VERSION 5.7 ;
BUSBITCHARS "[]" ;
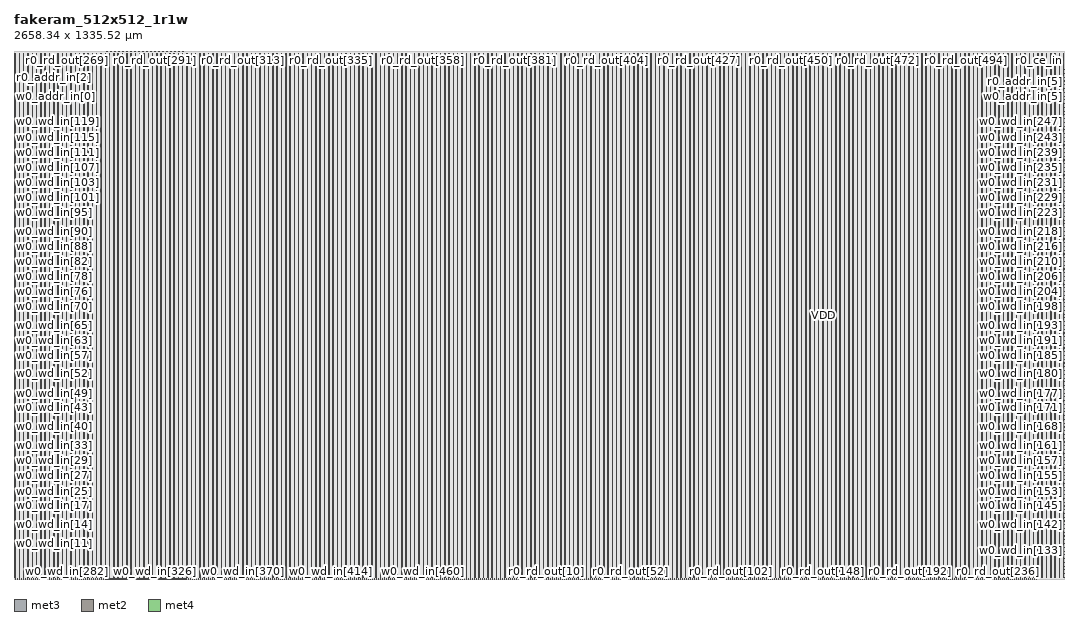
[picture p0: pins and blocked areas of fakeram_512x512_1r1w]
MACRO fakeram_512x512_1r1w
  FOREIGN fakeram_512x512_1r1w 0 0 ;
  SYMMETRY X Y R90 ;
  SIZE 2658.340 BY 1335.520 ;
  CLASS BLOCK ;
  PIN w0_wd_in[0]
    DIRECTION INPUT ;
    USE SIGNAL ;
    SHAPE ABUTMENT ;
    PORT
      LAYER met3 ;
      RECT 0.000 3.930 0.900 4.230 ;
    END
  END w0_wd_in[0]
  PIN w0_wd_in[1]
    DIRECTION INPUT ;
    USE SIGNAL ;
    SHAPE ABUTMENT ;
    PORT
      LAYER met3 ;
      RECT 0.000 13.450 0.900 13.750 ;
    END
  END w0_wd_in[1]
  PIN w0_wd_in[2]
    DIRECTION INPUT ;
    USE SIGNAL ;
    SHAPE ABUTMENT ;
    PORT
      LAYER met3 ;
      RECT 0.000 22.970 0.900 23.270 ;
    END
  END w0_wd_in[2]
  PIN w0_wd_in[3]
    DIRECTION INPUT ;
    USE SIGNAL ;
    SHAPE ABUTMENT ;
    PORT
      LAYER met3 ;
      RECT 0.000 32.490 0.900 32.790 ;
    END
  END w0_wd_in[3]
  PIN w0_wd_in[4]
    DIRECTION INPUT ;
    USE SIGNAL ;
    SHAPE ABUTMENT ;
    PORT
      LAYER met3 ;
      RECT 0.000 42.010 0.900 42.310 ;
    END
  END w0_wd_in[4]
  PIN w0_wd_in[5]
    DIRECTION INPUT ;
    USE SIGNAL ;
    SHAPE ABUTMENT ;
    PORT
      LAYER met3 ;
      RECT 0.000 51.530 0.900 51.830 ;
    END
  END w0_wd_in[5]
  PIN w0_wd_in[6]
    DIRECTION INPUT ;
    USE SIGNAL ;
    SHAPE ABUTMENT ;
    PORT
      LAYER met3 ;
      RECT 0.000 61.050 0.900 61.350 ;
    END
  END w0_wd_in[6]
  PIN w0_wd_in[7]
    DIRECTION INPUT ;
    USE SIGNAL ;
    SHAPE ABUTMENT ;
    PORT
      LAYER met3 ;
      RECT 0.000 70.570 0.900 70.870 ;
    END
  END w0_wd_in[7]
  PIN w0_wd_in[8]
    DIRECTION INPUT ;
    USE SIGNAL ;
    SHAPE ABUTMENT ;
    PORT
      LAYER met3 ;
      RECT 0.000 80.090 0.900 80.390 ;
    END
  END w0_wd_in[8]
  PIN w0_wd_in[9]
    DIRECTION INPUT ;
    USE SIGNAL ;
    SHAPE ABUTMENT ;
    PORT
      LAYER met3 ;
      RECT 0.000 89.610 0.900 89.910 ;
    END
  END w0_wd_in[9]
  PIN w0_wd_in[10]
    DIRECTION INPUT ;
    USE SIGNAL ;
    SHAPE ABUTMENT ;
    PORT
      LAYER met3 ;
      RECT 0.000 99.130 0.900 99.430 ;
    END
  END w0_wd_in[10]
  PIN w0_wd_in[11]
    DIRECTION INPUT ;
    USE SIGNAL ;
    SHAPE ABUTMENT ;
    PORT
      LAYER met3 ;
      RECT 0.000 108.650 0.900 108.950 ;
    END
  END w0_wd_in[11]
  PIN w0_wd_in[12]
    DIRECTION INPUT ;
    USE SIGNAL ;
    SHAPE ABUTMENT ;
    PORT
      LAYER met3 ;
      RECT 0.000 118.170 0.900 118.470 ;
    END
  END w0_wd_in[12]
  PIN w0_wd_in[13]
    DIRECTION INPUT ;
    USE SIGNAL ;
    SHAPE ABUTMENT ;
    PORT
      LAYER met3 ;
      RECT 0.000 127.690 0.900 127.990 ;
    END
  END w0_wd_in[13]
  PIN w0_wd_in[14]
    DIRECTION INPUT ;
    USE SIGNAL ;
    SHAPE ABUTMENT ;
    PORT
      LAYER met3 ;
      RECT 0.000 137.210 0.900 137.510 ;
    END
  END w0_wd_in[14]
  PIN w0_wd_in[15]
    DIRECTION INPUT ;
    USE SIGNAL ;
    SHAPE ABUTMENT ;
    PORT
      LAYER met3 ;
      RECT 0.000 146.730 0.900 147.030 ;
    END
  END w0_wd_in[15]
  PIN w0_wd_in[16]
    DIRECTION INPUT ;
    USE SIGNAL ;
    SHAPE ABUTMENT ;
    PORT
      LAYER met3 ;
      RECT 0.000 156.250 0.900 156.550 ;
    END
  END w0_wd_in[16]
  PIN w0_wd_in[17]
    DIRECTION INPUT ;
    USE SIGNAL ;
    SHAPE ABUTMENT ;
    PORT
      LAYER met3 ;
      RECT 0.000 165.770 0.900 166.070 ;
    END
  END w0_wd_in[17]
  PIN w0_wd_in[18]
    DIRECTION INPUT ;
    USE SIGNAL ;
    SHAPE ABUTMENT ;
    PORT
      LAYER met3 ;
      RECT 0.000 175.290 0.900 175.590 ;
    END
  END w0_wd_in[18]
  PIN w0_wd_in[19]
    DIRECTION INPUT ;
    USE SIGNAL ;
    SHAPE ABUTMENT ;
    PORT
      LAYER met3 ;
      RECT 0.000 184.810 0.900 185.110 ;
    END
  END w0_wd_in[19]
  PIN w0_wd_in[20]
    DIRECTION INPUT ;
    USE SIGNAL ;
    SHAPE ABUTMENT ;
    PORT
      LAYER met3 ;
      RECT 0.000 194.330 0.900 194.630 ;
    END
  END w0_wd_in[20]
  PIN w0_wd_in[21]
    DIRECTION INPUT ;
    USE SIGNAL ;
    SHAPE ABUTMENT ;
    PORT
      LAYER met3 ;
      RECT 0.000 203.850 0.900 204.150 ;
    END
  END w0_wd_in[21]
  PIN w0_wd_in[22]
    DIRECTION INPUT ;
    USE SIGNAL ;
    SHAPE ABUTMENT ;
    PORT
      LAYER met3 ;
      RECT 0.000 213.370 0.900 213.670 ;
    END
  END w0_wd_in[22]
  PIN w0_wd_in[23]
    DIRECTION INPUT ;
    USE SIGNAL ;
    SHAPE ABUTMENT ;
    PORT
      LAYER met3 ;
      RECT 0.000 222.890 0.900 223.190 ;
    END
  END w0_wd_in[23]
  PIN w0_wd_in[24]
    DIRECTION INPUT ;
    USE SIGNAL ;
    SHAPE ABUTMENT ;
    PORT
      LAYER met3 ;
      RECT 0.000 232.410 0.900 232.710 ;
    END
  END w0_wd_in[24]
  PIN w0_wd_in[25]
    DIRECTION INPUT ;
    USE SIGNAL ;
    SHAPE ABUTMENT ;
    PORT
      LAYER met3 ;
      RECT 0.000 241.930 0.900 242.230 ;
    END
  END w0_wd_in[25]
  PIN w0_wd_in[26]
    DIRECTION INPUT ;
    USE SIGNAL ;
    SHAPE ABUTMENT ;
    PORT
      LAYER met3 ;
      RECT 0.000 251.450 0.900 251.750 ;
    END
  END w0_wd_in[26]
  PIN w0_wd_in[27]
    DIRECTION INPUT ;
    USE SIGNAL ;
    SHAPE ABUTMENT ;
    PORT
      LAYER met3 ;
      RECT 0.000 260.970 0.900 261.270 ;
    END
  END w0_wd_in[27]
  PIN w0_wd_in[28]
    DIRECTION INPUT ;
    USE SIGNAL ;
    SHAPE ABUTMENT ;
    PORT
      LAYER met3 ;
      RECT 0.000 270.490 0.900 270.790 ;
    END
  END w0_wd_in[28]
  PIN w0_wd_in[29]
    DIRECTION INPUT ;
    USE SIGNAL ;
    SHAPE ABUTMENT ;
    PORT
      LAYER met3 ;
      RECT 0.000 280.010 0.900 280.310 ;
    END
  END w0_wd_in[29]
  PIN w0_wd_in[30]
    DIRECTION INPUT ;
    USE SIGNAL ;
    SHAPE ABUTMENT ;
    PORT
      LAYER met3 ;
      RECT 0.000 289.530 0.900 289.830 ;
    END
  END w0_wd_in[30]
  PIN w0_wd_in[31]
    DIRECTION INPUT ;
    USE SIGNAL ;
    SHAPE ABUTMENT ;
    PORT
      LAYER met3 ;
      RECT 0.000 299.050 0.900 299.350 ;
    END
  END w0_wd_in[31]
  PIN w0_wd_in[32]
    DIRECTION INPUT ;
    USE SIGNAL ;
    SHAPE ABUTMENT ;
    PORT
      LAYER met3 ;
      RECT 0.000 308.570 0.900 308.870 ;
    END
  END w0_wd_in[32]
  PIN w0_wd_in[33]
    DIRECTION INPUT ;
    USE SIGNAL ;
    SHAPE ABUTMENT ;
    PORT
      LAYER met3 ;
      RECT 0.000 318.090 0.900 318.390 ;
    END
  END w0_wd_in[33]
  PIN w0_wd_in[34]
    DIRECTION INPUT ;
    USE SIGNAL ;
    SHAPE ABUTMENT ;
    PORT
      LAYER met3 ;
      RECT 0.000 327.610 0.900 327.910 ;
    END
  END w0_wd_in[34]
  PIN w0_wd_in[35]
    DIRECTION INPUT ;
    USE SIGNAL ;
    SHAPE ABUTMENT ;
    PORT
      LAYER met3 ;
      RECT 0.000 337.130 0.900 337.430 ;
    END
  END w0_wd_in[35]
  PIN w0_wd_in[36]
    DIRECTION INPUT ;
    USE SIGNAL ;
    SHAPE ABUTMENT ;
    PORT
      LAYER met3 ;
      RECT 0.000 346.650 0.900 346.950 ;
    END
  END w0_wd_in[36]
  PIN w0_wd_in[37]
    DIRECTION INPUT ;
    USE SIGNAL ;
    SHAPE ABUTMENT ;
    PORT
      LAYER met3 ;
      RECT 0.000 356.170 0.900 356.470 ;
    END
  END w0_wd_in[37]
  PIN w0_wd_in[38]
    DIRECTION INPUT ;
    USE SIGNAL ;
    SHAPE ABUTMENT ;
    PORT
      LAYER met3 ;
      RECT 0.000 365.690 0.900 365.990 ;
    END
  END w0_wd_in[38]
  PIN w0_wd_in[39]
    DIRECTION INPUT ;
    USE SIGNAL ;
    SHAPE ABUTMENT ;
    PORT
      LAYER met3 ;
      RECT 0.000 375.210 0.900 375.510 ;
    END
  END w0_wd_in[39]
  PIN w0_wd_in[40]
    DIRECTION INPUT ;
    USE SIGNAL ;
    SHAPE ABUTMENT ;
    PORT
      LAYER met3 ;
      RECT 0.000 384.730 0.900 385.030 ;
    END
  END w0_wd_in[40]
  PIN w0_wd_in[41]
    DIRECTION INPUT ;
    USE SIGNAL ;
    SHAPE ABUTMENT ;
    PORT
      LAYER met3 ;
      RECT 0.000 394.250 0.900 394.550 ;
    END
  END w0_wd_in[41]
  PIN w0_wd_in[42]
    DIRECTION INPUT ;
    USE SIGNAL ;
    SHAPE ABUTMENT ;
    PORT
      LAYER met3 ;
      RECT 0.000 403.770 0.900 404.070 ;
    END
  END w0_wd_in[42]
  PIN w0_wd_in[43]
    DIRECTION INPUT ;
    USE SIGNAL ;
    SHAPE ABUTMENT ;
    PORT
      LAYER met3 ;
      RECT 0.000 413.290 0.900 413.590 ;
    END
  END w0_wd_in[43]
  PIN w0_wd_in[44]
    DIRECTION INPUT ;
    USE SIGNAL ;
    SHAPE ABUTMENT ;
    PORT
      LAYER met3 ;
      RECT 0.000 422.810 0.900 423.110 ;
    END
  END w0_wd_in[44]
  PIN w0_wd_in[45]
    DIRECTION INPUT ;
    USE SIGNAL ;
    SHAPE ABUTMENT ;
    PORT
      LAYER met3 ;
      RECT 0.000 432.330 0.900 432.630 ;
    END
  END w0_wd_in[45]
  PIN w0_wd_in[46]
    DIRECTION INPUT ;
    USE SIGNAL ;
    SHAPE ABUTMENT ;
    PORT
      LAYER met3 ;
      RECT 0.000 441.850 0.900 442.150 ;
    END
  END w0_wd_in[46]
  PIN w0_wd_in[47]
    DIRECTION INPUT ;
    USE SIGNAL ;
    SHAPE ABUTMENT ;
    PORT
      LAYER met3 ;
      RECT 0.000 451.370 0.900 451.670 ;
    END
  END w0_wd_in[47]
  PIN w0_wd_in[48]
    DIRECTION INPUT ;
    USE SIGNAL ;
    SHAPE ABUTMENT ;
    PORT
      LAYER met3 ;
      RECT 0.000 460.890 0.900 461.190 ;
    END
  END w0_wd_in[48]
  PIN w0_wd_in[49]
    DIRECTION INPUT ;
    USE SIGNAL ;
    SHAPE ABUTMENT ;
    PORT
      LAYER met3 ;
      RECT 0.000 470.410 0.900 470.710 ;
    END
  END w0_wd_in[49]
  PIN w0_wd_in[50]
    DIRECTION INPUT ;
    USE SIGNAL ;
    SHAPE ABUTMENT ;
    PORT
      LAYER met3 ;
      RECT 0.000 479.930 0.900 480.230 ;
    END
  END w0_wd_in[50]
  PIN w0_wd_in[51]
    DIRECTION INPUT ;
    USE SIGNAL ;
    SHAPE ABUTMENT ;
    PORT
      LAYER met3 ;
      RECT 0.000 489.450 0.900 489.750 ;
    END
  END w0_wd_in[51]
  PIN w0_wd_in[52]
    DIRECTION INPUT ;
    USE SIGNAL ;
    SHAPE ABUTMENT ;
    PORT
      LAYER met3 ;
      RECT 0.000 498.970 0.900 499.270 ;
    END
  END w0_wd_in[52]
  PIN w0_wd_in[53]
    DIRECTION INPUT ;
    USE SIGNAL ;
    SHAPE ABUTMENT ;
    PORT
      LAYER met3 ;
      RECT 0.000 508.490 0.900 508.790 ;
    END
  END w0_wd_in[53]
  PIN w0_wd_in[54]
    DIRECTION INPUT ;
    USE SIGNAL ;
    SHAPE ABUTMENT ;
    PORT
      LAYER met3 ;
      RECT 0.000 518.010 0.900 518.310 ;
    END
  END w0_wd_in[54]
  PIN w0_wd_in[55]
    DIRECTION INPUT ;
    USE SIGNAL ;
    SHAPE ABUTMENT ;
    PORT
      LAYER met3 ;
      RECT 0.000 527.530 0.900 527.830 ;
    END
  END w0_wd_in[55]
  PIN w0_wd_in[56]
    DIRECTION INPUT ;
    USE SIGNAL ;
    SHAPE ABUTMENT ;
    PORT
      LAYER met3 ;
      RECT 0.000 537.050 0.900 537.350 ;
    END
  END w0_wd_in[56]
  PIN w0_wd_in[57]
    DIRECTION INPUT ;
    USE SIGNAL ;
    SHAPE ABUTMENT ;
    PORT
      LAYER met3 ;
      RECT 0.000 546.570 0.900 546.870 ;
    END
  END w0_wd_in[57]
  PIN w0_wd_in[58]
    DIRECTION INPUT ;
    USE SIGNAL ;
    SHAPE ABUTMENT ;
    PORT
      LAYER met3 ;
      RECT 0.000 556.090 0.900 556.390 ;
    END
  END w0_wd_in[58]
  PIN w0_wd_in[59]
    DIRECTION INPUT ;
    USE SIGNAL ;
    SHAPE ABUTMENT ;
    PORT
      LAYER met3 ;
      RECT 0.000 565.610 0.900 565.910 ;
    END
  END w0_wd_in[59]
  PIN w0_wd_in[60]
    DIRECTION INPUT ;
    USE SIGNAL ;
    SHAPE ABUTMENT ;
    PORT
      LAYER met3 ;
      RECT 0.000 575.130 0.900 575.430 ;
    END
  END w0_wd_in[60]
  PIN w0_wd_in[61]
    DIRECTION INPUT ;
    USE SIGNAL ;
    SHAPE ABUTMENT ;
    PORT
      LAYER met3 ;
      RECT 0.000 584.650 0.900 584.950 ;
    END
  END w0_wd_in[61]
  PIN w0_wd_in[62]
    DIRECTION INPUT ;
    USE SIGNAL ;
    SHAPE ABUTMENT ;
    PORT
      LAYER met3 ;
      RECT 0.000 594.170 0.900 594.470 ;
    END
  END w0_wd_in[62]
  PIN w0_wd_in[63]
    DIRECTION INPUT ;
    USE SIGNAL ;
    SHAPE ABUTMENT ;
    PORT
      LAYER met3 ;
      RECT 0.000 603.690 0.900 603.990 ;
    END
  END w0_wd_in[63]
  PIN w0_wd_in[64]
    DIRECTION INPUT ;
    USE SIGNAL ;
    SHAPE ABUTMENT ;
    PORT
      LAYER met3 ;
      RECT 0.000 613.210 0.900 613.510 ;
    END
  END w0_wd_in[64]
  PIN w0_wd_in[65]
    DIRECTION INPUT ;
    USE SIGNAL ;
    SHAPE ABUTMENT ;
    PORT
      LAYER met3 ;
      RECT 0.000 622.730 0.900 623.030 ;
    END
  END w0_wd_in[65]
  PIN w0_wd_in[66]
    DIRECTION INPUT ;
    USE SIGNAL ;
    SHAPE ABUTMENT ;
    PORT
      LAYER met3 ;
      RECT 0.000 632.250 0.900 632.550 ;
    END
  END w0_wd_in[66]
  PIN w0_wd_in[67]
    DIRECTION INPUT ;
    USE SIGNAL ;
    SHAPE ABUTMENT ;
    PORT
      LAYER met3 ;
      RECT 0.000 641.770 0.900 642.070 ;
    END
  END w0_wd_in[67]
  PIN w0_wd_in[68]
    DIRECTION INPUT ;
    USE SIGNAL ;
    SHAPE ABUTMENT ;
    PORT
      LAYER met3 ;
      RECT 0.000 651.290 0.900 651.590 ;
    END
  END w0_wd_in[68]
  PIN w0_wd_in[69]
    DIRECTION INPUT ;
    USE SIGNAL ;
    SHAPE ABUTMENT ;
    PORT
      LAYER met3 ;
      RECT 0.000 660.810 0.900 661.110 ;
    END
  END w0_wd_in[69]
  PIN w0_wd_in[70]
    DIRECTION INPUT ;
    USE SIGNAL ;
    SHAPE ABUTMENT ;
    PORT
      LAYER met3 ;
      RECT 0.000 670.330 0.900 670.630 ;
    END
  END w0_wd_in[70]
  PIN w0_wd_in[71]
    DIRECTION INPUT ;
    USE SIGNAL ;
    SHAPE ABUTMENT ;
    PORT
      LAYER met3 ;
      RECT 0.000 679.850 0.900 680.150 ;
    END
  END w0_wd_in[71]
  PIN w0_wd_in[72]
    DIRECTION INPUT ;
    USE SIGNAL ;
    SHAPE ABUTMENT ;
    PORT
      LAYER met3 ;
      RECT 0.000 689.370 0.900 689.670 ;
    END
  END w0_wd_in[72]
  PIN w0_wd_in[73]
    DIRECTION INPUT ;
    USE SIGNAL ;
    SHAPE ABUTMENT ;
    PORT
      LAYER met3 ;
      RECT 0.000 698.890 0.900 699.190 ;
    END
  END w0_wd_in[73]
  PIN w0_wd_in[74]
    DIRECTION INPUT ;
    USE SIGNAL ;
    SHAPE ABUTMENT ;
    PORT
      LAYER met3 ;
      RECT 0.000 708.410 0.900 708.710 ;
    END
  END w0_wd_in[74]
  PIN w0_wd_in[75]
    DIRECTION INPUT ;
    USE SIGNAL ;
    SHAPE ABUTMENT ;
    PORT
      LAYER met3 ;
      RECT 0.000 717.930 0.900 718.230 ;
    END
  END w0_wd_in[75]
  PIN w0_wd_in[76]
    DIRECTION INPUT ;
    USE SIGNAL ;
    SHAPE ABUTMENT ;
    PORT
      LAYER met3 ;
      RECT 0.000 727.450 0.900 727.750 ;
    END
  END w0_wd_in[76]
  PIN w0_wd_in[77]
    DIRECTION INPUT ;
    USE SIGNAL ;
    SHAPE ABUTMENT ;
    PORT
      LAYER met3 ;
      RECT 0.000 736.970 0.900 737.270 ;
    END
  END w0_wd_in[77]
  PIN w0_wd_in[78]
    DIRECTION INPUT ;
    USE SIGNAL ;
    SHAPE ABUTMENT ;
    PORT
      LAYER met3 ;
      RECT 0.000 746.490 0.900 746.790 ;
    END
  END w0_wd_in[78]
  PIN w0_wd_in[79]
    DIRECTION INPUT ;
    USE SIGNAL ;
    SHAPE ABUTMENT ;
    PORT
      LAYER met3 ;
      RECT 0.000 756.010 0.900 756.310 ;
    END
  END w0_wd_in[79]
  PIN w0_wd_in[80]
    DIRECTION INPUT ;
    USE SIGNAL ;
    SHAPE ABUTMENT ;
    PORT
      LAYER met3 ;
      RECT 0.000 765.530 0.900 765.830 ;
    END
  END w0_wd_in[80]
  PIN w0_wd_in[81]
    DIRECTION INPUT ;
    USE SIGNAL ;
    SHAPE ABUTMENT ;
    PORT
      LAYER met3 ;
      RECT 0.000 775.050 0.900 775.350 ;
    END
  END w0_wd_in[81]
  PIN w0_wd_in[82]
    DIRECTION INPUT ;
    USE SIGNAL ;
    SHAPE ABUTMENT ;
    PORT
      LAYER met3 ;
      RECT 0.000 784.570 0.900 784.870 ;
    END
  END w0_wd_in[82]
  PIN w0_wd_in[83]
    DIRECTION INPUT ;
    USE SIGNAL ;
    SHAPE ABUTMENT ;
    PORT
      LAYER met3 ;
      RECT 0.000 794.090 0.900 794.390 ;
    END
  END w0_wd_in[83]
  PIN w0_wd_in[84]
    DIRECTION INPUT ;
    USE SIGNAL ;
    SHAPE ABUTMENT ;
    PORT
      LAYER met3 ;
      RECT 0.000 803.610 0.900 803.910 ;
    END
  END w0_wd_in[84]
  PIN w0_wd_in[85]
    DIRECTION INPUT ;
    USE SIGNAL ;
    SHAPE ABUTMENT ;
    PORT
      LAYER met3 ;
      RECT 0.000 813.130 0.900 813.430 ;
    END
  END w0_wd_in[85]
  PIN w0_wd_in[86]
    DIRECTION INPUT ;
    USE SIGNAL ;
    SHAPE ABUTMENT ;
    PORT
      LAYER met3 ;
      RECT 0.000 822.650 0.900 822.950 ;
    END
  END w0_wd_in[86]
  PIN w0_wd_in[87]
    DIRECTION INPUT ;
    USE SIGNAL ;
    SHAPE ABUTMENT ;
    PORT
      LAYER met3 ;
      RECT 0.000 832.170 0.900 832.470 ;
    END
  END w0_wd_in[87]
  PIN w0_wd_in[88]
    DIRECTION INPUT ;
    USE SIGNAL ;
    SHAPE ABUTMENT ;
    PORT
      LAYER met3 ;
      RECT 0.000 841.690 0.900 841.990 ;
    END
  END w0_wd_in[88]
  PIN w0_wd_in[89]
    DIRECTION INPUT ;
    USE SIGNAL ;
    SHAPE ABUTMENT ;
    PORT
      LAYER met3 ;
      RECT 0.000 851.210 0.900 851.510 ;
    END
  END w0_wd_in[89]
  PIN w0_wd_in[90]
    DIRECTION INPUT ;
    USE SIGNAL ;
    SHAPE ABUTMENT ;
    PORT
      LAYER met3 ;
      RECT 0.000 860.730 0.900 861.030 ;
    END
  END w0_wd_in[90]
  PIN w0_wd_in[91]
    DIRECTION INPUT ;
    USE SIGNAL ;
    SHAPE ABUTMENT ;
    PORT
      LAYER met3 ;
      RECT 0.000 870.250 0.900 870.550 ;
    END
  END w0_wd_in[91]
  PIN w0_wd_in[92]
    DIRECTION INPUT ;
    USE SIGNAL ;
    SHAPE ABUTMENT ;
    PORT
      LAYER met3 ;
      RECT 0.000 879.770 0.900 880.070 ;
    END
  END w0_wd_in[92]
  PIN w0_wd_in[93]
    DIRECTION INPUT ;
    USE SIGNAL ;
    SHAPE ABUTMENT ;
    PORT
      LAYER met3 ;
      RECT 0.000 889.290 0.900 889.590 ;
    END
  END w0_wd_in[93]
  PIN w0_wd_in[94]
    DIRECTION INPUT ;
    USE SIGNAL ;
    SHAPE ABUTMENT ;
    PORT
      LAYER met3 ;
      RECT 0.000 898.810 0.900 899.110 ;
    END
  END w0_wd_in[94]
  PIN w0_wd_in[95]
    DIRECTION INPUT ;
    USE SIGNAL ;
    SHAPE ABUTMENT ;
    PORT
      LAYER met3 ;
      RECT 0.000 908.330 0.900 908.630 ;
    END
  END w0_wd_in[95]
  PIN w0_wd_in[96]
    DIRECTION INPUT ;
    USE SIGNAL ;
    SHAPE ABUTMENT ;
    PORT
      LAYER met3 ;
      RECT 0.000 917.850 0.900 918.150 ;
    END
  END w0_wd_in[96]
  PIN w0_wd_in[97]
    DIRECTION INPUT ;
    USE SIGNAL ;
    SHAPE ABUTMENT ;
    PORT
      LAYER met3 ;
      RECT 0.000 927.370 0.900 927.670 ;
    END
  END w0_wd_in[97]
  PIN w0_wd_in[98]
    DIRECTION INPUT ;
    USE SIGNAL ;
    SHAPE ABUTMENT ;
    PORT
      LAYER met3 ;
      RECT 0.000 936.890 0.900 937.190 ;
    END
  END w0_wd_in[98]
  PIN w0_wd_in[99]
    DIRECTION INPUT ;
    USE SIGNAL ;
    SHAPE ABUTMENT ;
    PORT
      LAYER met3 ;
      RECT 0.000 946.410 0.900 946.710 ;
    END
  END w0_wd_in[99]
  PIN w0_wd_in[100]
    DIRECTION INPUT ;
    USE SIGNAL ;
    SHAPE ABUTMENT ;
    PORT
      LAYER met3 ;
      RECT 0.000 955.930 0.900 956.230 ;
    END
  END w0_wd_in[100]
  PIN w0_wd_in[101]
    DIRECTION INPUT ;
    USE SIGNAL ;
    SHAPE ABUTMENT ;
    PORT
      LAYER met3 ;
      RECT 0.000 965.450 0.900 965.750 ;
    END
  END w0_wd_in[101]
  PIN w0_wd_in[102]
    DIRECTION INPUT ;
    USE SIGNAL ;
    SHAPE ABUTMENT ;
    PORT
      LAYER met3 ;
      RECT 0.000 974.970 0.900 975.270 ;
    END
  END w0_wd_in[102]
  PIN w0_wd_in[103]
    DIRECTION INPUT ;
    USE SIGNAL ;
    SHAPE ABUTMENT ;
    PORT
      LAYER met3 ;
      RECT 0.000 984.490 0.900 984.790 ;
    END
  END w0_wd_in[103]
  PIN w0_wd_in[104]
    DIRECTION INPUT ;
    USE SIGNAL ;
    SHAPE ABUTMENT ;
    PORT
      LAYER met3 ;
      RECT 0.000 994.010 0.900 994.310 ;
    END
  END w0_wd_in[104]
  PIN w0_wd_in[105]
    DIRECTION INPUT ;
    USE SIGNAL ;
    SHAPE ABUTMENT ;
    PORT
      LAYER met3 ;
      RECT 0.000 1003.530 0.900 1003.830 ;
    END
  END w0_wd_in[105]
  PIN w0_wd_in[106]
    DIRECTION INPUT ;
    USE SIGNAL ;
    SHAPE ABUTMENT ;
    PORT
      LAYER met3 ;
      RECT 0.000 1013.050 0.900 1013.350 ;
    END
  END w0_wd_in[106]
  PIN w0_wd_in[107]
    DIRECTION INPUT ;
    USE SIGNAL ;
    SHAPE ABUTMENT ;
    PORT
      LAYER met3 ;
      RECT 0.000 1022.570 0.900 1022.870 ;
    END
  END w0_wd_in[107]
  PIN w0_wd_in[108]
    DIRECTION INPUT ;
    USE SIGNAL ;
    SHAPE ABUTMENT ;
    PORT
      LAYER met3 ;
      RECT 0.000 1032.090 0.900 1032.390 ;
    END
  END w0_wd_in[108]
  PIN w0_wd_in[109]
    DIRECTION INPUT ;
    USE SIGNAL ;
    SHAPE ABUTMENT ;
    PORT
      LAYER met3 ;
      RECT 0.000 1041.610 0.900 1041.910 ;
    END
  END w0_wd_in[109]
  PIN w0_wd_in[110]
    DIRECTION INPUT ;
    USE SIGNAL ;
    SHAPE ABUTMENT ;
    PORT
      LAYER met3 ;
      RECT 0.000 1051.130 0.900 1051.430 ;
    END
  END w0_wd_in[110]
  PIN w0_wd_in[111]
    DIRECTION INPUT ;
    USE SIGNAL ;
    SHAPE ABUTMENT ;
    PORT
      LAYER met3 ;
      RECT 0.000 1060.650 0.900 1060.950 ;
    END
  END w0_wd_in[111]
  PIN w0_wd_in[112]
    DIRECTION INPUT ;
    USE SIGNAL ;
    SHAPE ABUTMENT ;
    PORT
      LAYER met3 ;
      RECT 0.000 1070.170 0.900 1070.470 ;
    END
  END w0_wd_in[112]
  PIN w0_wd_in[113]
    DIRECTION INPUT ;
    USE SIGNAL ;
    SHAPE ABUTMENT ;
    PORT
      LAYER met3 ;
      RECT 0.000 1079.690 0.900 1079.990 ;
    END
  END w0_wd_in[113]
  PIN w0_wd_in[114]
    DIRECTION INPUT ;
    USE SIGNAL ;
    SHAPE ABUTMENT ;
    PORT
      LAYER met3 ;
      RECT 0.000 1089.210 0.900 1089.510 ;
    END
  END w0_wd_in[114]
  PIN w0_wd_in[115]
    DIRECTION INPUT ;
    USE SIGNAL ;
    SHAPE ABUTMENT ;
    PORT
      LAYER met3 ;
      RECT 0.000 1098.730 0.900 1099.030 ;
    END
  END w0_wd_in[115]
  PIN w0_wd_in[116]
    DIRECTION INPUT ;
    USE SIGNAL ;
    SHAPE ABUTMENT ;
    PORT
      LAYER met3 ;
      RECT 0.000 1108.250 0.900 1108.550 ;
    END
  END w0_wd_in[116]
  PIN w0_wd_in[117]
    DIRECTION INPUT ;
    USE SIGNAL ;
    SHAPE ABUTMENT ;
    PORT
      LAYER met3 ;
      RECT 0.000 1117.770 0.900 1118.070 ;
    END
  END w0_wd_in[117]
  PIN w0_wd_in[118]
    DIRECTION INPUT ;
    USE SIGNAL ;
    SHAPE ABUTMENT ;
    PORT
      LAYER met3 ;
      RECT 0.000 1127.290 0.900 1127.590 ;
    END
  END w0_wd_in[118]
  PIN w0_wd_in[119]
    DIRECTION INPUT ;
    USE SIGNAL ;
    SHAPE ABUTMENT ;
    PORT
      LAYER met3 ;
      RECT 0.000 1136.810 0.900 1137.110 ;
    END
  END w0_wd_in[119]
  PIN w0_wd_in[120]
    DIRECTION INPUT ;
    USE SIGNAL ;
    SHAPE ABUTMENT ;
    PORT
      LAYER met3 ;
      RECT 0.000 1146.330 0.900 1146.630 ;
    END
  END w0_wd_in[120]
  PIN w0_wd_in[121]
    DIRECTION INPUT ;
    USE SIGNAL ;
    SHAPE ABUTMENT ;
    PORT
      LAYER met3 ;
      RECT 0.000 1155.850 0.900 1156.150 ;
    END
  END w0_wd_in[121]
  PIN w0_wd_in[122]
    DIRECTION INPUT ;
    USE SIGNAL ;
    SHAPE ABUTMENT ;
    PORT
      LAYER met3 ;
      RECT 0.000 1165.370 0.900 1165.670 ;
    END
  END w0_wd_in[122]
  PIN w0_wd_in[123]
    DIRECTION INPUT ;
    USE SIGNAL ;
    SHAPE ABUTMENT ;
    PORT
      LAYER met3 ;
      RECT 0.000 1174.890 0.900 1175.190 ;
    END
  END w0_wd_in[123]
  PIN w0_wd_in[124]
    DIRECTION INPUT ;
    USE SIGNAL ;
    SHAPE ABUTMENT ;
    PORT
      LAYER met3 ;
      RECT 0.000 1184.410 0.900 1184.710 ;
    END
  END w0_wd_in[124]
  PIN w0_wd_in[125]
    DIRECTION INPUT ;
    USE SIGNAL ;
    SHAPE ABUTMENT ;
    PORT
      LAYER met3 ;
      RECT 0.000 1193.930 0.900 1194.230 ;
    END
  END w0_wd_in[125]
  PIN w0_wd_in[126]
    DIRECTION INPUT ;
    USE SIGNAL ;
    SHAPE ABUTMENT ;
    PORT
      LAYER met3 ;
      RECT 0.000 1203.450 0.900 1203.750 ;
    END
  END w0_wd_in[126]
  PIN w0_wd_in[127]
    DIRECTION INPUT ;
    USE SIGNAL ;
    SHAPE ABUTMENT ;
    PORT
      LAYER met3 ;
      RECT 0.000 1212.970 0.900 1213.270 ;
    END
  END w0_wd_in[127]
  PIN w0_wd_in[128]
    DIRECTION INPUT ;
    USE SIGNAL ;
    SHAPE ABUTMENT ;
    PORT
      LAYER met3 ;
      RECT 2657.440 3.930 2658.340 4.230 ;
    END
  END w0_wd_in[128]
  PIN w0_wd_in[129]
    DIRECTION INPUT ;
    USE SIGNAL ;
    SHAPE ABUTMENT ;
    PORT
      LAYER met3 ;
      RECT 2657.440 13.450 2658.340 13.750 ;
    END
  END w0_wd_in[129]
  PIN w0_wd_in[130]
    DIRECTION INPUT ;
    USE SIGNAL ;
    SHAPE ABUTMENT ;
    PORT
      LAYER met3 ;
      RECT 2657.440 22.970 2658.340 23.270 ;
    END
  END w0_wd_in[130]
  PIN w0_wd_in[131]
    DIRECTION INPUT ;
    USE SIGNAL ;
    SHAPE ABUTMENT ;
    PORT
      LAYER met3 ;
      RECT 2657.440 32.490 2658.340 32.790 ;
    END
  END w0_wd_in[131]
  PIN w0_wd_in[132]
    DIRECTION INPUT ;
    USE SIGNAL ;
    SHAPE ABUTMENT ;
    PORT
      LAYER met3 ;
      RECT 2657.440 42.010 2658.340 42.310 ;
    END
  END w0_wd_in[132]
  PIN w0_wd_in[133]
    DIRECTION INPUT ;
    USE SIGNAL ;
    SHAPE ABUTMENT ;
    PORT
      LAYER met3 ;
      RECT 2657.440 51.530 2658.340 51.830 ;
    END
  END w0_wd_in[133]
  PIN w0_wd_in[134]
    DIRECTION INPUT ;
    USE SIGNAL ;
    SHAPE ABUTMENT ;
    PORT
      LAYER met3 ;
      RECT 2657.440 61.050 2658.340 61.350 ;
    END
  END w0_wd_in[134]
  PIN w0_wd_in[135]
    DIRECTION INPUT ;
    USE SIGNAL ;
    SHAPE ABUTMENT ;
    PORT
      LAYER met3 ;
      RECT 2657.440 70.570 2658.340 70.870 ;
    END
  END w0_wd_in[135]
  PIN w0_wd_in[136]
    DIRECTION INPUT ;
    USE SIGNAL ;
    SHAPE ABUTMENT ;
    PORT
      LAYER met3 ;
      RECT 2657.440 80.090 2658.340 80.390 ;
    END
  END w0_wd_in[136]
  PIN w0_wd_in[137]
    DIRECTION INPUT ;
    USE SIGNAL ;
    SHAPE ABUTMENT ;
    PORT
      LAYER met3 ;
      RECT 2657.440 89.610 2658.340 89.910 ;
    END
  END w0_wd_in[137]
  PIN w0_wd_in[138]
    DIRECTION INPUT ;
    USE SIGNAL ;
    SHAPE ABUTMENT ;
    PORT
      LAYER met3 ;
      RECT 2657.440 99.130 2658.340 99.430 ;
    END
  END w0_wd_in[138]
  PIN w0_wd_in[139]
    DIRECTION INPUT ;
    USE SIGNAL ;
    SHAPE ABUTMENT ;
    PORT
      LAYER met3 ;
      RECT 2657.440 108.650 2658.340 108.950 ;
    END
  END w0_wd_in[139]
  PIN w0_wd_in[140]
    DIRECTION INPUT ;
    USE SIGNAL ;
    SHAPE ABUTMENT ;
    PORT
      LAYER met3 ;
      RECT 2657.440 118.170 2658.340 118.470 ;
    END
  END w0_wd_in[140]
  PIN w0_wd_in[141]
    DIRECTION INPUT ;
    USE SIGNAL ;
    SHAPE ABUTMENT ;
    PORT
      LAYER met3 ;
      RECT 2657.440 127.690 2658.340 127.990 ;
    END
  END w0_wd_in[141]
  PIN w0_wd_in[142]
    DIRECTION INPUT ;
    USE SIGNAL ;
    SHAPE ABUTMENT ;
    PORT
      LAYER met3 ;
      RECT 2657.440 137.210 2658.340 137.510 ;
    END
  END w0_wd_in[142]
  PIN w0_wd_in[143]
    DIRECTION INPUT ;
    USE SIGNAL ;
    SHAPE ABUTMENT ;
    PORT
      LAYER met3 ;
      RECT 2657.440 146.730 2658.340 147.030 ;
    END
  END w0_wd_in[143]
  PIN w0_wd_in[144]
    DIRECTION INPUT ;
    USE SIGNAL ;
    SHAPE ABUTMENT ;
    PORT
      LAYER met3 ;
      RECT 2657.440 156.250 2658.340 156.550 ;
    END
  END w0_wd_in[144]
  PIN w0_wd_in[145]
    DIRECTION INPUT ;
    USE SIGNAL ;
    SHAPE ABUTMENT ;
    PORT
      LAYER met3 ;
      RECT 2657.440 165.770 2658.340 166.070 ;
    END
  END w0_wd_in[145]
  PIN w0_wd_in[146]
    DIRECTION INPUT ;
    USE SIGNAL ;
    SHAPE ABUTMENT ;
    PORT
      LAYER met3 ;
      RECT 2657.440 175.290 2658.340 175.590 ;
    END
  END w0_wd_in[146]
  PIN w0_wd_in[147]
    DIRECTION INPUT ;
    USE SIGNAL ;
    SHAPE ABUTMENT ;
    PORT
      LAYER met3 ;
      RECT 2657.440 184.810 2658.340 185.110 ;
    END
  END w0_wd_in[147]
  PIN w0_wd_in[148]
    DIRECTION INPUT ;
    USE SIGNAL ;
    SHAPE ABUTMENT ;
    PORT
      LAYER met3 ;
      RECT 2657.440 194.330 2658.340 194.630 ;
    END
  END w0_wd_in[148]
  PIN w0_wd_in[149]
    DIRECTION INPUT ;
    USE SIGNAL ;
    SHAPE ABUTMENT ;
    PORT
      LAYER met3 ;
      RECT 2657.440 203.850 2658.340 204.150 ;
    END
  END w0_wd_in[149]
  PIN w0_wd_in[150]
    DIRECTION INPUT ;
    USE SIGNAL ;
    SHAPE ABUTMENT ;
    PORT
      LAYER met3 ;
      RECT 2657.440 213.370 2658.340 213.670 ;
    END
  END w0_wd_in[150]
  PIN w0_wd_in[151]
    DIRECTION INPUT ;
    USE SIGNAL ;
    SHAPE ABUTMENT ;
    PORT
      LAYER met3 ;
      RECT 2657.440 222.890 2658.340 223.190 ;
    END
  END w0_wd_in[151]
  PIN w0_wd_in[152]
    DIRECTION INPUT ;
    USE SIGNAL ;
    SHAPE ABUTMENT ;
    PORT
      LAYER met3 ;
      RECT 2657.440 232.410 2658.340 232.710 ;
    END
  END w0_wd_in[152]
  PIN w0_wd_in[153]
    DIRECTION INPUT ;
    USE SIGNAL ;
    SHAPE ABUTMENT ;
    PORT
      LAYER met3 ;
      RECT 2657.440 241.930 2658.340 242.230 ;
    END
  END w0_wd_in[153]
  PIN w0_wd_in[154]
    DIRECTION INPUT ;
    USE SIGNAL ;
    SHAPE ABUTMENT ;
    PORT
      LAYER met3 ;
      RECT 2657.440 251.450 2658.340 251.750 ;
    END
  END w0_wd_in[154]
  PIN w0_wd_in[155]
    DIRECTION INPUT ;
    USE SIGNAL ;
    SHAPE ABUTMENT ;
    PORT
      LAYER met3 ;
      RECT 2657.440 260.970 2658.340 261.270 ;
    END
  END w0_wd_in[155]
  PIN w0_wd_in[156]
    DIRECTION INPUT ;
    USE SIGNAL ;
    SHAPE ABUTMENT ;
    PORT
      LAYER met3 ;
      RECT 2657.440 270.490 2658.340 270.790 ;
    END
  END w0_wd_in[156]
  PIN w0_wd_in[157]
    DIRECTION INPUT ;
    USE SIGNAL ;
    SHAPE ABUTMENT ;
    PORT
      LAYER met3 ;
      RECT 2657.440 280.010 2658.340 280.310 ;
    END
  END w0_wd_in[157]
  PIN w0_wd_in[158]
    DIRECTION INPUT ;
    USE SIGNAL ;
    SHAPE ABUTMENT ;
    PORT
      LAYER met3 ;
      RECT 2657.440 289.530 2658.340 289.830 ;
    END
  END w0_wd_in[158]
  PIN w0_wd_in[159]
    DIRECTION INPUT ;
    USE SIGNAL ;
    SHAPE ABUTMENT ;
    PORT
      LAYER met3 ;
      RECT 2657.440 299.050 2658.340 299.350 ;
    END
  END w0_wd_in[159]
  PIN w0_wd_in[160]
    DIRECTION INPUT ;
    USE SIGNAL ;
    SHAPE ABUTMENT ;
    PORT
      LAYER met3 ;
      RECT 2657.440 308.570 2658.340 308.870 ;
    END
  END w0_wd_in[160]
  PIN w0_wd_in[161]
    DIRECTION INPUT ;
    USE SIGNAL ;
    SHAPE ABUTMENT ;
    PORT
      LAYER met3 ;
      RECT 2657.440 318.090 2658.340 318.390 ;
    END
  END w0_wd_in[161]
  PIN w0_wd_in[162]
    DIRECTION INPUT ;
    USE SIGNAL ;
    SHAPE ABUTMENT ;
    PORT
      LAYER met3 ;
      RECT 2657.440 327.610 2658.340 327.910 ;
    END
  END w0_wd_in[162]
  PIN w0_wd_in[163]
    DIRECTION INPUT ;
    USE SIGNAL ;
    SHAPE ABUTMENT ;
    PORT
      LAYER met3 ;
      RECT 2657.440 337.130 2658.340 337.430 ;
    END
  END w0_wd_in[163]
  PIN w0_wd_in[164]
    DIRECTION INPUT ;
    USE SIGNAL ;
    SHAPE ABUTMENT ;
    PORT
      LAYER met3 ;
      RECT 2657.440 346.650 2658.340 346.950 ;
    END
  END w0_wd_in[164]
  PIN w0_wd_in[165]
    DIRECTION INPUT ;
    USE SIGNAL ;
    SHAPE ABUTMENT ;
    PORT
      LAYER met3 ;
      RECT 2657.440 356.170 2658.340 356.470 ;
    END
  END w0_wd_in[165]
  PIN w0_wd_in[166]
    DIRECTION INPUT ;
    USE SIGNAL ;
    SHAPE ABUTMENT ;
    PORT
      LAYER met3 ;
      RECT 2657.440 365.690 2658.340 365.990 ;
    END
  END w0_wd_in[166]
  PIN w0_wd_in[167]
    DIRECTION INPUT ;
    USE SIGNAL ;
    SHAPE ABUTMENT ;
    PORT
      LAYER met3 ;
      RECT 2657.440 375.210 2658.340 375.510 ;
    END
  END w0_wd_in[167]
  PIN w0_wd_in[168]
    DIRECTION INPUT ;
    USE SIGNAL ;
    SHAPE ABUTMENT ;
    PORT
      LAYER met3 ;
      RECT 2657.440 384.730 2658.340 385.030 ;
    END
  END w0_wd_in[168]
  PIN w0_wd_in[169]
    DIRECTION INPUT ;
    USE SIGNAL ;
    SHAPE ABUTMENT ;
    PORT
      LAYER met3 ;
      RECT 2657.440 394.250 2658.340 394.550 ;
    END
  END w0_wd_in[169]
  PIN w0_wd_in[170]
    DIRECTION INPUT ;
    USE SIGNAL ;
    SHAPE ABUTMENT ;
    PORT
      LAYER met3 ;
      RECT 2657.440 403.770 2658.340 404.070 ;
    END
  END w0_wd_in[170]
  PIN w0_wd_in[171]
    DIRECTION INPUT ;
    USE SIGNAL ;
    SHAPE ABUTMENT ;
    PORT
      LAYER met3 ;
      RECT 2657.440 413.290 2658.340 413.590 ;
    END
  END w0_wd_in[171]
  PIN w0_wd_in[172]
    DIRECTION INPUT ;
    USE SIGNAL ;
    SHAPE ABUTMENT ;
    PORT
      LAYER met3 ;
      RECT 2657.440 422.810 2658.340 423.110 ;
    END
  END w0_wd_in[172]
  PIN w0_wd_in[173]
    DIRECTION INPUT ;
    USE SIGNAL ;
    SHAPE ABUTMENT ;
    PORT
      LAYER met3 ;
      RECT 2657.440 432.330 2658.340 432.630 ;
    END
  END w0_wd_in[173]
  PIN w0_wd_in[174]
    DIRECTION INPUT ;
    USE SIGNAL ;
    SHAPE ABUTMENT ;
    PORT
      LAYER met3 ;
      RECT 2657.440 441.850 2658.340 442.150 ;
    END
  END w0_wd_in[174]
  PIN w0_wd_in[175]
    DIRECTION INPUT ;
    USE SIGNAL ;
    SHAPE ABUTMENT ;
    PORT
      LAYER met3 ;
      RECT 2657.440 451.370 2658.340 451.670 ;
    END
  END w0_wd_in[175]
  PIN w0_wd_in[176]
    DIRECTION INPUT ;
    USE SIGNAL ;
    SHAPE ABUTMENT ;
    PORT
      LAYER met3 ;
      RECT 2657.440 460.890 2658.340 461.190 ;
    END
  END w0_wd_in[176]
  PIN w0_wd_in[177]
    DIRECTION INPUT ;
    USE SIGNAL ;
    SHAPE ABUTMENT ;
    PORT
      LAYER met3 ;
      RECT 2657.440 470.410 2658.340 470.710 ;
    END
  END w0_wd_in[177]
  PIN w0_wd_in[178]
    DIRECTION INPUT ;
    USE SIGNAL ;
    SHAPE ABUTMENT ;
    PORT
      LAYER met3 ;
      RECT 2657.440 479.930 2658.340 480.230 ;
    END
  END w0_wd_in[178]
  PIN w0_wd_in[179]
    DIRECTION INPUT ;
    USE SIGNAL ;
    SHAPE ABUTMENT ;
    PORT
      LAYER met3 ;
      RECT 2657.440 489.450 2658.340 489.750 ;
    END
  END w0_wd_in[179]
  PIN w0_wd_in[180]
    DIRECTION INPUT ;
    USE SIGNAL ;
    SHAPE ABUTMENT ;
    PORT
      LAYER met3 ;
      RECT 2657.440 498.970 2658.340 499.270 ;
    END
  END w0_wd_in[180]
  PIN w0_wd_in[181]
    DIRECTION INPUT ;
    USE SIGNAL ;
    SHAPE ABUTMENT ;
    PORT
      LAYER met3 ;
      RECT 2657.440 508.490 2658.340 508.790 ;
    END
  END w0_wd_in[181]
  PIN w0_wd_in[182]
    DIRECTION INPUT ;
    USE SIGNAL ;
    SHAPE ABUTMENT ;
    PORT
      LAYER met3 ;
      RECT 2657.440 518.010 2658.340 518.310 ;
    END
  END w0_wd_in[182]
  PIN w0_wd_in[183]
    DIRECTION INPUT ;
    USE SIGNAL ;
    SHAPE ABUTMENT ;
    PORT
      LAYER met3 ;
      RECT 2657.440 527.530 2658.340 527.830 ;
    END
  END w0_wd_in[183]
  PIN w0_wd_in[184]
    DIRECTION INPUT ;
    USE SIGNAL ;
    SHAPE ABUTMENT ;
    PORT
      LAYER met3 ;
      RECT 2657.440 537.050 2658.340 537.350 ;
    END
  END w0_wd_in[184]
  PIN w0_wd_in[185]
    DIRECTION INPUT ;
    USE SIGNAL ;
    SHAPE ABUTMENT ;
    PORT
      LAYER met3 ;
      RECT 2657.440 546.570 2658.340 546.870 ;
    END
  END w0_wd_in[185]
  PIN w0_wd_in[186]
    DIRECTION INPUT ;
    USE SIGNAL ;
    SHAPE ABUTMENT ;
    PORT
      LAYER met3 ;
      RECT 2657.440 556.090 2658.340 556.390 ;
    END
  END w0_wd_in[186]
  PIN w0_wd_in[187]
    DIRECTION INPUT ;
    USE SIGNAL ;
    SHAPE ABUTMENT ;
    PORT
      LAYER met3 ;
      RECT 2657.440 565.610 2658.340 565.910 ;
    END
  END w0_wd_in[187]
  PIN w0_wd_in[188]
    DIRECTION INPUT ;
    USE SIGNAL ;
    SHAPE ABUTMENT ;
    PORT
      LAYER met3 ;
      RECT 2657.440 575.130 2658.340 575.430 ;
    END
  END w0_wd_in[188]
  PIN w0_wd_in[189]
    DIRECTION INPUT ;
    USE SIGNAL ;
    SHAPE ABUTMENT ;
    PORT
      LAYER met3 ;
      RECT 2657.440 584.650 2658.340 584.950 ;
    END
  END w0_wd_in[189]
  PIN w0_wd_in[190]
    DIRECTION INPUT ;
    USE SIGNAL ;
    SHAPE ABUTMENT ;
    PORT
      LAYER met3 ;
      RECT 2657.440 594.170 2658.340 594.470 ;
    END
  END w0_wd_in[190]
  PIN w0_wd_in[191]
    DIRECTION INPUT ;
    USE SIGNAL ;
    SHAPE ABUTMENT ;
    PORT
      LAYER met3 ;
      RECT 2657.440 603.690 2658.340 603.990 ;
    END
  END w0_wd_in[191]
  PIN w0_wd_in[192]
    DIRECTION INPUT ;
    USE SIGNAL ;
    SHAPE ABUTMENT ;
    PORT
      LAYER met3 ;
      RECT 2657.440 613.210 2658.340 613.510 ;
    END
  END w0_wd_in[192]
  PIN w0_wd_in[193]
    DIRECTION INPUT ;
    USE SIGNAL ;
    SHAPE ABUTMENT ;
    PORT
      LAYER met3 ;
      RECT 2657.440 622.730 2658.340 623.030 ;
    END
  END w0_wd_in[193]
  PIN w0_wd_in[194]
    DIRECTION INPUT ;
    USE SIGNAL ;
    SHAPE ABUTMENT ;
    PORT
      LAYER met3 ;
      RECT 2657.440 632.250 2658.340 632.550 ;
    END
  END w0_wd_in[194]
  PIN w0_wd_in[195]
    DIRECTION INPUT ;
    USE SIGNAL ;
    SHAPE ABUTMENT ;
    PORT
      LAYER met3 ;
      RECT 2657.440 641.770 2658.340 642.070 ;
    END
  END w0_wd_in[195]
  PIN w0_wd_in[196]
    DIRECTION INPUT ;
    USE SIGNAL ;
    SHAPE ABUTMENT ;
    PORT
      LAYER met3 ;
      RECT 2657.440 651.290 2658.340 651.590 ;
    END
  END w0_wd_in[196]
  PIN w0_wd_in[197]
    DIRECTION INPUT ;
    USE SIGNAL ;
    SHAPE ABUTMENT ;
    PORT
      LAYER met3 ;
      RECT 2657.440 660.810 2658.340 661.110 ;
    END
  END w0_wd_in[197]
  PIN w0_wd_in[198]
    DIRECTION INPUT ;
    USE SIGNAL ;
    SHAPE ABUTMENT ;
    PORT
      LAYER met3 ;
      RECT 2657.440 670.330 2658.340 670.630 ;
    END
  END w0_wd_in[198]
  PIN w0_wd_in[199]
    DIRECTION INPUT ;
    USE SIGNAL ;
    SHAPE ABUTMENT ;
    PORT
      LAYER met3 ;
      RECT 2657.440 679.850 2658.340 680.150 ;
    END
  END w0_wd_in[199]
  PIN w0_wd_in[200]
    DIRECTION INPUT ;
    USE SIGNAL ;
    SHAPE ABUTMENT ;
    PORT
      LAYER met3 ;
      RECT 2657.440 689.370 2658.340 689.670 ;
    END
  END w0_wd_in[200]
  PIN w0_wd_in[201]
    DIRECTION INPUT ;
    USE SIGNAL ;
    SHAPE ABUTMENT ;
    PORT
      LAYER met3 ;
      RECT 2657.440 698.890 2658.340 699.190 ;
    END
  END w0_wd_in[201]
  PIN w0_wd_in[202]
    DIRECTION INPUT ;
    USE SIGNAL ;
    SHAPE ABUTMENT ;
    PORT
      LAYER met3 ;
      RECT 2657.440 708.410 2658.340 708.710 ;
    END
  END w0_wd_in[202]
  PIN w0_wd_in[203]
    DIRECTION INPUT ;
    USE SIGNAL ;
    SHAPE ABUTMENT ;
    PORT
      LAYER met3 ;
      RECT 2657.440 717.930 2658.340 718.230 ;
    END
  END w0_wd_in[203]
  PIN w0_wd_in[204]
    DIRECTION INPUT ;
    USE SIGNAL ;
    SHAPE ABUTMENT ;
    PORT
      LAYER met3 ;
      RECT 2657.440 727.450 2658.340 727.750 ;
    END
  END w0_wd_in[204]
  PIN w0_wd_in[205]
    DIRECTION INPUT ;
    USE SIGNAL ;
    SHAPE ABUTMENT ;
    PORT
      LAYER met3 ;
      RECT 2657.440 736.970 2658.340 737.270 ;
    END
  END w0_wd_in[205]
  PIN w0_wd_in[206]
    DIRECTION INPUT ;
    USE SIGNAL ;
    SHAPE ABUTMENT ;
    PORT
      LAYER met3 ;
      RECT 2657.440 746.490 2658.340 746.790 ;
    END
  END w0_wd_in[206]
  PIN w0_wd_in[207]
    DIRECTION INPUT ;
    USE SIGNAL ;
    SHAPE ABUTMENT ;
    PORT
      LAYER met3 ;
      RECT 2657.440 756.010 2658.340 756.310 ;
    END
  END w0_wd_in[207]
  PIN w0_wd_in[208]
    DIRECTION INPUT ;
    USE SIGNAL ;
    SHAPE ABUTMENT ;
    PORT
      LAYER met3 ;
      RECT 2657.440 765.530 2658.340 765.830 ;
    END
  END w0_wd_in[208]
  PIN w0_wd_in[209]
    DIRECTION INPUT ;
    USE SIGNAL ;
    SHAPE ABUTMENT ;
    PORT
      LAYER met3 ;
      RECT 2657.440 775.050 2658.340 775.350 ;
    END
  END w0_wd_in[209]
  PIN w0_wd_in[210]
    DIRECTION INPUT ;
    USE SIGNAL ;
    SHAPE ABUTMENT ;
    PORT
      LAYER met3 ;
      RECT 2657.440 784.570 2658.340 784.870 ;
    END
  END w0_wd_in[210]
  PIN w0_wd_in[211]
    DIRECTION INPUT ;
    USE SIGNAL ;
    SHAPE ABUTMENT ;
    PORT
      LAYER met3 ;
      RECT 2657.440 794.090 2658.340 794.390 ;
    END
  END w0_wd_in[211]
  PIN w0_wd_in[212]
    DIRECTION INPUT ;
    USE SIGNAL ;
    SHAPE ABUTMENT ;
    PORT
      LAYER met3 ;
      RECT 2657.440 803.610 2658.340 803.910 ;
    END
  END w0_wd_in[212]
  PIN w0_wd_in[213]
    DIRECTION INPUT ;
    USE SIGNAL ;
    SHAPE ABUTMENT ;
    PORT
      LAYER met3 ;
      RECT 2657.440 813.130 2658.340 813.430 ;
    END
  END w0_wd_in[213]
  PIN w0_wd_in[214]
    DIRECTION INPUT ;
    USE SIGNAL ;
    SHAPE ABUTMENT ;
    PORT
      LAYER met3 ;
      RECT 2657.440 822.650 2658.340 822.950 ;
    END
  END w0_wd_in[214]
  PIN w0_wd_in[215]
    DIRECTION INPUT ;
    USE SIGNAL ;
    SHAPE ABUTMENT ;
    PORT
      LAYER met3 ;
      RECT 2657.440 832.170 2658.340 832.470 ;
    END
  END w0_wd_in[215]
  PIN w0_wd_in[216]
    DIRECTION INPUT ;
    USE SIGNAL ;
    SHAPE ABUTMENT ;
    PORT
      LAYER met3 ;
      RECT 2657.440 841.690 2658.340 841.990 ;
    END
  END w0_wd_in[216]
  PIN w0_wd_in[217]
    DIRECTION INPUT ;
    USE SIGNAL ;
    SHAPE ABUTMENT ;
    PORT
      LAYER met3 ;
      RECT 2657.440 851.210 2658.340 851.510 ;
    END
  END w0_wd_in[217]
  PIN w0_wd_in[218]
    DIRECTION INPUT ;
    USE SIGNAL ;
    SHAPE ABUTMENT ;
    PORT
      LAYER met3 ;
      RECT 2657.440 860.730 2658.340 861.030 ;
    END
  END w0_wd_in[218]
  PIN w0_wd_in[219]
    DIRECTION INPUT ;
    USE SIGNAL ;
    SHAPE ABUTMENT ;
    PORT
      LAYER met3 ;
      RECT 2657.440 870.250 2658.340 870.550 ;
    END
  END w0_wd_in[219]
  PIN w0_wd_in[220]
    DIRECTION INPUT ;
    USE SIGNAL ;
    SHAPE ABUTMENT ;
    PORT
      LAYER met3 ;
      RECT 2657.440 879.770 2658.340 880.070 ;
    END
  END w0_wd_in[220]
  PIN w0_wd_in[221]
    DIRECTION INPUT ;
    USE SIGNAL ;
    SHAPE ABUTMENT ;
    PORT
      LAYER met3 ;
      RECT 2657.440 889.290 2658.340 889.590 ;
    END
  END w0_wd_in[221]
  PIN w0_wd_in[222]
    DIRECTION INPUT ;
    USE SIGNAL ;
    SHAPE ABUTMENT ;
    PORT
      LAYER met3 ;
      RECT 2657.440 898.810 2658.340 899.110 ;
    END
  END w0_wd_in[222]
  PIN w0_wd_in[223]
    DIRECTION INPUT ;
    USE SIGNAL ;
    SHAPE ABUTMENT ;
    PORT
      LAYER met3 ;
      RECT 2657.440 908.330 2658.340 908.630 ;
    END
  END w0_wd_in[223]
  PIN w0_wd_in[224]
    DIRECTION INPUT ;
    USE SIGNAL ;
    SHAPE ABUTMENT ;
    PORT
      LAYER met3 ;
      RECT 2657.440 917.850 2658.340 918.150 ;
    END
  END w0_wd_in[224]
  PIN w0_wd_in[225]
    DIRECTION INPUT ;
    USE SIGNAL ;
    SHAPE ABUTMENT ;
    PORT
      LAYER met3 ;
      RECT 2657.440 927.370 2658.340 927.670 ;
    END
  END w0_wd_in[225]
  PIN w0_wd_in[226]
    DIRECTION INPUT ;
    USE SIGNAL ;
    SHAPE ABUTMENT ;
    PORT
      LAYER met3 ;
      RECT 2657.440 936.890 2658.340 937.190 ;
    END
  END w0_wd_in[226]
  PIN w0_wd_in[227]
    DIRECTION INPUT ;
    USE SIGNAL ;
    SHAPE ABUTMENT ;
    PORT
      LAYER met3 ;
      RECT 2657.440 946.410 2658.340 946.710 ;
    END
  END w0_wd_in[227]
  PIN w0_wd_in[228]
    DIRECTION INPUT ;
    USE SIGNAL ;
    SHAPE ABUTMENT ;
    PORT
      LAYER met3 ;
      RECT 2657.440 955.930 2658.340 956.230 ;
    END
  END w0_wd_in[228]
  PIN w0_wd_in[229]
    DIRECTION INPUT ;
    USE SIGNAL ;
    SHAPE ABUTMENT ;
    PORT
      LAYER met3 ;
      RECT 2657.440 965.450 2658.340 965.750 ;
    END
  END w0_wd_in[229]
  PIN w0_wd_in[230]
    DIRECTION INPUT ;
    USE SIGNAL ;
    SHAPE ABUTMENT ;
    PORT
      LAYER met3 ;
      RECT 2657.440 974.970 2658.340 975.270 ;
    END
  END w0_wd_in[230]
  PIN w0_wd_in[231]
    DIRECTION INPUT ;
    USE SIGNAL ;
    SHAPE ABUTMENT ;
    PORT
      LAYER met3 ;
      RECT 2657.440 984.490 2658.340 984.790 ;
    END
  END w0_wd_in[231]
  PIN w0_wd_in[232]
    DIRECTION INPUT ;
    USE SIGNAL ;
    SHAPE ABUTMENT ;
    PORT
      LAYER met3 ;
      RECT 2657.440 994.010 2658.340 994.310 ;
    END
  END w0_wd_in[232]
  PIN w0_wd_in[233]
    DIRECTION INPUT ;
    USE SIGNAL ;
    SHAPE ABUTMENT ;
    PORT
      LAYER met3 ;
      RECT 2657.440 1003.530 2658.340 1003.830 ;
    END
  END w0_wd_in[233]
  PIN w0_wd_in[234]
    DIRECTION INPUT ;
    USE SIGNAL ;
    SHAPE ABUTMENT ;
    PORT
      LAYER met3 ;
      RECT 2657.440 1013.050 2658.340 1013.350 ;
    END
  END w0_wd_in[234]
  PIN w0_wd_in[235]
    DIRECTION INPUT ;
    USE SIGNAL ;
    SHAPE ABUTMENT ;
    PORT
      LAYER met3 ;
      RECT 2657.440 1022.570 2658.340 1022.870 ;
    END
  END w0_wd_in[235]
  PIN w0_wd_in[236]
    DIRECTION INPUT ;
    USE SIGNAL ;
    SHAPE ABUTMENT ;
    PORT
      LAYER met3 ;
      RECT 2657.440 1032.090 2658.340 1032.390 ;
    END
  END w0_wd_in[236]
  PIN w0_wd_in[237]
    DIRECTION INPUT ;
    USE SIGNAL ;
    SHAPE ABUTMENT ;
    PORT
      LAYER met3 ;
      RECT 2657.440 1041.610 2658.340 1041.910 ;
    END
  END w0_wd_in[237]
  PIN w0_wd_in[238]
    DIRECTION INPUT ;
    USE SIGNAL ;
    SHAPE ABUTMENT ;
    PORT
      LAYER met3 ;
      RECT 2657.440 1051.130 2658.340 1051.430 ;
    END
  END w0_wd_in[238]
  PIN w0_wd_in[239]
    DIRECTION INPUT ;
    USE SIGNAL ;
    SHAPE ABUTMENT ;
    PORT
      LAYER met3 ;
      RECT 2657.440 1060.650 2658.340 1060.950 ;
    END
  END w0_wd_in[239]
  PIN w0_wd_in[240]
    DIRECTION INPUT ;
    USE SIGNAL ;
    SHAPE ABUTMENT ;
    PORT
      LAYER met3 ;
      RECT 2657.440 1070.170 2658.340 1070.470 ;
    END
  END w0_wd_in[240]
  PIN w0_wd_in[241]
    DIRECTION INPUT ;
    USE SIGNAL ;
    SHAPE ABUTMENT ;
    PORT
      LAYER met3 ;
      RECT 2657.440 1079.690 2658.340 1079.990 ;
    END
  END w0_wd_in[241]
  PIN w0_wd_in[242]
    DIRECTION INPUT ;
    USE SIGNAL ;
    SHAPE ABUTMENT ;
    PORT
      LAYER met3 ;
      RECT 2657.440 1089.210 2658.340 1089.510 ;
    END
  END w0_wd_in[242]
  PIN w0_wd_in[243]
    DIRECTION INPUT ;
    USE SIGNAL ;
    SHAPE ABUTMENT ;
    PORT
      LAYER met3 ;
      RECT 2657.440 1098.730 2658.340 1099.030 ;
    END
  END w0_wd_in[243]
  PIN w0_wd_in[244]
    DIRECTION INPUT ;
    USE SIGNAL ;
    SHAPE ABUTMENT ;
    PORT
      LAYER met3 ;
      RECT 2657.440 1108.250 2658.340 1108.550 ;
    END
  END w0_wd_in[244]
  PIN w0_wd_in[245]
    DIRECTION INPUT ;
    USE SIGNAL ;
    SHAPE ABUTMENT ;
    PORT
      LAYER met3 ;
      RECT 2657.440 1117.770 2658.340 1118.070 ;
    END
  END w0_wd_in[245]
  PIN w0_wd_in[246]
    DIRECTION INPUT ;
    USE SIGNAL ;
    SHAPE ABUTMENT ;
    PORT
      LAYER met3 ;
      RECT 2657.440 1127.290 2658.340 1127.590 ;
    END
  END w0_wd_in[246]
  PIN w0_wd_in[247]
    DIRECTION INPUT ;
    USE SIGNAL ;
    SHAPE ABUTMENT ;
    PORT
      LAYER met3 ;
      RECT 2657.440 1136.810 2658.340 1137.110 ;
    END
  END w0_wd_in[247]
  PIN w0_wd_in[248]
    DIRECTION INPUT ;
    USE SIGNAL ;
    SHAPE ABUTMENT ;
    PORT
      LAYER met3 ;
      RECT 2657.440 1146.330 2658.340 1146.630 ;
    END
  END w0_wd_in[248]
  PIN w0_wd_in[249]
    DIRECTION INPUT ;
    USE SIGNAL ;
    SHAPE ABUTMENT ;
    PORT
      LAYER met3 ;
      RECT 2657.440 1155.850 2658.340 1156.150 ;
    END
  END w0_wd_in[249]
  PIN w0_wd_in[250]
    DIRECTION INPUT ;
    USE SIGNAL ;
    SHAPE ABUTMENT ;
    PORT
      LAYER met3 ;
      RECT 2657.440 1165.370 2658.340 1165.670 ;
    END
  END w0_wd_in[250]
  PIN w0_wd_in[251]
    DIRECTION INPUT ;
    USE SIGNAL ;
    SHAPE ABUTMENT ;
    PORT
      LAYER met3 ;
      RECT 2657.440 1174.890 2658.340 1175.190 ;
    END
  END w0_wd_in[251]
  PIN w0_wd_in[252]
    DIRECTION INPUT ;
    USE SIGNAL ;
    SHAPE ABUTMENT ;
    PORT
      LAYER met3 ;
      RECT 2657.440 1184.410 2658.340 1184.710 ;
    END
  END w0_wd_in[252]
  PIN w0_wd_in[253]
    DIRECTION INPUT ;
    USE SIGNAL ;
    SHAPE ABUTMENT ;
    PORT
      LAYER met3 ;
      RECT 2657.440 1193.930 2658.340 1194.230 ;
    END
  END w0_wd_in[253]
  PIN w0_wd_in[254]
    DIRECTION INPUT ;
    USE SIGNAL ;
    SHAPE ABUTMENT ;
    PORT
      LAYER met3 ;
      RECT 2657.440 1203.450 2658.340 1203.750 ;
    END
  END w0_wd_in[254]
  PIN w0_wd_in[255]
    DIRECTION INPUT ;
    USE SIGNAL ;
    SHAPE ABUTMENT ;
    PORT
      LAYER met3 ;
      RECT 2657.440 1212.970 2658.340 1213.270 ;
    END
  END w0_wd_in[255]
  PIN w0_wd_in[256]
    DIRECTION OUTPUT ;
    USE SIGNAL ;
    SHAPE ABUTMENT ;
    PORT
      LAYER met2 ;
      RECT 2.690 0.000 2.830 0.420 ;
    END
  END w0_wd_in[256]
  PIN w0_wd_in[257]
    DIRECTION OUTPUT ;
    USE SIGNAL ;
    SHAPE ABUTMENT ;
    PORT
      LAYER met2 ;
      RECT 7.750 0.000 7.890 0.420 ;
    END
  END w0_wd_in[257]
  PIN w0_wd_in[258]
    DIRECTION OUTPUT ;
    USE SIGNAL ;
    SHAPE ABUTMENT ;
    PORT
      LAYER met2 ;
      RECT 12.810 0.000 12.950 0.420 ;
    END
  END w0_wd_in[258]
  PIN w0_wd_in[259]
    DIRECTION OUTPUT ;
    USE SIGNAL ;
    SHAPE ABUTMENT ;
    PORT
      LAYER met2 ;
      RECT 17.870 0.000 18.010 0.420 ;
    END
  END w0_wd_in[259]
  PIN w0_wd_in[260]
    DIRECTION OUTPUT ;
    USE SIGNAL ;
    SHAPE ABUTMENT ;
    PORT
      LAYER met2 ;
      RECT 22.930 0.000 23.070 0.420 ;
    END
  END w0_wd_in[260]
  PIN w0_wd_in[261]
    DIRECTION OUTPUT ;
    USE SIGNAL ;
    SHAPE ABUTMENT ;
    PORT
      LAYER met2 ;
      RECT 27.990 0.000 28.130 0.420 ;
    END
  END w0_wd_in[261]
  PIN w0_wd_in[262]
    DIRECTION OUTPUT ;
    USE SIGNAL ;
    SHAPE ABUTMENT ;
    PORT
      LAYER met2 ;
      RECT 33.050 0.000 33.190 0.420 ;
    END
  END w0_wd_in[262]
  PIN w0_wd_in[263]
    DIRECTION OUTPUT ;
    USE SIGNAL ;
    SHAPE ABUTMENT ;
    PORT
      LAYER met2 ;
      RECT 38.110 0.000 38.250 0.420 ;
    END
  END w0_wd_in[263]
  PIN w0_wd_in[264]
    DIRECTION OUTPUT ;
    USE SIGNAL ;
    SHAPE ABUTMENT ;
    PORT
      LAYER met2 ;
      RECT 43.170 0.000 43.310 0.420 ;
    END
  END w0_wd_in[264]
  PIN w0_wd_in[265]
    DIRECTION OUTPUT ;
    USE SIGNAL ;
    SHAPE ABUTMENT ;
    PORT
      LAYER met2 ;
      RECT 48.230 0.000 48.370 0.420 ;
    END
  END w0_wd_in[265]
  PIN w0_wd_in[266]
    DIRECTION OUTPUT ;
    USE SIGNAL ;
    SHAPE ABUTMENT ;
    PORT
      LAYER met2 ;
      RECT 53.290 0.000 53.430 0.420 ;
    END
  END w0_wd_in[266]
  PIN w0_wd_in[267]
    DIRECTION OUTPUT ;
    USE SIGNAL ;
    SHAPE ABUTMENT ;
    PORT
      LAYER met2 ;
      RECT 58.350 0.000 58.490 0.420 ;
    END
  END w0_wd_in[267]
  PIN w0_wd_in[268]
    DIRECTION OUTPUT ;
    USE SIGNAL ;
    SHAPE ABUTMENT ;
    PORT
      LAYER met2 ;
      RECT 63.410 0.000 63.550 0.420 ;
    END
  END w0_wd_in[268]
  PIN w0_wd_in[269]
    DIRECTION OUTPUT ;
    USE SIGNAL ;
    SHAPE ABUTMENT ;
    PORT
      LAYER met2 ;
      RECT 68.470 0.000 68.610 0.420 ;
    END
  END w0_wd_in[269]
  PIN w0_wd_in[270]
    DIRECTION OUTPUT ;
    USE SIGNAL ;
    SHAPE ABUTMENT ;
    PORT
      LAYER met2 ;
      RECT 73.530 0.000 73.670 0.420 ;
    END
  END w0_wd_in[270]
  PIN w0_wd_in[271]
    DIRECTION OUTPUT ;
    USE SIGNAL ;
    SHAPE ABUTMENT ;
    PORT
      LAYER met2 ;
      RECT 78.590 0.000 78.730 0.420 ;
    END
  END w0_wd_in[271]
  PIN w0_wd_in[272]
    DIRECTION OUTPUT ;
    USE SIGNAL ;
    SHAPE ABUTMENT ;
    PORT
      LAYER met2 ;
      RECT 83.650 0.000 83.790 0.420 ;
    END
  END w0_wd_in[272]
  PIN w0_wd_in[273]
    DIRECTION OUTPUT ;
    USE SIGNAL ;
    SHAPE ABUTMENT ;
    PORT
      LAYER met2 ;
      RECT 88.710 0.000 88.850 0.420 ;
    END
  END w0_wd_in[273]
  PIN w0_wd_in[274]
    DIRECTION OUTPUT ;
    USE SIGNAL ;
    SHAPE ABUTMENT ;
    PORT
      LAYER met2 ;
      RECT 93.770 0.000 93.910 0.420 ;
    END
  END w0_wd_in[274]
  PIN w0_wd_in[275]
    DIRECTION OUTPUT ;
    USE SIGNAL ;
    SHAPE ABUTMENT ;
    PORT
      LAYER met2 ;
      RECT 98.830 0.000 98.970 0.420 ;
    END
  END w0_wd_in[275]
  PIN w0_wd_in[276]
    DIRECTION OUTPUT ;
    USE SIGNAL ;
    SHAPE ABUTMENT ;
    PORT
      LAYER met2 ;
      RECT 103.890 0.000 104.030 0.420 ;
    END
  END w0_wd_in[276]
  PIN w0_wd_in[277]
    DIRECTION OUTPUT ;
    USE SIGNAL ;
    SHAPE ABUTMENT ;
    PORT
      LAYER met2 ;
      RECT 108.950 0.000 109.090 0.420 ;
    END
  END w0_wd_in[277]
  PIN w0_wd_in[278]
    DIRECTION OUTPUT ;
    USE SIGNAL ;
    SHAPE ABUTMENT ;
    PORT
      LAYER met2 ;
      RECT 114.010 0.000 114.150 0.420 ;
    END
  END w0_wd_in[278]
  PIN w0_wd_in[279]
    DIRECTION OUTPUT ;
    USE SIGNAL ;
    SHAPE ABUTMENT ;
    PORT
      LAYER met2 ;
      RECT 119.070 0.000 119.210 0.420 ;
    END
  END w0_wd_in[279]
  PIN w0_wd_in[280]
    DIRECTION OUTPUT ;
    USE SIGNAL ;
    SHAPE ABUTMENT ;
    PORT
      LAYER met2 ;
      RECT 124.130 0.000 124.270 0.420 ;
    END
  END w0_wd_in[280]
  PIN w0_wd_in[281]
    DIRECTION OUTPUT ;
    USE SIGNAL ;
    SHAPE ABUTMENT ;
    PORT
      LAYER met2 ;
      RECT 129.190 0.000 129.330 0.420 ;
    END
  END w0_wd_in[281]
  PIN w0_wd_in[282]
    DIRECTION OUTPUT ;
    USE SIGNAL ;
    SHAPE ABUTMENT ;
    PORT
      LAYER met2 ;
      RECT 134.250 0.000 134.390 0.420 ;
    END
  END w0_wd_in[282]
  PIN w0_wd_in[283]
    DIRECTION OUTPUT ;
    USE SIGNAL ;
    SHAPE ABUTMENT ;
    PORT
      LAYER met2 ;
      RECT 139.310 0.000 139.450 0.420 ;
    END
  END w0_wd_in[283]
  PIN w0_wd_in[284]
    DIRECTION OUTPUT ;
    USE SIGNAL ;
    SHAPE ABUTMENT ;
    PORT
      LAYER met2 ;
      RECT 144.370 0.000 144.510 0.420 ;
    END
  END w0_wd_in[284]
  PIN w0_wd_in[285]
    DIRECTION OUTPUT ;
    USE SIGNAL ;
    SHAPE ABUTMENT ;
    PORT
      LAYER met2 ;
      RECT 149.430 0.000 149.570 0.420 ;
    END
  END w0_wd_in[285]
  PIN w0_wd_in[286]
    DIRECTION OUTPUT ;
    USE SIGNAL ;
    SHAPE ABUTMENT ;
    PORT
      LAYER met2 ;
      RECT 154.490 0.000 154.630 0.420 ;
    END
  END w0_wd_in[286]
  PIN w0_wd_in[287]
    DIRECTION OUTPUT ;
    USE SIGNAL ;
    SHAPE ABUTMENT ;
    PORT
      LAYER met2 ;
      RECT 159.550 0.000 159.690 0.420 ;
    END
  END w0_wd_in[287]
  PIN w0_wd_in[288]
    DIRECTION OUTPUT ;
    USE SIGNAL ;
    SHAPE ABUTMENT ;
    PORT
      LAYER met2 ;
      RECT 164.610 0.000 164.750 0.420 ;
    END
  END w0_wd_in[288]
  PIN w0_wd_in[289]
    DIRECTION OUTPUT ;
    USE SIGNAL ;
    SHAPE ABUTMENT ;
    PORT
      LAYER met2 ;
      RECT 169.670 0.000 169.810 0.420 ;
    END
  END w0_wd_in[289]
  PIN w0_wd_in[290]
    DIRECTION OUTPUT ;
    USE SIGNAL ;
    SHAPE ABUTMENT ;
    PORT
      LAYER met2 ;
      RECT 174.730 0.000 174.870 0.420 ;
    END
  END w0_wd_in[290]
  PIN w0_wd_in[291]
    DIRECTION OUTPUT ;
    USE SIGNAL ;
    SHAPE ABUTMENT ;
    PORT
      LAYER met2 ;
      RECT 179.790 0.000 179.930 0.420 ;
    END
  END w0_wd_in[291]
  PIN w0_wd_in[292]
    DIRECTION OUTPUT ;
    USE SIGNAL ;
    SHAPE ABUTMENT ;
    PORT
      LAYER met2 ;
      RECT 184.850 0.000 184.990 0.420 ;
    END
  END w0_wd_in[292]
  PIN w0_wd_in[293]
    DIRECTION OUTPUT ;
    USE SIGNAL ;
    SHAPE ABUTMENT ;
    PORT
      LAYER met2 ;
      RECT 189.910 0.000 190.050 0.420 ;
    END
  END w0_wd_in[293]
  PIN w0_wd_in[294]
    DIRECTION OUTPUT ;
    USE SIGNAL ;
    SHAPE ABUTMENT ;
    PORT
      LAYER met2 ;
      RECT 194.970 0.000 195.110 0.420 ;
    END
  END w0_wd_in[294]
  PIN w0_wd_in[295]
    DIRECTION OUTPUT ;
    USE SIGNAL ;
    SHAPE ABUTMENT ;
    PORT
      LAYER met2 ;
      RECT 200.030 0.000 200.170 0.420 ;
    END
  END w0_wd_in[295]
  PIN w0_wd_in[296]
    DIRECTION OUTPUT ;
    USE SIGNAL ;
    SHAPE ABUTMENT ;
    PORT
      LAYER met2 ;
      RECT 205.090 0.000 205.230 0.420 ;
    END
  END w0_wd_in[296]
  PIN w0_wd_in[297]
    DIRECTION OUTPUT ;
    USE SIGNAL ;
    SHAPE ABUTMENT ;
    PORT
      LAYER met2 ;
      RECT 210.150 0.000 210.290 0.420 ;
    END
  END w0_wd_in[297]
  PIN w0_wd_in[298]
    DIRECTION OUTPUT ;
    USE SIGNAL ;
    SHAPE ABUTMENT ;
    PORT
      LAYER met2 ;
      RECT 215.210 0.000 215.350 0.420 ;
    END
  END w0_wd_in[298]
  PIN w0_wd_in[299]
    DIRECTION OUTPUT ;
    USE SIGNAL ;
    SHAPE ABUTMENT ;
    PORT
      LAYER met2 ;
      RECT 220.270 0.000 220.410 0.420 ;
    END
  END w0_wd_in[299]
  PIN w0_wd_in[300]
    DIRECTION OUTPUT ;
    USE SIGNAL ;
    SHAPE ABUTMENT ;
    PORT
      LAYER met2 ;
      RECT 225.330 0.000 225.470 0.420 ;
    END
  END w0_wd_in[300]
  PIN w0_wd_in[301]
    DIRECTION OUTPUT ;
    USE SIGNAL ;
    SHAPE ABUTMENT ;
    PORT
      LAYER met2 ;
      RECT 230.390 0.000 230.530 0.420 ;
    END
  END w0_wd_in[301]
  PIN w0_wd_in[302]
    DIRECTION OUTPUT ;
    USE SIGNAL ;
    SHAPE ABUTMENT ;
    PORT
      LAYER met2 ;
      RECT 235.450 0.000 235.590 0.420 ;
    END
  END w0_wd_in[302]
  PIN w0_wd_in[303]
    DIRECTION OUTPUT ;
    USE SIGNAL ;
    SHAPE ABUTMENT ;
    PORT
      LAYER met2 ;
      RECT 240.510 0.000 240.650 0.420 ;
    END
  END w0_wd_in[303]
  PIN w0_wd_in[304]
    DIRECTION OUTPUT ;
    USE SIGNAL ;
    SHAPE ABUTMENT ;
    PORT
      LAYER met2 ;
      RECT 245.570 0.000 245.710 0.420 ;
    END
  END w0_wd_in[304]
  PIN w0_wd_in[305]
    DIRECTION OUTPUT ;
    USE SIGNAL ;
    SHAPE ABUTMENT ;
    PORT
      LAYER met2 ;
      RECT 250.630 0.000 250.770 0.420 ;
    END
  END w0_wd_in[305]
  PIN w0_wd_in[306]
    DIRECTION OUTPUT ;
    USE SIGNAL ;
    SHAPE ABUTMENT ;
    PORT
      LAYER met2 ;
      RECT 255.690 0.000 255.830 0.420 ;
    END
  END w0_wd_in[306]
  PIN w0_wd_in[307]
    DIRECTION OUTPUT ;
    USE SIGNAL ;
    SHAPE ABUTMENT ;
    PORT
      LAYER met2 ;
      RECT 260.750 0.000 260.890 0.420 ;
    END
  END w0_wd_in[307]
  PIN w0_wd_in[308]
    DIRECTION OUTPUT ;
    USE SIGNAL ;
    SHAPE ABUTMENT ;
    PORT
      LAYER met2 ;
      RECT 265.810 0.000 265.950 0.420 ;
    END
  END w0_wd_in[308]
  PIN w0_wd_in[309]
    DIRECTION OUTPUT ;
    USE SIGNAL ;
    SHAPE ABUTMENT ;
    PORT
      LAYER met2 ;
      RECT 270.870 0.000 271.010 0.420 ;
    END
  END w0_wd_in[309]
  PIN w0_wd_in[310]
    DIRECTION OUTPUT ;
    USE SIGNAL ;
    SHAPE ABUTMENT ;
    PORT
      LAYER met2 ;
      RECT 275.930 0.000 276.070 0.420 ;
    END
  END w0_wd_in[310]
  PIN w0_wd_in[311]
    DIRECTION OUTPUT ;
    USE SIGNAL ;
    SHAPE ABUTMENT ;
    PORT
      LAYER met2 ;
      RECT 280.990 0.000 281.130 0.420 ;
    END
  END w0_wd_in[311]
  PIN w0_wd_in[312]
    DIRECTION OUTPUT ;
    USE SIGNAL ;
    SHAPE ABUTMENT ;
    PORT
      LAYER met2 ;
      RECT 286.050 0.000 286.190 0.420 ;
    END
  END w0_wd_in[312]
  PIN w0_wd_in[313]
    DIRECTION OUTPUT ;
    USE SIGNAL ;
    SHAPE ABUTMENT ;
    PORT
      LAYER met2 ;
      RECT 291.110 0.000 291.250 0.420 ;
    END
  END w0_wd_in[313]
  PIN w0_wd_in[314]
    DIRECTION OUTPUT ;
    USE SIGNAL ;
    SHAPE ABUTMENT ;
    PORT
      LAYER met2 ;
      RECT 296.170 0.000 296.310 0.420 ;
    END
  END w0_wd_in[314]
  PIN w0_wd_in[315]
    DIRECTION OUTPUT ;
    USE SIGNAL ;
    SHAPE ABUTMENT ;
    PORT
      LAYER met2 ;
      RECT 301.230 0.000 301.370 0.420 ;
    END
  END w0_wd_in[315]
  PIN w0_wd_in[316]
    DIRECTION OUTPUT ;
    USE SIGNAL ;
    SHAPE ABUTMENT ;
    PORT
      LAYER met2 ;
      RECT 306.290 0.000 306.430 0.420 ;
    END
  END w0_wd_in[316]
  PIN w0_wd_in[317]
    DIRECTION OUTPUT ;
    USE SIGNAL ;
    SHAPE ABUTMENT ;
    PORT
      LAYER met2 ;
      RECT 311.350 0.000 311.490 0.420 ;
    END
  END w0_wd_in[317]
  PIN w0_wd_in[318]
    DIRECTION OUTPUT ;
    USE SIGNAL ;
    SHAPE ABUTMENT ;
    PORT
      LAYER met2 ;
      RECT 316.410 0.000 316.550 0.420 ;
    END
  END w0_wd_in[318]
  PIN w0_wd_in[319]
    DIRECTION OUTPUT ;
    USE SIGNAL ;
    SHAPE ABUTMENT ;
    PORT
      LAYER met2 ;
      RECT 321.470 0.000 321.610 0.420 ;
    END
  END w0_wd_in[319]
  PIN w0_wd_in[320]
    DIRECTION OUTPUT ;
    USE SIGNAL ;
    SHAPE ABUTMENT ;
    PORT
      LAYER met2 ;
      RECT 326.530 0.000 326.670 0.420 ;
    END
  END w0_wd_in[320]
  PIN w0_wd_in[321]
    DIRECTION OUTPUT ;
    USE SIGNAL ;
    SHAPE ABUTMENT ;
    PORT
      LAYER met2 ;
      RECT 331.590 0.000 331.730 0.420 ;
    END
  END w0_wd_in[321]
  PIN w0_wd_in[322]
    DIRECTION OUTPUT ;
    USE SIGNAL ;
    SHAPE ABUTMENT ;
    PORT
      LAYER met2 ;
      RECT 336.650 0.000 336.790 0.420 ;
    END
  END w0_wd_in[322]
  PIN w0_wd_in[323]
    DIRECTION OUTPUT ;
    USE SIGNAL ;
    SHAPE ABUTMENT ;
    PORT
      LAYER met2 ;
      RECT 341.710 0.000 341.850 0.420 ;
    END
  END w0_wd_in[323]
  PIN w0_wd_in[324]
    DIRECTION OUTPUT ;
    USE SIGNAL ;
    SHAPE ABUTMENT ;
    PORT
      LAYER met2 ;
      RECT 346.770 0.000 346.910 0.420 ;
    END
  END w0_wd_in[324]
  PIN w0_wd_in[325]
    DIRECTION OUTPUT ;
    USE SIGNAL ;
    SHAPE ABUTMENT ;
    PORT
      LAYER met2 ;
      RECT 351.830 0.000 351.970 0.420 ;
    END
  END w0_wd_in[325]
  PIN w0_wd_in[326]
    DIRECTION OUTPUT ;
    USE SIGNAL ;
    SHAPE ABUTMENT ;
    PORT
      LAYER met2 ;
      RECT 356.890 0.000 357.030 0.420 ;
    END
  END w0_wd_in[326]
  PIN w0_wd_in[327]
    DIRECTION OUTPUT ;
    USE SIGNAL ;
    SHAPE ABUTMENT ;
    PORT
      LAYER met2 ;
      RECT 361.950 0.000 362.090 0.420 ;
    END
  END w0_wd_in[327]
  PIN w0_wd_in[328]
    DIRECTION OUTPUT ;
    USE SIGNAL ;
    SHAPE ABUTMENT ;
    PORT
      LAYER met2 ;
      RECT 367.010 0.000 367.150 0.420 ;
    END
  END w0_wd_in[328]
  PIN w0_wd_in[329]
    DIRECTION OUTPUT ;
    USE SIGNAL ;
    SHAPE ABUTMENT ;
    PORT
      LAYER met2 ;
      RECT 372.070 0.000 372.210 0.420 ;
    END
  END w0_wd_in[329]
  PIN w0_wd_in[330]
    DIRECTION OUTPUT ;
    USE SIGNAL ;
    SHAPE ABUTMENT ;
    PORT
      LAYER met2 ;
      RECT 377.130 0.000 377.270 0.420 ;
    END
  END w0_wd_in[330]
  PIN w0_wd_in[331]
    DIRECTION OUTPUT ;
    USE SIGNAL ;
    SHAPE ABUTMENT ;
    PORT
      LAYER met2 ;
      RECT 382.190 0.000 382.330 0.420 ;
    END
  END w0_wd_in[331]
  PIN w0_wd_in[332]
    DIRECTION OUTPUT ;
    USE SIGNAL ;
    SHAPE ABUTMENT ;
    PORT
      LAYER met2 ;
      RECT 387.250 0.000 387.390 0.420 ;
    END
  END w0_wd_in[332]
  PIN w0_wd_in[333]
    DIRECTION OUTPUT ;
    USE SIGNAL ;
    SHAPE ABUTMENT ;
    PORT
      LAYER met2 ;
      RECT 392.310 0.000 392.450 0.420 ;
    END
  END w0_wd_in[333]
  PIN w0_wd_in[334]
    DIRECTION OUTPUT ;
    USE SIGNAL ;
    SHAPE ABUTMENT ;
    PORT
      LAYER met2 ;
      RECT 397.370 0.000 397.510 0.420 ;
    END
  END w0_wd_in[334]
  PIN w0_wd_in[335]
    DIRECTION OUTPUT ;
    USE SIGNAL ;
    SHAPE ABUTMENT ;
    PORT
      LAYER met2 ;
      RECT 402.430 0.000 402.570 0.420 ;
    END
  END w0_wd_in[335]
  PIN w0_wd_in[336]
    DIRECTION OUTPUT ;
    USE SIGNAL ;
    SHAPE ABUTMENT ;
    PORT
      LAYER met2 ;
      RECT 407.490 0.000 407.630 0.420 ;
    END
  END w0_wd_in[336]
  PIN w0_wd_in[337]
    DIRECTION OUTPUT ;
    USE SIGNAL ;
    SHAPE ABUTMENT ;
    PORT
      LAYER met2 ;
      RECT 412.550 0.000 412.690 0.420 ;
    END
  END w0_wd_in[337]
  PIN w0_wd_in[338]
    DIRECTION OUTPUT ;
    USE SIGNAL ;
    SHAPE ABUTMENT ;
    PORT
      LAYER met2 ;
      RECT 417.610 0.000 417.750 0.420 ;
    END
  END w0_wd_in[338]
  PIN w0_wd_in[339]
    DIRECTION OUTPUT ;
    USE SIGNAL ;
    SHAPE ABUTMENT ;
    PORT
      LAYER met2 ;
      RECT 422.670 0.000 422.810 0.420 ;
    END
  END w0_wd_in[339]
  PIN w0_wd_in[340]
    DIRECTION OUTPUT ;
    USE SIGNAL ;
    SHAPE ABUTMENT ;
    PORT
      LAYER met2 ;
      RECT 427.730 0.000 427.870 0.420 ;
    END
  END w0_wd_in[340]
  PIN w0_wd_in[341]
    DIRECTION OUTPUT ;
    USE SIGNAL ;
    SHAPE ABUTMENT ;
    PORT
      LAYER met2 ;
      RECT 432.790 0.000 432.930 0.420 ;
    END
  END w0_wd_in[341]
  PIN w0_wd_in[342]
    DIRECTION OUTPUT ;
    USE SIGNAL ;
    SHAPE ABUTMENT ;
    PORT
      LAYER met2 ;
      RECT 437.850 0.000 437.990 0.420 ;
    END
  END w0_wd_in[342]
  PIN w0_wd_in[343]
    DIRECTION OUTPUT ;
    USE SIGNAL ;
    SHAPE ABUTMENT ;
    PORT
      LAYER met2 ;
      RECT 442.910 0.000 443.050 0.420 ;
    END
  END w0_wd_in[343]
  PIN w0_wd_in[344]
    DIRECTION OUTPUT ;
    USE SIGNAL ;
    SHAPE ABUTMENT ;
    PORT
      LAYER met2 ;
      RECT 447.970 0.000 448.110 0.420 ;
    END
  END w0_wd_in[344]
  PIN w0_wd_in[345]
    DIRECTION OUTPUT ;
    USE SIGNAL ;
    SHAPE ABUTMENT ;
    PORT
      LAYER met2 ;
      RECT 453.030 0.000 453.170 0.420 ;
    END
  END w0_wd_in[345]
  PIN w0_wd_in[346]
    DIRECTION OUTPUT ;
    USE SIGNAL ;
    SHAPE ABUTMENT ;
    PORT
      LAYER met2 ;
      RECT 458.090 0.000 458.230 0.420 ;
    END
  END w0_wd_in[346]
  PIN w0_wd_in[347]
    DIRECTION OUTPUT ;
    USE SIGNAL ;
    SHAPE ABUTMENT ;
    PORT
      LAYER met2 ;
      RECT 463.150 0.000 463.290 0.420 ;
    END
  END w0_wd_in[347]
  PIN w0_wd_in[348]
    DIRECTION OUTPUT ;
    USE SIGNAL ;
    SHAPE ABUTMENT ;
    PORT
      LAYER met2 ;
      RECT 468.210 0.000 468.350 0.420 ;
    END
  END w0_wd_in[348]
  PIN w0_wd_in[349]
    DIRECTION OUTPUT ;
    USE SIGNAL ;
    SHAPE ABUTMENT ;
    PORT
      LAYER met2 ;
      RECT 473.270 0.000 473.410 0.420 ;
    END
  END w0_wd_in[349]
  PIN w0_wd_in[350]
    DIRECTION OUTPUT ;
    USE SIGNAL ;
    SHAPE ABUTMENT ;
    PORT
      LAYER met2 ;
      RECT 478.330 0.000 478.470 0.420 ;
    END
  END w0_wd_in[350]
  PIN w0_wd_in[351]
    DIRECTION OUTPUT ;
    USE SIGNAL ;
    SHAPE ABUTMENT ;
    PORT
      LAYER met2 ;
      RECT 483.390 0.000 483.530 0.420 ;
    END
  END w0_wd_in[351]
  PIN w0_wd_in[352]
    DIRECTION OUTPUT ;
    USE SIGNAL ;
    SHAPE ABUTMENT ;
    PORT
      LAYER met2 ;
      RECT 488.450 0.000 488.590 0.420 ;
    END
  END w0_wd_in[352]
  PIN w0_wd_in[353]
    DIRECTION OUTPUT ;
    USE SIGNAL ;
    SHAPE ABUTMENT ;
    PORT
      LAYER met2 ;
      RECT 493.510 0.000 493.650 0.420 ;
    END
  END w0_wd_in[353]
  PIN w0_wd_in[354]
    DIRECTION OUTPUT ;
    USE SIGNAL ;
    SHAPE ABUTMENT ;
    PORT
      LAYER met2 ;
      RECT 498.570 0.000 498.710 0.420 ;
    END
  END w0_wd_in[354]
  PIN w0_wd_in[355]
    DIRECTION OUTPUT ;
    USE SIGNAL ;
    SHAPE ABUTMENT ;
    PORT
      LAYER met2 ;
      RECT 503.630 0.000 503.770 0.420 ;
    END
  END w0_wd_in[355]
  PIN w0_wd_in[356]
    DIRECTION OUTPUT ;
    USE SIGNAL ;
    SHAPE ABUTMENT ;
    PORT
      LAYER met2 ;
      RECT 508.690 0.000 508.830 0.420 ;
    END
  END w0_wd_in[356]
  PIN w0_wd_in[357]
    DIRECTION OUTPUT ;
    USE SIGNAL ;
    SHAPE ABUTMENT ;
    PORT
      LAYER met2 ;
      RECT 513.750 0.000 513.890 0.420 ;
    END
  END w0_wd_in[357]
  PIN w0_wd_in[358]
    DIRECTION OUTPUT ;
    USE SIGNAL ;
    SHAPE ABUTMENT ;
    PORT
      LAYER met2 ;
      RECT 518.810 0.000 518.950 0.420 ;
    END
  END w0_wd_in[358]
  PIN w0_wd_in[359]
    DIRECTION OUTPUT ;
    USE SIGNAL ;
    SHAPE ABUTMENT ;
    PORT
      LAYER met2 ;
      RECT 523.870 0.000 524.010 0.420 ;
    END
  END w0_wd_in[359]
  PIN w0_wd_in[360]
    DIRECTION OUTPUT ;
    USE SIGNAL ;
    SHAPE ABUTMENT ;
    PORT
      LAYER met2 ;
      RECT 528.930 0.000 529.070 0.420 ;
    END
  END w0_wd_in[360]
  PIN w0_wd_in[361]
    DIRECTION OUTPUT ;
    USE SIGNAL ;
    SHAPE ABUTMENT ;
    PORT
      LAYER met2 ;
      RECT 533.990 0.000 534.130 0.420 ;
    END
  END w0_wd_in[361]
  PIN w0_wd_in[362]
    DIRECTION OUTPUT ;
    USE SIGNAL ;
    SHAPE ABUTMENT ;
    PORT
      LAYER met2 ;
      RECT 539.050 0.000 539.190 0.420 ;
    END
  END w0_wd_in[362]
  PIN w0_wd_in[363]
    DIRECTION OUTPUT ;
    USE SIGNAL ;
    SHAPE ABUTMENT ;
    PORT
      LAYER met2 ;
      RECT 544.110 0.000 544.250 0.420 ;
    END
  END w0_wd_in[363]
  PIN w0_wd_in[364]
    DIRECTION OUTPUT ;
    USE SIGNAL ;
    SHAPE ABUTMENT ;
    PORT
      LAYER met2 ;
      RECT 549.170 0.000 549.310 0.420 ;
    END
  END w0_wd_in[364]
  PIN w0_wd_in[365]
    DIRECTION OUTPUT ;
    USE SIGNAL ;
    SHAPE ABUTMENT ;
    PORT
      LAYER met2 ;
      RECT 554.230 0.000 554.370 0.420 ;
    END
  END w0_wd_in[365]
  PIN w0_wd_in[366]
    DIRECTION OUTPUT ;
    USE SIGNAL ;
    SHAPE ABUTMENT ;
    PORT
      LAYER met2 ;
      RECT 559.290 0.000 559.430 0.420 ;
    END
  END w0_wd_in[366]
  PIN w0_wd_in[367]
    DIRECTION OUTPUT ;
    USE SIGNAL ;
    SHAPE ABUTMENT ;
    PORT
      LAYER met2 ;
      RECT 564.350 0.000 564.490 0.420 ;
    END
  END w0_wd_in[367]
  PIN w0_wd_in[368]
    DIRECTION OUTPUT ;
    USE SIGNAL ;
    SHAPE ABUTMENT ;
    PORT
      LAYER met2 ;
      RECT 569.410 0.000 569.550 0.420 ;
    END
  END w0_wd_in[368]
  PIN w0_wd_in[369]
    DIRECTION OUTPUT ;
    USE SIGNAL ;
    SHAPE ABUTMENT ;
    PORT
      LAYER met2 ;
      RECT 574.470 0.000 574.610 0.420 ;
    END
  END w0_wd_in[369]
  PIN w0_wd_in[370]
    DIRECTION OUTPUT ;
    USE SIGNAL ;
    SHAPE ABUTMENT ;
    PORT
      LAYER met2 ;
      RECT 579.530 0.000 579.670 0.420 ;
    END
  END w0_wd_in[370]
  PIN w0_wd_in[371]
    DIRECTION OUTPUT ;
    USE SIGNAL ;
    SHAPE ABUTMENT ;
    PORT
      LAYER met2 ;
      RECT 584.590 0.000 584.730 0.420 ;
    END
  END w0_wd_in[371]
  PIN w0_wd_in[372]
    DIRECTION OUTPUT ;
    USE SIGNAL ;
    SHAPE ABUTMENT ;
    PORT
      LAYER met2 ;
      RECT 589.650 0.000 589.790 0.420 ;
    END
  END w0_wd_in[372]
  PIN w0_wd_in[373]
    DIRECTION OUTPUT ;
    USE SIGNAL ;
    SHAPE ABUTMENT ;
    PORT
      LAYER met2 ;
      RECT 594.710 0.000 594.850 0.420 ;
    END
  END w0_wd_in[373]
  PIN w0_wd_in[374]
    DIRECTION OUTPUT ;
    USE SIGNAL ;
    SHAPE ABUTMENT ;
    PORT
      LAYER met2 ;
      RECT 599.770 0.000 599.910 0.420 ;
    END
  END w0_wd_in[374]
  PIN w0_wd_in[375]
    DIRECTION OUTPUT ;
    USE SIGNAL ;
    SHAPE ABUTMENT ;
    PORT
      LAYER met2 ;
      RECT 604.830 0.000 604.970 0.420 ;
    END
  END w0_wd_in[375]
  PIN w0_wd_in[376]
    DIRECTION OUTPUT ;
    USE SIGNAL ;
    SHAPE ABUTMENT ;
    PORT
      LAYER met2 ;
      RECT 609.890 0.000 610.030 0.420 ;
    END
  END w0_wd_in[376]
  PIN w0_wd_in[377]
    DIRECTION OUTPUT ;
    USE SIGNAL ;
    SHAPE ABUTMENT ;
    PORT
      LAYER met2 ;
      RECT 614.950 0.000 615.090 0.420 ;
    END
  END w0_wd_in[377]
  PIN w0_wd_in[378]
    DIRECTION OUTPUT ;
    USE SIGNAL ;
    SHAPE ABUTMENT ;
    PORT
      LAYER met2 ;
      RECT 620.010 0.000 620.150 0.420 ;
    END
  END w0_wd_in[378]
  PIN w0_wd_in[379]
    DIRECTION OUTPUT ;
    USE SIGNAL ;
    SHAPE ABUTMENT ;
    PORT
      LAYER met2 ;
      RECT 625.070 0.000 625.210 0.420 ;
    END
  END w0_wd_in[379]
  PIN w0_wd_in[380]
    DIRECTION OUTPUT ;
    USE SIGNAL ;
    SHAPE ABUTMENT ;
    PORT
      LAYER met2 ;
      RECT 630.130 0.000 630.270 0.420 ;
    END
  END w0_wd_in[380]
  PIN w0_wd_in[381]
    DIRECTION OUTPUT ;
    USE SIGNAL ;
    SHAPE ABUTMENT ;
    PORT
      LAYER met2 ;
      RECT 635.190 0.000 635.330 0.420 ;
    END
  END w0_wd_in[381]
  PIN w0_wd_in[382]
    DIRECTION OUTPUT ;
    USE SIGNAL ;
    SHAPE ABUTMENT ;
    PORT
      LAYER met2 ;
      RECT 640.250 0.000 640.390 0.420 ;
    END
  END w0_wd_in[382]
  PIN w0_wd_in[383]
    DIRECTION OUTPUT ;
    USE SIGNAL ;
    SHAPE ABUTMENT ;
    PORT
      LAYER met2 ;
      RECT 645.310 0.000 645.450 0.420 ;
    END
  END w0_wd_in[383]
  PIN w0_wd_in[384]
    DIRECTION OUTPUT ;
    USE SIGNAL ;
    SHAPE ABUTMENT ;
    PORT
      LAYER met2 ;
      RECT 650.370 0.000 650.510 0.420 ;
    END
  END w0_wd_in[384]
  PIN w0_wd_in[385]
    DIRECTION OUTPUT ;
    USE SIGNAL ;
    SHAPE ABUTMENT ;
    PORT
      LAYER met2 ;
      RECT 655.430 0.000 655.570 0.420 ;
    END
  END w0_wd_in[385]
  PIN w0_wd_in[386]
    DIRECTION OUTPUT ;
    USE SIGNAL ;
    SHAPE ABUTMENT ;
    PORT
      LAYER met2 ;
      RECT 660.490 0.000 660.630 0.420 ;
    END
  END w0_wd_in[386]
  PIN w0_wd_in[387]
    DIRECTION OUTPUT ;
    USE SIGNAL ;
    SHAPE ABUTMENT ;
    PORT
      LAYER met2 ;
      RECT 665.550 0.000 665.690 0.420 ;
    END
  END w0_wd_in[387]
  PIN w0_wd_in[388]
    DIRECTION OUTPUT ;
    USE SIGNAL ;
    SHAPE ABUTMENT ;
    PORT
      LAYER met2 ;
      RECT 670.610 0.000 670.750 0.420 ;
    END
  END w0_wd_in[388]
  PIN w0_wd_in[389]
    DIRECTION OUTPUT ;
    USE SIGNAL ;
    SHAPE ABUTMENT ;
    PORT
      LAYER met2 ;
      RECT 675.670 0.000 675.810 0.420 ;
    END
  END w0_wd_in[389]
  PIN w0_wd_in[390]
    DIRECTION OUTPUT ;
    USE SIGNAL ;
    SHAPE ABUTMENT ;
    PORT
      LAYER met2 ;
      RECT 680.730 0.000 680.870 0.420 ;
    END
  END w0_wd_in[390]
  PIN w0_wd_in[391]
    DIRECTION OUTPUT ;
    USE SIGNAL ;
    SHAPE ABUTMENT ;
    PORT
      LAYER met2 ;
      RECT 685.790 0.000 685.930 0.420 ;
    END
  END w0_wd_in[391]
  PIN w0_wd_in[392]
    DIRECTION OUTPUT ;
    USE SIGNAL ;
    SHAPE ABUTMENT ;
    PORT
      LAYER met2 ;
      RECT 690.850 0.000 690.990 0.420 ;
    END
  END w0_wd_in[392]
  PIN w0_wd_in[393]
    DIRECTION OUTPUT ;
    USE SIGNAL ;
    SHAPE ABUTMENT ;
    PORT
      LAYER met2 ;
      RECT 695.910 0.000 696.050 0.420 ;
    END
  END w0_wd_in[393]
  PIN w0_wd_in[394]
    DIRECTION OUTPUT ;
    USE SIGNAL ;
    SHAPE ABUTMENT ;
    PORT
      LAYER met2 ;
      RECT 700.970 0.000 701.110 0.420 ;
    END
  END w0_wd_in[394]
  PIN w0_wd_in[395]
    DIRECTION OUTPUT ;
    USE SIGNAL ;
    SHAPE ABUTMENT ;
    PORT
      LAYER met2 ;
      RECT 706.030 0.000 706.170 0.420 ;
    END
  END w0_wd_in[395]
  PIN w0_wd_in[396]
    DIRECTION OUTPUT ;
    USE SIGNAL ;
    SHAPE ABUTMENT ;
    PORT
      LAYER met2 ;
      RECT 711.090 0.000 711.230 0.420 ;
    END
  END w0_wd_in[396]
  PIN w0_wd_in[397]
    DIRECTION OUTPUT ;
    USE SIGNAL ;
    SHAPE ABUTMENT ;
    PORT
      LAYER met2 ;
      RECT 716.150 0.000 716.290 0.420 ;
    END
  END w0_wd_in[397]
  PIN w0_wd_in[398]
    DIRECTION OUTPUT ;
    USE SIGNAL ;
    SHAPE ABUTMENT ;
    PORT
      LAYER met2 ;
      RECT 721.210 0.000 721.350 0.420 ;
    END
  END w0_wd_in[398]
  PIN w0_wd_in[399]
    DIRECTION OUTPUT ;
    USE SIGNAL ;
    SHAPE ABUTMENT ;
    PORT
      LAYER met2 ;
      RECT 726.270 0.000 726.410 0.420 ;
    END
  END w0_wd_in[399]
  PIN w0_wd_in[400]
    DIRECTION OUTPUT ;
    USE SIGNAL ;
    SHAPE ABUTMENT ;
    PORT
      LAYER met2 ;
      RECT 731.330 0.000 731.470 0.420 ;
    END
  END w0_wd_in[400]
  PIN w0_wd_in[401]
    DIRECTION OUTPUT ;
    USE SIGNAL ;
    SHAPE ABUTMENT ;
    PORT
      LAYER met2 ;
      RECT 736.390 0.000 736.530 0.420 ;
    END
  END w0_wd_in[401]
  PIN w0_wd_in[402]
    DIRECTION OUTPUT ;
    USE SIGNAL ;
    SHAPE ABUTMENT ;
    PORT
      LAYER met2 ;
      RECT 741.450 0.000 741.590 0.420 ;
    END
  END w0_wd_in[402]
  PIN w0_wd_in[403]
    DIRECTION OUTPUT ;
    USE SIGNAL ;
    SHAPE ABUTMENT ;
    PORT
      LAYER met2 ;
      RECT 746.510 0.000 746.650 0.420 ;
    END
  END w0_wd_in[403]
  PIN w0_wd_in[404]
    DIRECTION OUTPUT ;
    USE SIGNAL ;
    SHAPE ABUTMENT ;
    PORT
      LAYER met2 ;
      RECT 751.570 0.000 751.710 0.420 ;
    END
  END w0_wd_in[404]
  PIN w0_wd_in[405]
    DIRECTION OUTPUT ;
    USE SIGNAL ;
    SHAPE ABUTMENT ;
    PORT
      LAYER met2 ;
      RECT 756.630 0.000 756.770 0.420 ;
    END
  END w0_wd_in[405]
  PIN w0_wd_in[406]
    DIRECTION OUTPUT ;
    USE SIGNAL ;
    SHAPE ABUTMENT ;
    PORT
      LAYER met2 ;
      RECT 761.690 0.000 761.830 0.420 ;
    END
  END w0_wd_in[406]
  PIN w0_wd_in[407]
    DIRECTION OUTPUT ;
    USE SIGNAL ;
    SHAPE ABUTMENT ;
    PORT
      LAYER met2 ;
      RECT 766.750 0.000 766.890 0.420 ;
    END
  END w0_wd_in[407]
  PIN w0_wd_in[408]
    DIRECTION OUTPUT ;
    USE SIGNAL ;
    SHAPE ABUTMENT ;
    PORT
      LAYER met2 ;
      RECT 771.810 0.000 771.950 0.420 ;
    END
  END w0_wd_in[408]
  PIN w0_wd_in[409]
    DIRECTION OUTPUT ;
    USE SIGNAL ;
    SHAPE ABUTMENT ;
    PORT
      LAYER met2 ;
      RECT 776.870 0.000 777.010 0.420 ;
    END
  END w0_wd_in[409]
  PIN w0_wd_in[410]
    DIRECTION OUTPUT ;
    USE SIGNAL ;
    SHAPE ABUTMENT ;
    PORT
      LAYER met2 ;
      RECT 781.930 0.000 782.070 0.420 ;
    END
  END w0_wd_in[410]
  PIN w0_wd_in[411]
    DIRECTION OUTPUT ;
    USE SIGNAL ;
    SHAPE ABUTMENT ;
    PORT
      LAYER met2 ;
      RECT 786.990 0.000 787.130 0.420 ;
    END
  END w0_wd_in[411]
  PIN w0_wd_in[412]
    DIRECTION OUTPUT ;
    USE SIGNAL ;
    SHAPE ABUTMENT ;
    PORT
      LAYER met2 ;
      RECT 792.050 0.000 792.190 0.420 ;
    END
  END w0_wd_in[412]
  PIN w0_wd_in[413]
    DIRECTION OUTPUT ;
    USE SIGNAL ;
    SHAPE ABUTMENT ;
    PORT
      LAYER met2 ;
      RECT 797.110 0.000 797.250 0.420 ;
    END
  END w0_wd_in[413]
  PIN w0_wd_in[414]
    DIRECTION OUTPUT ;
    USE SIGNAL ;
    SHAPE ABUTMENT ;
    PORT
      LAYER met2 ;
      RECT 802.170 0.000 802.310 0.420 ;
    END
  END w0_wd_in[414]
  PIN w0_wd_in[415]
    DIRECTION OUTPUT ;
    USE SIGNAL ;
    SHAPE ABUTMENT ;
    PORT
      LAYER met2 ;
      RECT 807.230 0.000 807.370 0.420 ;
    END
  END w0_wd_in[415]
  PIN w0_wd_in[416]
    DIRECTION OUTPUT ;
    USE SIGNAL ;
    SHAPE ABUTMENT ;
    PORT
      LAYER met2 ;
      RECT 812.290 0.000 812.430 0.420 ;
    END
  END w0_wd_in[416]
  PIN w0_wd_in[417]
    DIRECTION OUTPUT ;
    USE SIGNAL ;
    SHAPE ABUTMENT ;
    PORT
      LAYER met2 ;
      RECT 817.350 0.000 817.490 0.420 ;
    END
  END w0_wd_in[417]
  PIN w0_wd_in[418]
    DIRECTION OUTPUT ;
    USE SIGNAL ;
    SHAPE ABUTMENT ;
    PORT
      LAYER met2 ;
      RECT 822.410 0.000 822.550 0.420 ;
    END
  END w0_wd_in[418]
  PIN w0_wd_in[419]
    DIRECTION OUTPUT ;
    USE SIGNAL ;
    SHAPE ABUTMENT ;
    PORT
      LAYER met2 ;
      RECT 827.470 0.000 827.610 0.420 ;
    END
  END w0_wd_in[419]
  PIN w0_wd_in[420]
    DIRECTION OUTPUT ;
    USE SIGNAL ;
    SHAPE ABUTMENT ;
    PORT
      LAYER met2 ;
      RECT 832.530 0.000 832.670 0.420 ;
    END
  END w0_wd_in[420]
  PIN w0_wd_in[421]
    DIRECTION OUTPUT ;
    USE SIGNAL ;
    SHAPE ABUTMENT ;
    PORT
      LAYER met2 ;
      RECT 837.590 0.000 837.730 0.420 ;
    END
  END w0_wd_in[421]
  PIN w0_wd_in[422]
    DIRECTION OUTPUT ;
    USE SIGNAL ;
    SHAPE ABUTMENT ;
    PORT
      LAYER met2 ;
      RECT 842.650 0.000 842.790 0.420 ;
    END
  END w0_wd_in[422]
  PIN w0_wd_in[423]
    DIRECTION OUTPUT ;
    USE SIGNAL ;
    SHAPE ABUTMENT ;
    PORT
      LAYER met2 ;
      RECT 847.710 0.000 847.850 0.420 ;
    END
  END w0_wd_in[423]
  PIN w0_wd_in[424]
    DIRECTION OUTPUT ;
    USE SIGNAL ;
    SHAPE ABUTMENT ;
    PORT
      LAYER met2 ;
      RECT 852.770 0.000 852.910 0.420 ;
    END
  END w0_wd_in[424]
  PIN w0_wd_in[425]
    DIRECTION OUTPUT ;
    USE SIGNAL ;
    SHAPE ABUTMENT ;
    PORT
      LAYER met2 ;
      RECT 857.830 0.000 857.970 0.420 ;
    END
  END w0_wd_in[425]
  PIN w0_wd_in[426]
    DIRECTION OUTPUT ;
    USE SIGNAL ;
    SHAPE ABUTMENT ;
    PORT
      LAYER met2 ;
      RECT 862.890 0.000 863.030 0.420 ;
    END
  END w0_wd_in[426]
  PIN w0_wd_in[427]
    DIRECTION OUTPUT ;
    USE SIGNAL ;
    SHAPE ABUTMENT ;
    PORT
      LAYER met2 ;
      RECT 867.950 0.000 868.090 0.420 ;
    END
  END w0_wd_in[427]
  PIN w0_wd_in[428]
    DIRECTION OUTPUT ;
    USE SIGNAL ;
    SHAPE ABUTMENT ;
    PORT
      LAYER met2 ;
      RECT 873.010 0.000 873.150 0.420 ;
    END
  END w0_wd_in[428]
  PIN w0_wd_in[429]
    DIRECTION OUTPUT ;
    USE SIGNAL ;
    SHAPE ABUTMENT ;
    PORT
      LAYER met2 ;
      RECT 878.070 0.000 878.210 0.420 ;
    END
  END w0_wd_in[429]
  PIN w0_wd_in[430]
    DIRECTION OUTPUT ;
    USE SIGNAL ;
    SHAPE ABUTMENT ;
    PORT
      LAYER met2 ;
      RECT 883.130 0.000 883.270 0.420 ;
    END
  END w0_wd_in[430]
  PIN w0_wd_in[431]
    DIRECTION OUTPUT ;
    USE SIGNAL ;
    SHAPE ABUTMENT ;
    PORT
      LAYER met2 ;
      RECT 888.190 0.000 888.330 0.420 ;
    END
  END w0_wd_in[431]
  PIN w0_wd_in[432]
    DIRECTION OUTPUT ;
    USE SIGNAL ;
    SHAPE ABUTMENT ;
    PORT
      LAYER met2 ;
      RECT 893.250 0.000 893.390 0.420 ;
    END
  END w0_wd_in[432]
  PIN w0_wd_in[433]
    DIRECTION OUTPUT ;
    USE SIGNAL ;
    SHAPE ABUTMENT ;
    PORT
      LAYER met2 ;
      RECT 898.310 0.000 898.450 0.420 ;
    END
  END w0_wd_in[433]
  PIN w0_wd_in[434]
    DIRECTION OUTPUT ;
    USE SIGNAL ;
    SHAPE ABUTMENT ;
    PORT
      LAYER met2 ;
      RECT 903.370 0.000 903.510 0.420 ;
    END
  END w0_wd_in[434]
  PIN w0_wd_in[435]
    DIRECTION OUTPUT ;
    USE SIGNAL ;
    SHAPE ABUTMENT ;
    PORT
      LAYER met2 ;
      RECT 908.430 0.000 908.570 0.420 ;
    END
  END w0_wd_in[435]
  PIN w0_wd_in[436]
    DIRECTION OUTPUT ;
    USE SIGNAL ;
    SHAPE ABUTMENT ;
    PORT
      LAYER met2 ;
      RECT 913.490 0.000 913.630 0.420 ;
    END
  END w0_wd_in[436]
  PIN w0_wd_in[437]
    DIRECTION OUTPUT ;
    USE SIGNAL ;
    SHAPE ABUTMENT ;
    PORT
      LAYER met2 ;
      RECT 918.550 0.000 918.690 0.420 ;
    END
  END w0_wd_in[437]
  PIN w0_wd_in[438]
    DIRECTION OUTPUT ;
    USE SIGNAL ;
    SHAPE ABUTMENT ;
    PORT
      LAYER met2 ;
      RECT 923.610 0.000 923.750 0.420 ;
    END
  END w0_wd_in[438]
  PIN w0_wd_in[439]
    DIRECTION OUTPUT ;
    USE SIGNAL ;
    SHAPE ABUTMENT ;
    PORT
      LAYER met2 ;
      RECT 928.670 0.000 928.810 0.420 ;
    END
  END w0_wd_in[439]
  PIN w0_wd_in[440]
    DIRECTION OUTPUT ;
    USE SIGNAL ;
    SHAPE ABUTMENT ;
    PORT
      LAYER met2 ;
      RECT 933.730 0.000 933.870 0.420 ;
    END
  END w0_wd_in[440]
  PIN w0_wd_in[441]
    DIRECTION OUTPUT ;
    USE SIGNAL ;
    SHAPE ABUTMENT ;
    PORT
      LAYER met2 ;
      RECT 938.790 0.000 938.930 0.420 ;
    END
  END w0_wd_in[441]
  PIN w0_wd_in[442]
    DIRECTION OUTPUT ;
    USE SIGNAL ;
    SHAPE ABUTMENT ;
    PORT
      LAYER met2 ;
      RECT 943.850 0.000 943.990 0.420 ;
    END
  END w0_wd_in[442]
  PIN w0_wd_in[443]
    DIRECTION OUTPUT ;
    USE SIGNAL ;
    SHAPE ABUTMENT ;
    PORT
      LAYER met2 ;
      RECT 948.910 0.000 949.050 0.420 ;
    END
  END w0_wd_in[443]
  PIN w0_wd_in[444]
    DIRECTION OUTPUT ;
    USE SIGNAL ;
    SHAPE ABUTMENT ;
    PORT
      LAYER met2 ;
      RECT 953.970 0.000 954.110 0.420 ;
    END
  END w0_wd_in[444]
  PIN w0_wd_in[445]
    DIRECTION OUTPUT ;
    USE SIGNAL ;
    SHAPE ABUTMENT ;
    PORT
      LAYER met2 ;
      RECT 959.030 0.000 959.170 0.420 ;
    END
  END w0_wd_in[445]
  PIN w0_wd_in[446]
    DIRECTION OUTPUT ;
    USE SIGNAL ;
    SHAPE ABUTMENT ;
    PORT
      LAYER met2 ;
      RECT 964.090 0.000 964.230 0.420 ;
    END
  END w0_wd_in[446]
  PIN w0_wd_in[447]
    DIRECTION OUTPUT ;
    USE SIGNAL ;
    SHAPE ABUTMENT ;
    PORT
      LAYER met2 ;
      RECT 969.150 0.000 969.290 0.420 ;
    END
  END w0_wd_in[447]
  PIN w0_wd_in[448]
    DIRECTION OUTPUT ;
    USE SIGNAL ;
    SHAPE ABUTMENT ;
    PORT
      LAYER met2 ;
      RECT 974.210 0.000 974.350 0.420 ;
    END
  END w0_wd_in[448]
  PIN w0_wd_in[449]
    DIRECTION OUTPUT ;
    USE SIGNAL ;
    SHAPE ABUTMENT ;
    PORT
      LAYER met2 ;
      RECT 979.270 0.000 979.410 0.420 ;
    END
  END w0_wd_in[449]
  PIN w0_wd_in[450]
    DIRECTION OUTPUT ;
    USE SIGNAL ;
    SHAPE ABUTMENT ;
    PORT
      LAYER met2 ;
      RECT 984.330 0.000 984.470 0.420 ;
    END
  END w0_wd_in[450]
  PIN w0_wd_in[451]
    DIRECTION OUTPUT ;
    USE SIGNAL ;
    SHAPE ABUTMENT ;
    PORT
      LAYER met2 ;
      RECT 989.390 0.000 989.530 0.420 ;
    END
  END w0_wd_in[451]
  PIN w0_wd_in[452]
    DIRECTION OUTPUT ;
    USE SIGNAL ;
    SHAPE ABUTMENT ;
    PORT
      LAYER met2 ;
      RECT 994.450 0.000 994.590 0.420 ;
    END
  END w0_wd_in[452]
  PIN w0_wd_in[453]
    DIRECTION OUTPUT ;
    USE SIGNAL ;
    SHAPE ABUTMENT ;
    PORT
      LAYER met2 ;
      RECT 999.510 0.000 999.650 0.420 ;
    END
  END w0_wd_in[453]
  PIN w0_wd_in[454]
    DIRECTION OUTPUT ;
    USE SIGNAL ;
    SHAPE ABUTMENT ;
    PORT
      LAYER met2 ;
      RECT 1004.570 0.000 1004.710 0.420 ;
    END
  END w0_wd_in[454]
  PIN w0_wd_in[455]
    DIRECTION OUTPUT ;
    USE SIGNAL ;
    SHAPE ABUTMENT ;
    PORT
      LAYER met2 ;
      RECT 1009.630 0.000 1009.770 0.420 ;
    END
  END w0_wd_in[455]
  PIN w0_wd_in[456]
    DIRECTION OUTPUT ;
    USE SIGNAL ;
    SHAPE ABUTMENT ;
    PORT
      LAYER met2 ;
      RECT 1014.690 0.000 1014.830 0.420 ;
    END
  END w0_wd_in[456]
  PIN w0_wd_in[457]
    DIRECTION OUTPUT ;
    USE SIGNAL ;
    SHAPE ABUTMENT ;
    PORT
      LAYER met2 ;
      RECT 1019.750 0.000 1019.890 0.420 ;
    END
  END w0_wd_in[457]
  PIN w0_wd_in[458]
    DIRECTION OUTPUT ;
    USE SIGNAL ;
    SHAPE ABUTMENT ;
    PORT
      LAYER met2 ;
      RECT 1024.810 0.000 1024.950 0.420 ;
    END
  END w0_wd_in[458]
  PIN w0_wd_in[459]
    DIRECTION OUTPUT ;
    USE SIGNAL ;
    SHAPE ABUTMENT ;
    PORT
      LAYER met2 ;
      RECT 1029.870 0.000 1030.010 0.420 ;
    END
  END w0_wd_in[459]
  PIN w0_wd_in[460]
    DIRECTION OUTPUT ;
    USE SIGNAL ;
    SHAPE ABUTMENT ;
    PORT
      LAYER met2 ;
      RECT 1034.930 0.000 1035.070 0.420 ;
    END
  END w0_wd_in[460]
  PIN w0_wd_in[461]
    DIRECTION OUTPUT ;
    USE SIGNAL ;
    SHAPE ABUTMENT ;
    PORT
      LAYER met2 ;
      RECT 1039.990 0.000 1040.130 0.420 ;
    END
  END w0_wd_in[461]
  PIN w0_wd_in[462]
    DIRECTION OUTPUT ;
    USE SIGNAL ;
    SHAPE ABUTMENT ;
    PORT
      LAYER met2 ;
      RECT 1045.050 0.000 1045.190 0.420 ;
    END
  END w0_wd_in[462]
  PIN w0_wd_in[463]
    DIRECTION OUTPUT ;
    USE SIGNAL ;
    SHAPE ABUTMENT ;
    PORT
      LAYER met2 ;
      RECT 1050.110 0.000 1050.250 0.420 ;
    END
  END w0_wd_in[463]
  PIN w0_wd_in[464]
    DIRECTION OUTPUT ;
    USE SIGNAL ;
    SHAPE ABUTMENT ;
    PORT
      LAYER met2 ;
      RECT 1055.170 0.000 1055.310 0.420 ;
    END
  END w0_wd_in[464]
  PIN w0_wd_in[465]
    DIRECTION OUTPUT ;
    USE SIGNAL ;
    SHAPE ABUTMENT ;
    PORT
      LAYER met2 ;
      RECT 1060.230 0.000 1060.370 0.420 ;
    END
  END w0_wd_in[465]
  PIN w0_wd_in[466]
    DIRECTION OUTPUT ;
    USE SIGNAL ;
    SHAPE ABUTMENT ;
    PORT
      LAYER met2 ;
      RECT 1065.290 0.000 1065.430 0.420 ;
    END
  END w0_wd_in[466]
  PIN w0_wd_in[467]
    DIRECTION OUTPUT ;
    USE SIGNAL ;
    SHAPE ABUTMENT ;
    PORT
      LAYER met2 ;
      RECT 1070.350 0.000 1070.490 0.420 ;
    END
  END w0_wd_in[467]
  PIN w0_wd_in[468]
    DIRECTION OUTPUT ;
    USE SIGNAL ;
    SHAPE ABUTMENT ;
    PORT
      LAYER met2 ;
      RECT 1075.410 0.000 1075.550 0.420 ;
    END
  END w0_wd_in[468]
  PIN w0_wd_in[469]
    DIRECTION OUTPUT ;
    USE SIGNAL ;
    SHAPE ABUTMENT ;
    PORT
      LAYER met2 ;
      RECT 1080.470 0.000 1080.610 0.420 ;
    END
  END w0_wd_in[469]
  PIN w0_wd_in[470]
    DIRECTION OUTPUT ;
    USE SIGNAL ;
    SHAPE ABUTMENT ;
    PORT
      LAYER met2 ;
      RECT 1085.530 0.000 1085.670 0.420 ;
    END
  END w0_wd_in[470]
  PIN w0_wd_in[471]
    DIRECTION OUTPUT ;
    USE SIGNAL ;
    SHAPE ABUTMENT ;
    PORT
      LAYER met2 ;
      RECT 1090.590 0.000 1090.730 0.420 ;
    END
  END w0_wd_in[471]
  PIN w0_wd_in[472]
    DIRECTION OUTPUT ;
    USE SIGNAL ;
    SHAPE ABUTMENT ;
    PORT
      LAYER met2 ;
      RECT 1095.650 0.000 1095.790 0.420 ;
    END
  END w0_wd_in[472]
  PIN w0_wd_in[473]
    DIRECTION OUTPUT ;
    USE SIGNAL ;
    SHAPE ABUTMENT ;
    PORT
      LAYER met2 ;
      RECT 1100.710 0.000 1100.850 0.420 ;
    END
  END w0_wd_in[473]
  PIN w0_wd_in[474]
    DIRECTION OUTPUT ;
    USE SIGNAL ;
    SHAPE ABUTMENT ;
    PORT
      LAYER met2 ;
      RECT 1105.770 0.000 1105.910 0.420 ;
    END
  END w0_wd_in[474]
  PIN w0_wd_in[475]
    DIRECTION OUTPUT ;
    USE SIGNAL ;
    SHAPE ABUTMENT ;
    PORT
      LAYER met2 ;
      RECT 1110.830 0.000 1110.970 0.420 ;
    END
  END w0_wd_in[475]
  PIN w0_wd_in[476]
    DIRECTION OUTPUT ;
    USE SIGNAL ;
    SHAPE ABUTMENT ;
    PORT
      LAYER met2 ;
      RECT 1115.890 0.000 1116.030 0.420 ;
    END
  END w0_wd_in[476]
  PIN w0_wd_in[477]
    DIRECTION OUTPUT ;
    USE SIGNAL ;
    SHAPE ABUTMENT ;
    PORT
      LAYER met2 ;
      RECT 1120.950 0.000 1121.090 0.420 ;
    END
  END w0_wd_in[477]
  PIN w0_wd_in[478]
    DIRECTION OUTPUT ;
    USE SIGNAL ;
    SHAPE ABUTMENT ;
    PORT
      LAYER met2 ;
      RECT 1126.010 0.000 1126.150 0.420 ;
    END
  END w0_wd_in[478]
  PIN w0_wd_in[479]
    DIRECTION OUTPUT ;
    USE SIGNAL ;
    SHAPE ABUTMENT ;
    PORT
      LAYER met2 ;
      RECT 1131.070 0.000 1131.210 0.420 ;
    END
  END w0_wd_in[479]
  PIN w0_wd_in[480]
    DIRECTION OUTPUT ;
    USE SIGNAL ;
    SHAPE ABUTMENT ;
    PORT
      LAYER met2 ;
      RECT 1136.130 0.000 1136.270 0.420 ;
    END
  END w0_wd_in[480]
  PIN w0_wd_in[481]
    DIRECTION OUTPUT ;
    USE SIGNAL ;
    SHAPE ABUTMENT ;
    PORT
      LAYER met2 ;
      RECT 1141.190 0.000 1141.330 0.420 ;
    END
  END w0_wd_in[481]
  PIN w0_wd_in[482]
    DIRECTION OUTPUT ;
    USE SIGNAL ;
    SHAPE ABUTMENT ;
    PORT
      LAYER met2 ;
      RECT 1146.250 0.000 1146.390 0.420 ;
    END
  END w0_wd_in[482]
  PIN w0_wd_in[483]
    DIRECTION OUTPUT ;
    USE SIGNAL ;
    SHAPE ABUTMENT ;
    PORT
      LAYER met2 ;
      RECT 1151.310 0.000 1151.450 0.420 ;
    END
  END w0_wd_in[483]
  PIN w0_wd_in[484]
    DIRECTION OUTPUT ;
    USE SIGNAL ;
    SHAPE ABUTMENT ;
    PORT
      LAYER met2 ;
      RECT 1156.370 0.000 1156.510 0.420 ;
    END
  END w0_wd_in[484]
  PIN w0_wd_in[485]
    DIRECTION OUTPUT ;
    USE SIGNAL ;
    SHAPE ABUTMENT ;
    PORT
      LAYER met2 ;
      RECT 1161.430 0.000 1161.570 0.420 ;
    END
  END w0_wd_in[485]
  PIN w0_wd_in[486]
    DIRECTION OUTPUT ;
    USE SIGNAL ;
    SHAPE ABUTMENT ;
    PORT
      LAYER met2 ;
      RECT 1166.490 0.000 1166.630 0.420 ;
    END
  END w0_wd_in[486]
  PIN w0_wd_in[487]
    DIRECTION OUTPUT ;
    USE SIGNAL ;
    SHAPE ABUTMENT ;
    PORT
      LAYER met2 ;
      RECT 1171.550 0.000 1171.690 0.420 ;
    END
  END w0_wd_in[487]
  PIN w0_wd_in[488]
    DIRECTION OUTPUT ;
    USE SIGNAL ;
    SHAPE ABUTMENT ;
    PORT
      LAYER met2 ;
      RECT 1176.610 0.000 1176.750 0.420 ;
    END
  END w0_wd_in[488]
  PIN w0_wd_in[489]
    DIRECTION OUTPUT ;
    USE SIGNAL ;
    SHAPE ABUTMENT ;
    PORT
      LAYER met2 ;
      RECT 1181.670 0.000 1181.810 0.420 ;
    END
  END w0_wd_in[489]
  PIN w0_wd_in[490]
    DIRECTION OUTPUT ;
    USE SIGNAL ;
    SHAPE ABUTMENT ;
    PORT
      LAYER met2 ;
      RECT 1186.730 0.000 1186.870 0.420 ;
    END
  END w0_wd_in[490]
  PIN w0_wd_in[491]
    DIRECTION OUTPUT ;
    USE SIGNAL ;
    SHAPE ABUTMENT ;
    PORT
      LAYER met2 ;
      RECT 1191.790 0.000 1191.930 0.420 ;
    END
  END w0_wd_in[491]
  PIN w0_wd_in[492]
    DIRECTION OUTPUT ;
    USE SIGNAL ;
    SHAPE ABUTMENT ;
    PORT
      LAYER met2 ;
      RECT 1196.850 0.000 1196.990 0.420 ;
    END
  END w0_wd_in[492]
  PIN w0_wd_in[493]
    DIRECTION OUTPUT ;
    USE SIGNAL ;
    SHAPE ABUTMENT ;
    PORT
      LAYER met2 ;
      RECT 1201.910 0.000 1202.050 0.420 ;
    END
  END w0_wd_in[493]
  PIN w0_wd_in[494]
    DIRECTION OUTPUT ;
    USE SIGNAL ;
    SHAPE ABUTMENT ;
    PORT
      LAYER met2 ;
      RECT 1206.970 0.000 1207.110 0.420 ;
    END
  END w0_wd_in[494]
  PIN w0_wd_in[495]
    DIRECTION OUTPUT ;
    USE SIGNAL ;
    SHAPE ABUTMENT ;
    PORT
      LAYER met2 ;
      RECT 1212.030 0.000 1212.170 0.420 ;
    END
  END w0_wd_in[495]
  PIN w0_wd_in[496]
    DIRECTION OUTPUT ;
    USE SIGNAL ;
    SHAPE ABUTMENT ;
    PORT
      LAYER met2 ;
      RECT 1217.090 0.000 1217.230 0.420 ;
    END
  END w0_wd_in[496]
  PIN w0_wd_in[497]
    DIRECTION OUTPUT ;
    USE SIGNAL ;
    SHAPE ABUTMENT ;
    PORT
      LAYER met2 ;
      RECT 1222.150 0.000 1222.290 0.420 ;
    END
  END w0_wd_in[497]
  PIN w0_wd_in[498]
    DIRECTION OUTPUT ;
    USE SIGNAL ;
    SHAPE ABUTMENT ;
    PORT
      LAYER met2 ;
      RECT 1227.210 0.000 1227.350 0.420 ;
    END
  END w0_wd_in[498]
  PIN w0_wd_in[499]
    DIRECTION OUTPUT ;
    USE SIGNAL ;
    SHAPE ABUTMENT ;
    PORT
      LAYER met2 ;
      RECT 1232.270 0.000 1232.410 0.420 ;
    END
  END w0_wd_in[499]
  PIN w0_wd_in[500]
    DIRECTION OUTPUT ;
    USE SIGNAL ;
    SHAPE ABUTMENT ;
    PORT
      LAYER met2 ;
      RECT 1237.330 0.000 1237.470 0.420 ;
    END
  END w0_wd_in[500]
  PIN w0_wd_in[501]
    DIRECTION OUTPUT ;
    USE SIGNAL ;
    SHAPE ABUTMENT ;
    PORT
      LAYER met2 ;
      RECT 1242.390 0.000 1242.530 0.420 ;
    END
  END w0_wd_in[501]
  PIN w0_wd_in[502]
    DIRECTION OUTPUT ;
    USE SIGNAL ;
    SHAPE ABUTMENT ;
    PORT
      LAYER met2 ;
      RECT 1247.450 0.000 1247.590 0.420 ;
    END
  END w0_wd_in[502]
  PIN w0_wd_in[503]
    DIRECTION OUTPUT ;
    USE SIGNAL ;
    SHAPE ABUTMENT ;
    PORT
      LAYER met2 ;
      RECT 1252.510 0.000 1252.650 0.420 ;
    END
  END w0_wd_in[503]
  PIN w0_wd_in[504]
    DIRECTION OUTPUT ;
    USE SIGNAL ;
    SHAPE ABUTMENT ;
    PORT
      LAYER met2 ;
      RECT 1257.570 0.000 1257.710 0.420 ;
    END
  END w0_wd_in[504]
  PIN w0_wd_in[505]
    DIRECTION OUTPUT ;
    USE SIGNAL ;
    SHAPE ABUTMENT ;
    PORT
      LAYER met2 ;
      RECT 1262.630 0.000 1262.770 0.420 ;
    END
  END w0_wd_in[505]
  PIN w0_wd_in[506]
    DIRECTION OUTPUT ;
    USE SIGNAL ;
    SHAPE ABUTMENT ;
    PORT
      LAYER met2 ;
      RECT 1267.690 0.000 1267.830 0.420 ;
    END
  END w0_wd_in[506]
  PIN w0_wd_in[507]
    DIRECTION OUTPUT ;
    USE SIGNAL ;
    SHAPE ABUTMENT ;
    PORT
      LAYER met2 ;
      RECT 1272.750 0.000 1272.890 0.420 ;
    END
  END w0_wd_in[507]
  PIN w0_wd_in[508]
    DIRECTION OUTPUT ;
    USE SIGNAL ;
    SHAPE ABUTMENT ;
    PORT
      LAYER met2 ;
      RECT 1277.810 0.000 1277.950 0.420 ;
    END
  END w0_wd_in[508]
  PIN w0_wd_in[509]
    DIRECTION OUTPUT ;
    USE SIGNAL ;
    SHAPE ABUTMENT ;
    PORT
      LAYER met2 ;
      RECT 1282.870 0.000 1283.010 0.420 ;
    END
  END w0_wd_in[509]
  PIN w0_wd_in[510]
    DIRECTION OUTPUT ;
    USE SIGNAL ;
    SHAPE ABUTMENT ;
    PORT
      LAYER met2 ;
      RECT 1287.930 0.000 1288.070 0.420 ;
    END
  END w0_wd_in[510]
  PIN w0_wd_in[511]
    DIRECTION OUTPUT ;
    USE SIGNAL ;
    SHAPE ABUTMENT ;
    PORT
      LAYER met2 ;
      RECT 1292.990 0.000 1293.130 0.420 ;
    END
  END w0_wd_in[511]
  PIN r0_rd_out[0]
    DIRECTION OUTPUT ;
    USE SIGNAL ;
    SHAPE ABUTMENT ;
    PORT
      LAYER met2 ;
      RECT 1298.050 0.000 1298.190 0.420 ;
    END
  END r0_rd_out[0]
  PIN r0_rd_out[1]
    DIRECTION OUTPUT ;
    USE SIGNAL ;
    SHAPE ABUTMENT ;
    PORT
      LAYER met2 ;
      RECT 1303.110 0.000 1303.250 0.420 ;
    END
  END r0_rd_out[1]
  PIN r0_rd_out[2]
    DIRECTION OUTPUT ;
    USE SIGNAL ;
    SHAPE ABUTMENT ;
    PORT
      LAYER met2 ;
      RECT 1308.170 0.000 1308.310 0.420 ;
    END
  END r0_rd_out[2]
  PIN r0_rd_out[3]
    DIRECTION OUTPUT ;
    USE SIGNAL ;
    SHAPE ABUTMENT ;
    PORT
      LAYER met2 ;
      RECT 1313.230 0.000 1313.370 0.420 ;
    END
  END r0_rd_out[3]
  PIN r0_rd_out[4]
    DIRECTION OUTPUT ;
    USE SIGNAL ;
    SHAPE ABUTMENT ;
    PORT
      LAYER met2 ;
      RECT 1318.290 0.000 1318.430 0.420 ;
    END
  END r0_rd_out[4]
  PIN r0_rd_out[5]
    DIRECTION OUTPUT ;
    USE SIGNAL ;
    SHAPE ABUTMENT ;
    PORT
      LAYER met2 ;
      RECT 1323.350 0.000 1323.490 0.420 ;
    END
  END r0_rd_out[5]
  PIN r0_rd_out[6]
    DIRECTION OUTPUT ;
    USE SIGNAL ;
    SHAPE ABUTMENT ;
    PORT
      LAYER met2 ;
      RECT 1328.410 0.000 1328.550 0.420 ;
    END
  END r0_rd_out[6]
  PIN r0_rd_out[7]
    DIRECTION OUTPUT ;
    USE SIGNAL ;
    SHAPE ABUTMENT ;
    PORT
      LAYER met2 ;
      RECT 1333.470 0.000 1333.610 0.420 ;
    END
  END r0_rd_out[7]
  PIN r0_rd_out[8]
    DIRECTION OUTPUT ;
    USE SIGNAL ;
    SHAPE ABUTMENT ;
    PORT
      LAYER met2 ;
      RECT 1338.530 0.000 1338.670 0.420 ;
    END
  END r0_rd_out[8]
  PIN r0_rd_out[9]
    DIRECTION OUTPUT ;
    USE SIGNAL ;
    SHAPE ABUTMENT ;
    PORT
      LAYER met2 ;
      RECT 1343.590 0.000 1343.730 0.420 ;
    END
  END r0_rd_out[9]
  PIN r0_rd_out[10]
    DIRECTION OUTPUT ;
    USE SIGNAL ;
    SHAPE ABUTMENT ;
    PORT
      LAYER met2 ;
      RECT 1348.650 0.000 1348.790 0.420 ;
    END
  END r0_rd_out[10]
  PIN r0_rd_out[11]
    DIRECTION OUTPUT ;
    USE SIGNAL ;
    SHAPE ABUTMENT ;
    PORT
      LAYER met2 ;
      RECT 1353.710 0.000 1353.850 0.420 ;
    END
  END r0_rd_out[11]
  PIN r0_rd_out[12]
    DIRECTION OUTPUT ;
    USE SIGNAL ;
    SHAPE ABUTMENT ;
    PORT
      LAYER met2 ;
      RECT 1358.770 0.000 1358.910 0.420 ;
    END
  END r0_rd_out[12]
  PIN r0_rd_out[13]
    DIRECTION OUTPUT ;
    USE SIGNAL ;
    SHAPE ABUTMENT ;
    PORT
      LAYER met2 ;
      RECT 1363.830 0.000 1363.970 0.420 ;
    END
  END r0_rd_out[13]
  PIN r0_rd_out[14]
    DIRECTION OUTPUT ;
    USE SIGNAL ;
    SHAPE ABUTMENT ;
    PORT
      LAYER met2 ;
      RECT 1368.890 0.000 1369.030 0.420 ;
    END
  END r0_rd_out[14]
  PIN r0_rd_out[15]
    DIRECTION OUTPUT ;
    USE SIGNAL ;
    SHAPE ABUTMENT ;
    PORT
      LAYER met2 ;
      RECT 1373.950 0.000 1374.090 0.420 ;
    END
  END r0_rd_out[15]
  PIN r0_rd_out[16]
    DIRECTION OUTPUT ;
    USE SIGNAL ;
    SHAPE ABUTMENT ;
    PORT
      LAYER met2 ;
      RECT 1379.010 0.000 1379.150 0.420 ;
    END
  END r0_rd_out[16]
  PIN r0_rd_out[17]
    DIRECTION OUTPUT ;
    USE SIGNAL ;
    SHAPE ABUTMENT ;
    PORT
      LAYER met2 ;
      RECT 1384.070 0.000 1384.210 0.420 ;
    END
  END r0_rd_out[17]
  PIN r0_rd_out[18]
    DIRECTION OUTPUT ;
    USE SIGNAL ;
    SHAPE ABUTMENT ;
    PORT
      LAYER met2 ;
      RECT 1389.130 0.000 1389.270 0.420 ;
    END
  END r0_rd_out[18]
  PIN r0_rd_out[19]
    DIRECTION OUTPUT ;
    USE SIGNAL ;
    SHAPE ABUTMENT ;
    PORT
      LAYER met2 ;
      RECT 1394.190 0.000 1394.330 0.420 ;
    END
  END r0_rd_out[19]
  PIN r0_rd_out[20]
    DIRECTION OUTPUT ;
    USE SIGNAL ;
    SHAPE ABUTMENT ;
    PORT
      LAYER met2 ;
      RECT 1399.250 0.000 1399.390 0.420 ;
    END
  END r0_rd_out[20]
  PIN r0_rd_out[21]
    DIRECTION OUTPUT ;
    USE SIGNAL ;
    SHAPE ABUTMENT ;
    PORT
      LAYER met2 ;
      RECT 1404.310 0.000 1404.450 0.420 ;
    END
  END r0_rd_out[21]
  PIN r0_rd_out[22]
    DIRECTION OUTPUT ;
    USE SIGNAL ;
    SHAPE ABUTMENT ;
    PORT
      LAYER met2 ;
      RECT 1409.370 0.000 1409.510 0.420 ;
    END
  END r0_rd_out[22]
  PIN r0_rd_out[23]
    DIRECTION OUTPUT ;
    USE SIGNAL ;
    SHAPE ABUTMENT ;
    PORT
      LAYER met2 ;
      RECT 1414.430 0.000 1414.570 0.420 ;
    END
  END r0_rd_out[23]
  PIN r0_rd_out[24]
    DIRECTION OUTPUT ;
    USE SIGNAL ;
    SHAPE ABUTMENT ;
    PORT
      LAYER met2 ;
      RECT 1419.490 0.000 1419.630 0.420 ;
    END
  END r0_rd_out[24]
  PIN r0_rd_out[25]
    DIRECTION OUTPUT ;
    USE SIGNAL ;
    SHAPE ABUTMENT ;
    PORT
      LAYER met2 ;
      RECT 1424.550 0.000 1424.690 0.420 ;
    END
  END r0_rd_out[25]
  PIN r0_rd_out[26]
    DIRECTION OUTPUT ;
    USE SIGNAL ;
    SHAPE ABUTMENT ;
    PORT
      LAYER met2 ;
      RECT 1429.610 0.000 1429.750 0.420 ;
    END
  END r0_rd_out[26]
  PIN r0_rd_out[27]
    DIRECTION OUTPUT ;
    USE SIGNAL ;
    SHAPE ABUTMENT ;
    PORT
      LAYER met2 ;
      RECT 1434.670 0.000 1434.810 0.420 ;
    END
  END r0_rd_out[27]
  PIN r0_rd_out[28]
    DIRECTION OUTPUT ;
    USE SIGNAL ;
    SHAPE ABUTMENT ;
    PORT
      LAYER met2 ;
      RECT 1439.730 0.000 1439.870 0.420 ;
    END
  END r0_rd_out[28]
  PIN r0_rd_out[29]
    DIRECTION OUTPUT ;
    USE SIGNAL ;
    SHAPE ABUTMENT ;
    PORT
      LAYER met2 ;
      RECT 1444.790 0.000 1444.930 0.420 ;
    END
  END r0_rd_out[29]
  PIN r0_rd_out[30]
    DIRECTION OUTPUT ;
    USE SIGNAL ;
    SHAPE ABUTMENT ;
    PORT
      LAYER met2 ;
      RECT 1449.850 0.000 1449.990 0.420 ;
    END
  END r0_rd_out[30]
  PIN r0_rd_out[31]
    DIRECTION OUTPUT ;
    USE SIGNAL ;
    SHAPE ABUTMENT ;
    PORT
      LAYER met2 ;
      RECT 1454.910 0.000 1455.050 0.420 ;
    END
  END r0_rd_out[31]
  PIN r0_rd_out[32]
    DIRECTION OUTPUT ;
    USE SIGNAL ;
    SHAPE ABUTMENT ;
    PORT
      LAYER met2 ;
      RECT 1459.970 0.000 1460.110 0.420 ;
    END
  END r0_rd_out[32]
  PIN r0_rd_out[33]
    DIRECTION OUTPUT ;
    USE SIGNAL ;
    SHAPE ABUTMENT ;
    PORT
      LAYER met2 ;
      RECT 1465.030 0.000 1465.170 0.420 ;
    END
  END r0_rd_out[33]
  PIN r0_rd_out[34]
    DIRECTION OUTPUT ;
    USE SIGNAL ;
    SHAPE ABUTMENT ;
    PORT
      LAYER met2 ;
      RECT 1470.090 0.000 1470.230 0.420 ;
    END
  END r0_rd_out[34]
  PIN r0_rd_out[35]
    DIRECTION OUTPUT ;
    USE SIGNAL ;
    SHAPE ABUTMENT ;
    PORT
      LAYER met2 ;
      RECT 1475.150 0.000 1475.290 0.420 ;
    END
  END r0_rd_out[35]
  PIN r0_rd_out[36]
    DIRECTION OUTPUT ;
    USE SIGNAL ;
    SHAPE ABUTMENT ;
    PORT
      LAYER met2 ;
      RECT 1480.210 0.000 1480.350 0.420 ;
    END
  END r0_rd_out[36]
  PIN r0_rd_out[37]
    DIRECTION OUTPUT ;
    USE SIGNAL ;
    SHAPE ABUTMENT ;
    PORT
      LAYER met2 ;
      RECT 1485.270 0.000 1485.410 0.420 ;
    END
  END r0_rd_out[37]
  PIN r0_rd_out[38]
    DIRECTION OUTPUT ;
    USE SIGNAL ;
    SHAPE ABUTMENT ;
    PORT
      LAYER met2 ;
      RECT 1490.330 0.000 1490.470 0.420 ;
    END
  END r0_rd_out[38]
  PIN r0_rd_out[39]
    DIRECTION OUTPUT ;
    USE SIGNAL ;
    SHAPE ABUTMENT ;
    PORT
      LAYER met2 ;
      RECT 1495.390 0.000 1495.530 0.420 ;
    END
  END r0_rd_out[39]
  PIN r0_rd_out[40]
    DIRECTION OUTPUT ;
    USE SIGNAL ;
    SHAPE ABUTMENT ;
    PORT
      LAYER met2 ;
      RECT 1500.450 0.000 1500.590 0.420 ;
    END
  END r0_rd_out[40]
  PIN r0_rd_out[41]
    DIRECTION OUTPUT ;
    USE SIGNAL ;
    SHAPE ABUTMENT ;
    PORT
      LAYER met2 ;
      RECT 1505.510 0.000 1505.650 0.420 ;
    END
  END r0_rd_out[41]
  PIN r0_rd_out[42]
    DIRECTION OUTPUT ;
    USE SIGNAL ;
    SHAPE ABUTMENT ;
    PORT
      LAYER met2 ;
      RECT 1510.570 0.000 1510.710 0.420 ;
    END
  END r0_rd_out[42]
  PIN r0_rd_out[43]
    DIRECTION OUTPUT ;
    USE SIGNAL ;
    SHAPE ABUTMENT ;
    PORT
      LAYER met2 ;
      RECT 1515.630 0.000 1515.770 0.420 ;
    END
  END r0_rd_out[43]
  PIN r0_rd_out[44]
    DIRECTION OUTPUT ;
    USE SIGNAL ;
    SHAPE ABUTMENT ;
    PORT
      LAYER met2 ;
      RECT 1520.690 0.000 1520.830 0.420 ;
    END
  END r0_rd_out[44]
  PIN r0_rd_out[45]
    DIRECTION OUTPUT ;
    USE SIGNAL ;
    SHAPE ABUTMENT ;
    PORT
      LAYER met2 ;
      RECT 1525.750 0.000 1525.890 0.420 ;
    END
  END r0_rd_out[45]
  PIN r0_rd_out[46]
    DIRECTION OUTPUT ;
    USE SIGNAL ;
    SHAPE ABUTMENT ;
    PORT
      LAYER met2 ;
      RECT 1530.810 0.000 1530.950 0.420 ;
    END
  END r0_rd_out[46]
  PIN r0_rd_out[47]
    DIRECTION OUTPUT ;
    USE SIGNAL ;
    SHAPE ABUTMENT ;
    PORT
      LAYER met2 ;
      RECT 1535.870 0.000 1536.010 0.420 ;
    END
  END r0_rd_out[47]
  PIN r0_rd_out[48]
    DIRECTION OUTPUT ;
    USE SIGNAL ;
    SHAPE ABUTMENT ;
    PORT
      LAYER met2 ;
      RECT 1540.930 0.000 1541.070 0.420 ;
    END
  END r0_rd_out[48]
  PIN r0_rd_out[49]
    DIRECTION OUTPUT ;
    USE SIGNAL ;
    SHAPE ABUTMENT ;
    PORT
      LAYER met2 ;
      RECT 1545.990 0.000 1546.130 0.420 ;
    END
  END r0_rd_out[49]
  PIN r0_rd_out[50]
    DIRECTION OUTPUT ;
    USE SIGNAL ;
    SHAPE ABUTMENT ;
    PORT
      LAYER met2 ;
      RECT 1551.050 0.000 1551.190 0.420 ;
    END
  END r0_rd_out[50]
  PIN r0_rd_out[51]
    DIRECTION OUTPUT ;
    USE SIGNAL ;
    SHAPE ABUTMENT ;
    PORT
      LAYER met2 ;
      RECT 1556.110 0.000 1556.250 0.420 ;
    END
  END r0_rd_out[51]
  PIN r0_rd_out[52]
    DIRECTION OUTPUT ;
    USE SIGNAL ;
    SHAPE ABUTMENT ;
    PORT
      LAYER met2 ;
      RECT 1561.170 0.000 1561.310 0.420 ;
    END
  END r0_rd_out[52]
  PIN r0_rd_out[53]
    DIRECTION OUTPUT ;
    USE SIGNAL ;
    SHAPE ABUTMENT ;
    PORT
      LAYER met2 ;
      RECT 1566.230 0.000 1566.370 0.420 ;
    END
  END r0_rd_out[53]
  PIN r0_rd_out[54]
    DIRECTION OUTPUT ;
    USE SIGNAL ;
    SHAPE ABUTMENT ;
    PORT
      LAYER met2 ;
      RECT 1571.290 0.000 1571.430 0.420 ;
    END
  END r0_rd_out[54]
  PIN r0_rd_out[55]
    DIRECTION OUTPUT ;
    USE SIGNAL ;
    SHAPE ABUTMENT ;
    PORT
      LAYER met2 ;
      RECT 1576.350 0.000 1576.490 0.420 ;
    END
  END r0_rd_out[55]
  PIN r0_rd_out[56]
    DIRECTION OUTPUT ;
    USE SIGNAL ;
    SHAPE ABUTMENT ;
    PORT
      LAYER met2 ;
      RECT 1581.410 0.000 1581.550 0.420 ;
    END
  END r0_rd_out[56]
  PIN r0_rd_out[57]
    DIRECTION OUTPUT ;
    USE SIGNAL ;
    SHAPE ABUTMENT ;
    PORT
      LAYER met2 ;
      RECT 1586.470 0.000 1586.610 0.420 ;
    END
  END r0_rd_out[57]
  PIN r0_rd_out[58]
    DIRECTION OUTPUT ;
    USE SIGNAL ;
    SHAPE ABUTMENT ;
    PORT
      LAYER met2 ;
      RECT 1591.530 0.000 1591.670 0.420 ;
    END
  END r0_rd_out[58]
  PIN r0_rd_out[59]
    DIRECTION OUTPUT ;
    USE SIGNAL ;
    SHAPE ABUTMENT ;
    PORT
      LAYER met2 ;
      RECT 1596.590 0.000 1596.730 0.420 ;
    END
  END r0_rd_out[59]
  PIN r0_rd_out[60]
    DIRECTION OUTPUT ;
    USE SIGNAL ;
    SHAPE ABUTMENT ;
    PORT
      LAYER met2 ;
      RECT 1601.650 0.000 1601.790 0.420 ;
    END
  END r0_rd_out[60]
  PIN r0_rd_out[61]
    DIRECTION OUTPUT ;
    USE SIGNAL ;
    SHAPE ABUTMENT ;
    PORT
      LAYER met2 ;
      RECT 1606.710 0.000 1606.850 0.420 ;
    END
  END r0_rd_out[61]
  PIN r0_rd_out[62]
    DIRECTION OUTPUT ;
    USE SIGNAL ;
    SHAPE ABUTMENT ;
    PORT
      LAYER met2 ;
      RECT 1611.770 0.000 1611.910 0.420 ;
    END
  END r0_rd_out[62]
  PIN r0_rd_out[63]
    DIRECTION OUTPUT ;
    USE SIGNAL ;
    SHAPE ABUTMENT ;
    PORT
      LAYER met2 ;
      RECT 1616.830 0.000 1616.970 0.420 ;
    END
  END r0_rd_out[63]
  PIN r0_rd_out[64]
    DIRECTION OUTPUT ;
    USE SIGNAL ;
    SHAPE ABUTMENT ;
    PORT
      LAYER met2 ;
      RECT 1621.890 0.000 1622.030 0.420 ;
    END
  END r0_rd_out[64]
  PIN r0_rd_out[65]
    DIRECTION OUTPUT ;
    USE SIGNAL ;
    SHAPE ABUTMENT ;
    PORT
      LAYER met2 ;
      RECT 1626.950 0.000 1627.090 0.420 ;
    END
  END r0_rd_out[65]
  PIN r0_rd_out[66]
    DIRECTION OUTPUT ;
    USE SIGNAL ;
    SHAPE ABUTMENT ;
    PORT
      LAYER met2 ;
      RECT 1632.010 0.000 1632.150 0.420 ;
    END
  END r0_rd_out[66]
  PIN r0_rd_out[67]
    DIRECTION OUTPUT ;
    USE SIGNAL ;
    SHAPE ABUTMENT ;
    PORT
      LAYER met2 ;
      RECT 1637.070 0.000 1637.210 0.420 ;
    END
  END r0_rd_out[67]
  PIN r0_rd_out[68]
    DIRECTION OUTPUT ;
    USE SIGNAL ;
    SHAPE ABUTMENT ;
    PORT
      LAYER met2 ;
      RECT 1642.130 0.000 1642.270 0.420 ;
    END
  END r0_rd_out[68]
  PIN r0_rd_out[69]
    DIRECTION OUTPUT ;
    USE SIGNAL ;
    SHAPE ABUTMENT ;
    PORT
      LAYER met2 ;
      RECT 1647.190 0.000 1647.330 0.420 ;
    END
  END r0_rd_out[69]
  PIN r0_rd_out[70]
    DIRECTION OUTPUT ;
    USE SIGNAL ;
    SHAPE ABUTMENT ;
    PORT
      LAYER met2 ;
      RECT 1652.250 0.000 1652.390 0.420 ;
    END
  END r0_rd_out[70]
  PIN r0_rd_out[71]
    DIRECTION OUTPUT ;
    USE SIGNAL ;
    SHAPE ABUTMENT ;
    PORT
      LAYER met2 ;
      RECT 1657.310 0.000 1657.450 0.420 ;
    END
  END r0_rd_out[71]
  PIN r0_rd_out[72]
    DIRECTION OUTPUT ;
    USE SIGNAL ;
    SHAPE ABUTMENT ;
    PORT
      LAYER met2 ;
      RECT 1662.370 0.000 1662.510 0.420 ;
    END
  END r0_rd_out[72]
  PIN r0_rd_out[73]
    DIRECTION OUTPUT ;
    USE SIGNAL ;
    SHAPE ABUTMENT ;
    PORT
      LAYER met2 ;
      RECT 1667.430 0.000 1667.570 0.420 ;
    END
  END r0_rd_out[73]
  PIN r0_rd_out[74]
    DIRECTION OUTPUT ;
    USE SIGNAL ;
    SHAPE ABUTMENT ;
    PORT
      LAYER met2 ;
      RECT 1672.490 0.000 1672.630 0.420 ;
    END
  END r0_rd_out[74]
  PIN r0_rd_out[75]
    DIRECTION OUTPUT ;
    USE SIGNAL ;
    SHAPE ABUTMENT ;
    PORT
      LAYER met2 ;
      RECT 1677.550 0.000 1677.690 0.420 ;
    END
  END r0_rd_out[75]
  PIN r0_rd_out[76]
    DIRECTION OUTPUT ;
    USE SIGNAL ;
    SHAPE ABUTMENT ;
    PORT
      LAYER met2 ;
      RECT 1682.610 0.000 1682.750 0.420 ;
    END
  END r0_rd_out[76]
  PIN r0_rd_out[77]
    DIRECTION OUTPUT ;
    USE SIGNAL ;
    SHAPE ABUTMENT ;
    PORT
      LAYER met2 ;
      RECT 1687.670 0.000 1687.810 0.420 ;
    END
  END r0_rd_out[77]
  PIN r0_rd_out[78]
    DIRECTION OUTPUT ;
    USE SIGNAL ;
    SHAPE ABUTMENT ;
    PORT
      LAYER met2 ;
      RECT 1692.730 0.000 1692.870 0.420 ;
    END
  END r0_rd_out[78]
  PIN r0_rd_out[79]
    DIRECTION OUTPUT ;
    USE SIGNAL ;
    SHAPE ABUTMENT ;
    PORT
      LAYER met2 ;
      RECT 1697.790 0.000 1697.930 0.420 ;
    END
  END r0_rd_out[79]
  PIN r0_rd_out[80]
    DIRECTION OUTPUT ;
    USE SIGNAL ;
    SHAPE ABUTMENT ;
    PORT
      LAYER met2 ;
      RECT 1702.850 0.000 1702.990 0.420 ;
    END
  END r0_rd_out[80]
  PIN r0_rd_out[81]
    DIRECTION OUTPUT ;
    USE SIGNAL ;
    SHAPE ABUTMENT ;
    PORT
      LAYER met2 ;
      RECT 1707.910 0.000 1708.050 0.420 ;
    END
  END r0_rd_out[81]
  PIN r0_rd_out[82]
    DIRECTION OUTPUT ;
    USE SIGNAL ;
    SHAPE ABUTMENT ;
    PORT
      LAYER met2 ;
      RECT 1712.970 0.000 1713.110 0.420 ;
    END
  END r0_rd_out[82]
  PIN r0_rd_out[83]
    DIRECTION OUTPUT ;
    USE SIGNAL ;
    SHAPE ABUTMENT ;
    PORT
      LAYER met2 ;
      RECT 1718.030 0.000 1718.170 0.420 ;
    END
  END r0_rd_out[83]
  PIN r0_rd_out[84]
    DIRECTION OUTPUT ;
    USE SIGNAL ;
    SHAPE ABUTMENT ;
    PORT
      LAYER met2 ;
      RECT 1723.090 0.000 1723.230 0.420 ;
    END
  END r0_rd_out[84]
  PIN r0_rd_out[85]
    DIRECTION OUTPUT ;
    USE SIGNAL ;
    SHAPE ABUTMENT ;
    PORT
      LAYER met2 ;
      RECT 1728.150 0.000 1728.290 0.420 ;
    END
  END r0_rd_out[85]
  PIN r0_rd_out[86]
    DIRECTION OUTPUT ;
    USE SIGNAL ;
    SHAPE ABUTMENT ;
    PORT
      LAYER met2 ;
      RECT 1733.210 0.000 1733.350 0.420 ;
    END
  END r0_rd_out[86]
  PIN r0_rd_out[87]
    DIRECTION OUTPUT ;
    USE SIGNAL ;
    SHAPE ABUTMENT ;
    PORT
      LAYER met2 ;
      RECT 1738.270 0.000 1738.410 0.420 ;
    END
  END r0_rd_out[87]
  PIN r0_rd_out[88]
    DIRECTION OUTPUT ;
    USE SIGNAL ;
    SHAPE ABUTMENT ;
    PORT
      LAYER met2 ;
      RECT 1743.330 0.000 1743.470 0.420 ;
    END
  END r0_rd_out[88]
  PIN r0_rd_out[89]
    DIRECTION OUTPUT ;
    USE SIGNAL ;
    SHAPE ABUTMENT ;
    PORT
      LAYER met2 ;
      RECT 1748.390 0.000 1748.530 0.420 ;
    END
  END r0_rd_out[89]
  PIN r0_rd_out[90]
    DIRECTION OUTPUT ;
    USE SIGNAL ;
    SHAPE ABUTMENT ;
    PORT
      LAYER met2 ;
      RECT 1753.450 0.000 1753.590 0.420 ;
    END
  END r0_rd_out[90]
  PIN r0_rd_out[91]
    DIRECTION OUTPUT ;
    USE SIGNAL ;
    SHAPE ABUTMENT ;
    PORT
      LAYER met2 ;
      RECT 1758.510 0.000 1758.650 0.420 ;
    END
  END r0_rd_out[91]
  PIN r0_rd_out[92]
    DIRECTION OUTPUT ;
    USE SIGNAL ;
    SHAPE ABUTMENT ;
    PORT
      LAYER met2 ;
      RECT 1763.570 0.000 1763.710 0.420 ;
    END
  END r0_rd_out[92]
  PIN r0_rd_out[93]
    DIRECTION OUTPUT ;
    USE SIGNAL ;
    SHAPE ABUTMENT ;
    PORT
      LAYER met2 ;
      RECT 1768.630 0.000 1768.770 0.420 ;
    END
  END r0_rd_out[93]
  PIN r0_rd_out[94]
    DIRECTION OUTPUT ;
    USE SIGNAL ;
    SHAPE ABUTMENT ;
    PORT
      LAYER met2 ;
      RECT 1773.690 0.000 1773.830 0.420 ;
    END
  END r0_rd_out[94]
  PIN r0_rd_out[95]
    DIRECTION OUTPUT ;
    USE SIGNAL ;
    SHAPE ABUTMENT ;
    PORT
      LAYER met2 ;
      RECT 1778.750 0.000 1778.890 0.420 ;
    END
  END r0_rd_out[95]
  PIN r0_rd_out[96]
    DIRECTION OUTPUT ;
    USE SIGNAL ;
    SHAPE ABUTMENT ;
    PORT
      LAYER met2 ;
      RECT 1783.810 0.000 1783.950 0.420 ;
    END
  END r0_rd_out[96]
  PIN r0_rd_out[97]
    DIRECTION OUTPUT ;
    USE SIGNAL ;
    SHAPE ABUTMENT ;
    PORT
      LAYER met2 ;
      RECT 1788.870 0.000 1789.010 0.420 ;
    END
  END r0_rd_out[97]
  PIN r0_rd_out[98]
    DIRECTION OUTPUT ;
    USE SIGNAL ;
    SHAPE ABUTMENT ;
    PORT
      LAYER met2 ;
      RECT 1793.930 0.000 1794.070 0.420 ;
    END
  END r0_rd_out[98]
  PIN r0_rd_out[99]
    DIRECTION OUTPUT ;
    USE SIGNAL ;
    SHAPE ABUTMENT ;
    PORT
      LAYER met2 ;
      RECT 1798.990 0.000 1799.130 0.420 ;
    END
  END r0_rd_out[99]
  PIN r0_rd_out[100]
    DIRECTION OUTPUT ;
    USE SIGNAL ;
    SHAPE ABUTMENT ;
    PORT
      LAYER met2 ;
      RECT 1804.050 0.000 1804.190 0.420 ;
    END
  END r0_rd_out[100]
  PIN r0_rd_out[101]
    DIRECTION OUTPUT ;
    USE SIGNAL ;
    SHAPE ABUTMENT ;
    PORT
      LAYER met2 ;
      RECT 1809.110 0.000 1809.250 0.420 ;
    END
  END r0_rd_out[101]
  PIN r0_rd_out[102]
    DIRECTION OUTPUT ;
    USE SIGNAL ;
    SHAPE ABUTMENT ;
    PORT
      LAYER met2 ;
      RECT 1814.170 0.000 1814.310 0.420 ;
    END
  END r0_rd_out[102]
  PIN r0_rd_out[103]
    DIRECTION OUTPUT ;
    USE SIGNAL ;
    SHAPE ABUTMENT ;
    PORT
      LAYER met2 ;
      RECT 1819.230 0.000 1819.370 0.420 ;
    END
  END r0_rd_out[103]
  PIN r0_rd_out[104]
    DIRECTION OUTPUT ;
    USE SIGNAL ;
    SHAPE ABUTMENT ;
    PORT
      LAYER met2 ;
      RECT 1824.290 0.000 1824.430 0.420 ;
    END
  END r0_rd_out[104]
  PIN r0_rd_out[105]
    DIRECTION OUTPUT ;
    USE SIGNAL ;
    SHAPE ABUTMENT ;
    PORT
      LAYER met2 ;
      RECT 1829.350 0.000 1829.490 0.420 ;
    END
  END r0_rd_out[105]
  PIN r0_rd_out[106]
    DIRECTION OUTPUT ;
    USE SIGNAL ;
    SHAPE ABUTMENT ;
    PORT
      LAYER met2 ;
      RECT 1834.410 0.000 1834.550 0.420 ;
    END
  END r0_rd_out[106]
  PIN r0_rd_out[107]
    DIRECTION OUTPUT ;
    USE SIGNAL ;
    SHAPE ABUTMENT ;
    PORT
      LAYER met2 ;
      RECT 1839.470 0.000 1839.610 0.420 ;
    END
  END r0_rd_out[107]
  PIN r0_rd_out[108]
    DIRECTION OUTPUT ;
    USE SIGNAL ;
    SHAPE ABUTMENT ;
    PORT
      LAYER met2 ;
      RECT 1844.530 0.000 1844.670 0.420 ;
    END
  END r0_rd_out[108]
  PIN r0_rd_out[109]
    DIRECTION OUTPUT ;
    USE SIGNAL ;
    SHAPE ABUTMENT ;
    PORT
      LAYER met2 ;
      RECT 1849.590 0.000 1849.730 0.420 ;
    END
  END r0_rd_out[109]
  PIN r0_rd_out[110]
    DIRECTION OUTPUT ;
    USE SIGNAL ;
    SHAPE ABUTMENT ;
    PORT
      LAYER met2 ;
      RECT 1854.650 0.000 1854.790 0.420 ;
    END
  END r0_rd_out[110]
  PIN r0_rd_out[111]
    DIRECTION OUTPUT ;
    USE SIGNAL ;
    SHAPE ABUTMENT ;
    PORT
      LAYER met2 ;
      RECT 1859.710 0.000 1859.850 0.420 ;
    END
  END r0_rd_out[111]
  PIN r0_rd_out[112]
    DIRECTION OUTPUT ;
    USE SIGNAL ;
    SHAPE ABUTMENT ;
    PORT
      LAYER met2 ;
      RECT 1864.770 0.000 1864.910 0.420 ;
    END
  END r0_rd_out[112]
  PIN r0_rd_out[113]
    DIRECTION OUTPUT ;
    USE SIGNAL ;
    SHAPE ABUTMENT ;
    PORT
      LAYER met2 ;
      RECT 1869.830 0.000 1869.970 0.420 ;
    END
  END r0_rd_out[113]
  PIN r0_rd_out[114]
    DIRECTION OUTPUT ;
    USE SIGNAL ;
    SHAPE ABUTMENT ;
    PORT
      LAYER met2 ;
      RECT 1874.890 0.000 1875.030 0.420 ;
    END
  END r0_rd_out[114]
  PIN r0_rd_out[115]
    DIRECTION OUTPUT ;
    USE SIGNAL ;
    SHAPE ABUTMENT ;
    PORT
      LAYER met2 ;
      RECT 1879.950 0.000 1880.090 0.420 ;
    END
  END r0_rd_out[115]
  PIN r0_rd_out[116]
    DIRECTION OUTPUT ;
    USE SIGNAL ;
    SHAPE ABUTMENT ;
    PORT
      LAYER met2 ;
      RECT 1885.010 0.000 1885.150 0.420 ;
    END
  END r0_rd_out[116]
  PIN r0_rd_out[117]
    DIRECTION OUTPUT ;
    USE SIGNAL ;
    SHAPE ABUTMENT ;
    PORT
      LAYER met2 ;
      RECT 1890.070 0.000 1890.210 0.420 ;
    END
  END r0_rd_out[117]
  PIN r0_rd_out[118]
    DIRECTION OUTPUT ;
    USE SIGNAL ;
    SHAPE ABUTMENT ;
    PORT
      LAYER met2 ;
      RECT 1895.130 0.000 1895.270 0.420 ;
    END
  END r0_rd_out[118]
  PIN r0_rd_out[119]
    DIRECTION OUTPUT ;
    USE SIGNAL ;
    SHAPE ABUTMENT ;
    PORT
      LAYER met2 ;
      RECT 1900.190 0.000 1900.330 0.420 ;
    END
  END r0_rd_out[119]
  PIN r0_rd_out[120]
    DIRECTION OUTPUT ;
    USE SIGNAL ;
    SHAPE ABUTMENT ;
    PORT
      LAYER met2 ;
      RECT 1905.250 0.000 1905.390 0.420 ;
    END
  END r0_rd_out[120]
  PIN r0_rd_out[121]
    DIRECTION OUTPUT ;
    USE SIGNAL ;
    SHAPE ABUTMENT ;
    PORT
      LAYER met2 ;
      RECT 1910.310 0.000 1910.450 0.420 ;
    END
  END r0_rd_out[121]
  PIN r0_rd_out[122]
    DIRECTION OUTPUT ;
    USE SIGNAL ;
    SHAPE ABUTMENT ;
    PORT
      LAYER met2 ;
      RECT 1915.370 0.000 1915.510 0.420 ;
    END
  END r0_rd_out[122]
  PIN r0_rd_out[123]
    DIRECTION OUTPUT ;
    USE SIGNAL ;
    SHAPE ABUTMENT ;
    PORT
      LAYER met2 ;
      RECT 1920.430 0.000 1920.570 0.420 ;
    END
  END r0_rd_out[123]
  PIN r0_rd_out[124]
    DIRECTION OUTPUT ;
    USE SIGNAL ;
    SHAPE ABUTMENT ;
    PORT
      LAYER met2 ;
      RECT 1925.490 0.000 1925.630 0.420 ;
    END
  END r0_rd_out[124]
  PIN r0_rd_out[125]
    DIRECTION OUTPUT ;
    USE SIGNAL ;
    SHAPE ABUTMENT ;
    PORT
      LAYER met2 ;
      RECT 1930.550 0.000 1930.690 0.420 ;
    END
  END r0_rd_out[125]
  PIN r0_rd_out[126]
    DIRECTION OUTPUT ;
    USE SIGNAL ;
    SHAPE ABUTMENT ;
    PORT
      LAYER met2 ;
      RECT 1935.610 0.000 1935.750 0.420 ;
    END
  END r0_rd_out[126]
  PIN r0_rd_out[127]
    DIRECTION OUTPUT ;
    USE SIGNAL ;
    SHAPE ABUTMENT ;
    PORT
      LAYER met2 ;
      RECT 1940.670 0.000 1940.810 0.420 ;
    END
  END r0_rd_out[127]
  PIN r0_rd_out[128]
    DIRECTION OUTPUT ;
    USE SIGNAL ;
    SHAPE ABUTMENT ;
    PORT
      LAYER met2 ;
      RECT 1945.730 0.000 1945.870 0.420 ;
    END
  END r0_rd_out[128]
  PIN r0_rd_out[129]
    DIRECTION OUTPUT ;
    USE SIGNAL ;
    SHAPE ABUTMENT ;
    PORT
      LAYER met2 ;
      RECT 1950.790 0.000 1950.930 0.420 ;
    END
  END r0_rd_out[129]
  PIN r0_rd_out[130]
    DIRECTION OUTPUT ;
    USE SIGNAL ;
    SHAPE ABUTMENT ;
    PORT
      LAYER met2 ;
      RECT 1955.850 0.000 1955.990 0.420 ;
    END
  END r0_rd_out[130]
  PIN r0_rd_out[131]
    DIRECTION OUTPUT ;
    USE SIGNAL ;
    SHAPE ABUTMENT ;
    PORT
      LAYER met2 ;
      RECT 1960.910 0.000 1961.050 0.420 ;
    END
  END r0_rd_out[131]
  PIN r0_rd_out[132]
    DIRECTION OUTPUT ;
    USE SIGNAL ;
    SHAPE ABUTMENT ;
    PORT
      LAYER met2 ;
      RECT 1965.970 0.000 1966.110 0.420 ;
    END
  END r0_rd_out[132]
  PIN r0_rd_out[133]
    DIRECTION OUTPUT ;
    USE SIGNAL ;
    SHAPE ABUTMENT ;
    PORT
      LAYER met2 ;
      RECT 1971.030 0.000 1971.170 0.420 ;
    END
  END r0_rd_out[133]
  PIN r0_rd_out[134]
    DIRECTION OUTPUT ;
    USE SIGNAL ;
    SHAPE ABUTMENT ;
    PORT
      LAYER met2 ;
      RECT 1976.090 0.000 1976.230 0.420 ;
    END
  END r0_rd_out[134]
  PIN r0_rd_out[135]
    DIRECTION OUTPUT ;
    USE SIGNAL ;
    SHAPE ABUTMENT ;
    PORT
      LAYER met2 ;
      RECT 1981.150 0.000 1981.290 0.420 ;
    END
  END r0_rd_out[135]
  PIN r0_rd_out[136]
    DIRECTION OUTPUT ;
    USE SIGNAL ;
    SHAPE ABUTMENT ;
    PORT
      LAYER met2 ;
      RECT 1986.210 0.000 1986.350 0.420 ;
    END
  END r0_rd_out[136]
  PIN r0_rd_out[137]
    DIRECTION OUTPUT ;
    USE SIGNAL ;
    SHAPE ABUTMENT ;
    PORT
      LAYER met2 ;
      RECT 1991.270 0.000 1991.410 0.420 ;
    END
  END r0_rd_out[137]
  PIN r0_rd_out[138]
    DIRECTION OUTPUT ;
    USE SIGNAL ;
    SHAPE ABUTMENT ;
    PORT
      LAYER met2 ;
      RECT 1996.330 0.000 1996.470 0.420 ;
    END
  END r0_rd_out[138]
  PIN r0_rd_out[139]
    DIRECTION OUTPUT ;
    USE SIGNAL ;
    SHAPE ABUTMENT ;
    PORT
      LAYER met2 ;
      RECT 2001.390 0.000 2001.530 0.420 ;
    END
  END r0_rd_out[139]
  PIN r0_rd_out[140]
    DIRECTION OUTPUT ;
    USE SIGNAL ;
    SHAPE ABUTMENT ;
    PORT
      LAYER met2 ;
      RECT 2006.450 0.000 2006.590 0.420 ;
    END
  END r0_rd_out[140]
  PIN r0_rd_out[141]
    DIRECTION OUTPUT ;
    USE SIGNAL ;
    SHAPE ABUTMENT ;
    PORT
      LAYER met2 ;
      RECT 2011.510 0.000 2011.650 0.420 ;
    END
  END r0_rd_out[141]
  PIN r0_rd_out[142]
    DIRECTION OUTPUT ;
    USE SIGNAL ;
    SHAPE ABUTMENT ;
    PORT
      LAYER met2 ;
      RECT 2016.570 0.000 2016.710 0.420 ;
    END
  END r0_rd_out[142]
  PIN r0_rd_out[143]
    DIRECTION OUTPUT ;
    USE SIGNAL ;
    SHAPE ABUTMENT ;
    PORT
      LAYER met2 ;
      RECT 2021.630 0.000 2021.770 0.420 ;
    END
  END r0_rd_out[143]
  PIN r0_rd_out[144]
    DIRECTION OUTPUT ;
    USE SIGNAL ;
    SHAPE ABUTMENT ;
    PORT
      LAYER met2 ;
      RECT 2026.690 0.000 2026.830 0.420 ;
    END
  END r0_rd_out[144]
  PIN r0_rd_out[145]
    DIRECTION OUTPUT ;
    USE SIGNAL ;
    SHAPE ABUTMENT ;
    PORT
      LAYER met2 ;
      RECT 2031.750 0.000 2031.890 0.420 ;
    END
  END r0_rd_out[145]
  PIN r0_rd_out[146]
    DIRECTION OUTPUT ;
    USE SIGNAL ;
    SHAPE ABUTMENT ;
    PORT
      LAYER met2 ;
      RECT 2036.810 0.000 2036.950 0.420 ;
    END
  END r0_rd_out[146]
  PIN r0_rd_out[147]
    DIRECTION OUTPUT ;
    USE SIGNAL ;
    SHAPE ABUTMENT ;
    PORT
      LAYER met2 ;
      RECT 2041.870 0.000 2042.010 0.420 ;
    END
  END r0_rd_out[147]
  PIN r0_rd_out[148]
    DIRECTION OUTPUT ;
    USE SIGNAL ;
    SHAPE ABUTMENT ;
    PORT
      LAYER met2 ;
      RECT 2046.930 0.000 2047.070 0.420 ;
    END
  END r0_rd_out[148]
  PIN r0_rd_out[149]
    DIRECTION OUTPUT ;
    USE SIGNAL ;
    SHAPE ABUTMENT ;
    PORT
      LAYER met2 ;
      RECT 2051.990 0.000 2052.130 0.420 ;
    END
  END r0_rd_out[149]
  PIN r0_rd_out[150]
    DIRECTION OUTPUT ;
    USE SIGNAL ;
    SHAPE ABUTMENT ;
    PORT
      LAYER met2 ;
      RECT 2057.050 0.000 2057.190 0.420 ;
    END
  END r0_rd_out[150]
  PIN r0_rd_out[151]
    DIRECTION OUTPUT ;
    USE SIGNAL ;
    SHAPE ABUTMENT ;
    PORT
      LAYER met2 ;
      RECT 2062.110 0.000 2062.250 0.420 ;
    END
  END r0_rd_out[151]
  PIN r0_rd_out[152]
    DIRECTION OUTPUT ;
    USE SIGNAL ;
    SHAPE ABUTMENT ;
    PORT
      LAYER met2 ;
      RECT 2067.170 0.000 2067.310 0.420 ;
    END
  END r0_rd_out[152]
  PIN r0_rd_out[153]
    DIRECTION OUTPUT ;
    USE SIGNAL ;
    SHAPE ABUTMENT ;
    PORT
      LAYER met2 ;
      RECT 2072.230 0.000 2072.370 0.420 ;
    END
  END r0_rd_out[153]
  PIN r0_rd_out[154]
    DIRECTION OUTPUT ;
    USE SIGNAL ;
    SHAPE ABUTMENT ;
    PORT
      LAYER met2 ;
      RECT 2077.290 0.000 2077.430 0.420 ;
    END
  END r0_rd_out[154]
  PIN r0_rd_out[155]
    DIRECTION OUTPUT ;
    USE SIGNAL ;
    SHAPE ABUTMENT ;
    PORT
      LAYER met2 ;
      RECT 2082.350 0.000 2082.490 0.420 ;
    END
  END r0_rd_out[155]
  PIN r0_rd_out[156]
    DIRECTION OUTPUT ;
    USE SIGNAL ;
    SHAPE ABUTMENT ;
    PORT
      LAYER met2 ;
      RECT 2087.410 0.000 2087.550 0.420 ;
    END
  END r0_rd_out[156]
  PIN r0_rd_out[157]
    DIRECTION OUTPUT ;
    USE SIGNAL ;
    SHAPE ABUTMENT ;
    PORT
      LAYER met2 ;
      RECT 2092.470 0.000 2092.610 0.420 ;
    END
  END r0_rd_out[157]
  PIN r0_rd_out[158]
    DIRECTION OUTPUT ;
    USE SIGNAL ;
    SHAPE ABUTMENT ;
    PORT
      LAYER met2 ;
      RECT 2097.530 0.000 2097.670 0.420 ;
    END
  END r0_rd_out[158]
  PIN r0_rd_out[159]
    DIRECTION OUTPUT ;
    USE SIGNAL ;
    SHAPE ABUTMENT ;
    PORT
      LAYER met2 ;
      RECT 2102.590 0.000 2102.730 0.420 ;
    END
  END r0_rd_out[159]
  PIN r0_rd_out[160]
    DIRECTION OUTPUT ;
    USE SIGNAL ;
    SHAPE ABUTMENT ;
    PORT
      LAYER met2 ;
      RECT 2107.650 0.000 2107.790 0.420 ;
    END
  END r0_rd_out[160]
  PIN r0_rd_out[161]
    DIRECTION OUTPUT ;
    USE SIGNAL ;
    SHAPE ABUTMENT ;
    PORT
      LAYER met2 ;
      RECT 2112.710 0.000 2112.850 0.420 ;
    END
  END r0_rd_out[161]
  PIN r0_rd_out[162]
    DIRECTION OUTPUT ;
    USE SIGNAL ;
    SHAPE ABUTMENT ;
    PORT
      LAYER met2 ;
      RECT 2117.770 0.000 2117.910 0.420 ;
    END
  END r0_rd_out[162]
  PIN r0_rd_out[163]
    DIRECTION OUTPUT ;
    USE SIGNAL ;
    SHAPE ABUTMENT ;
    PORT
      LAYER met2 ;
      RECT 2122.830 0.000 2122.970 0.420 ;
    END
  END r0_rd_out[163]
  PIN r0_rd_out[164]
    DIRECTION OUTPUT ;
    USE SIGNAL ;
    SHAPE ABUTMENT ;
    PORT
      LAYER met2 ;
      RECT 2127.890 0.000 2128.030 0.420 ;
    END
  END r0_rd_out[164]
  PIN r0_rd_out[165]
    DIRECTION OUTPUT ;
    USE SIGNAL ;
    SHAPE ABUTMENT ;
    PORT
      LAYER met2 ;
      RECT 2132.950 0.000 2133.090 0.420 ;
    END
  END r0_rd_out[165]
  PIN r0_rd_out[166]
    DIRECTION OUTPUT ;
    USE SIGNAL ;
    SHAPE ABUTMENT ;
    PORT
      LAYER met2 ;
      RECT 2138.010 0.000 2138.150 0.420 ;
    END
  END r0_rd_out[166]
  PIN r0_rd_out[167]
    DIRECTION OUTPUT ;
    USE SIGNAL ;
    SHAPE ABUTMENT ;
    PORT
      LAYER met2 ;
      RECT 2143.070 0.000 2143.210 0.420 ;
    END
  END r0_rd_out[167]
  PIN r0_rd_out[168]
    DIRECTION OUTPUT ;
    USE SIGNAL ;
    SHAPE ABUTMENT ;
    PORT
      LAYER met2 ;
      RECT 2148.130 0.000 2148.270 0.420 ;
    END
  END r0_rd_out[168]
  PIN r0_rd_out[169]
    DIRECTION OUTPUT ;
    USE SIGNAL ;
    SHAPE ABUTMENT ;
    PORT
      LAYER met2 ;
      RECT 2153.190 0.000 2153.330 0.420 ;
    END
  END r0_rd_out[169]
  PIN r0_rd_out[170]
    DIRECTION OUTPUT ;
    USE SIGNAL ;
    SHAPE ABUTMENT ;
    PORT
      LAYER met2 ;
      RECT 2158.250 0.000 2158.390 0.420 ;
    END
  END r0_rd_out[170]
  PIN r0_rd_out[171]
    DIRECTION OUTPUT ;
    USE SIGNAL ;
    SHAPE ABUTMENT ;
    PORT
      LAYER met2 ;
      RECT 2163.310 0.000 2163.450 0.420 ;
    END
  END r0_rd_out[171]
  PIN r0_rd_out[172]
    DIRECTION OUTPUT ;
    USE SIGNAL ;
    SHAPE ABUTMENT ;
    PORT
      LAYER met2 ;
      RECT 2168.370 0.000 2168.510 0.420 ;
    END
  END r0_rd_out[172]
  PIN r0_rd_out[173]
    DIRECTION OUTPUT ;
    USE SIGNAL ;
    SHAPE ABUTMENT ;
    PORT
      LAYER met2 ;
      RECT 2173.430 0.000 2173.570 0.420 ;
    END
  END r0_rd_out[173]
  PIN r0_rd_out[174]
    DIRECTION OUTPUT ;
    USE SIGNAL ;
    SHAPE ABUTMENT ;
    PORT
      LAYER met2 ;
      RECT 2178.490 0.000 2178.630 0.420 ;
    END
  END r0_rd_out[174]
  PIN r0_rd_out[175]
    DIRECTION OUTPUT ;
    USE SIGNAL ;
    SHAPE ABUTMENT ;
    PORT
      LAYER met2 ;
      RECT 2183.550 0.000 2183.690 0.420 ;
    END
  END r0_rd_out[175]
  PIN r0_rd_out[176]
    DIRECTION OUTPUT ;
    USE SIGNAL ;
    SHAPE ABUTMENT ;
    PORT
      LAYER met2 ;
      RECT 2188.610 0.000 2188.750 0.420 ;
    END
  END r0_rd_out[176]
  PIN r0_rd_out[177]
    DIRECTION OUTPUT ;
    USE SIGNAL ;
    SHAPE ABUTMENT ;
    PORT
      LAYER met2 ;
      RECT 2193.670 0.000 2193.810 0.420 ;
    END
  END r0_rd_out[177]
  PIN r0_rd_out[178]
    DIRECTION OUTPUT ;
    USE SIGNAL ;
    SHAPE ABUTMENT ;
    PORT
      LAYER met2 ;
      RECT 2198.730 0.000 2198.870 0.420 ;
    END
  END r0_rd_out[178]
  PIN r0_rd_out[179]
    DIRECTION OUTPUT ;
    USE SIGNAL ;
    SHAPE ABUTMENT ;
    PORT
      LAYER met2 ;
      RECT 2203.790 0.000 2203.930 0.420 ;
    END
  END r0_rd_out[179]
  PIN r0_rd_out[180]
    DIRECTION OUTPUT ;
    USE SIGNAL ;
    SHAPE ABUTMENT ;
    PORT
      LAYER met2 ;
      RECT 2208.850 0.000 2208.990 0.420 ;
    END
  END r0_rd_out[180]
  PIN r0_rd_out[181]
    DIRECTION OUTPUT ;
    USE SIGNAL ;
    SHAPE ABUTMENT ;
    PORT
      LAYER met2 ;
      RECT 2213.910 0.000 2214.050 0.420 ;
    END
  END r0_rd_out[181]
  PIN r0_rd_out[182]
    DIRECTION OUTPUT ;
    USE SIGNAL ;
    SHAPE ABUTMENT ;
    PORT
      LAYER met2 ;
      RECT 2218.970 0.000 2219.110 0.420 ;
    END
  END r0_rd_out[182]
  PIN r0_rd_out[183]
    DIRECTION OUTPUT ;
    USE SIGNAL ;
    SHAPE ABUTMENT ;
    PORT
      LAYER met2 ;
      RECT 2224.030 0.000 2224.170 0.420 ;
    END
  END r0_rd_out[183]
  PIN r0_rd_out[184]
    DIRECTION OUTPUT ;
    USE SIGNAL ;
    SHAPE ABUTMENT ;
    PORT
      LAYER met2 ;
      RECT 2229.090 0.000 2229.230 0.420 ;
    END
  END r0_rd_out[184]
  PIN r0_rd_out[185]
    DIRECTION OUTPUT ;
    USE SIGNAL ;
    SHAPE ABUTMENT ;
    PORT
      LAYER met2 ;
      RECT 2234.150 0.000 2234.290 0.420 ;
    END
  END r0_rd_out[185]
  PIN r0_rd_out[186]
    DIRECTION OUTPUT ;
    USE SIGNAL ;
    SHAPE ABUTMENT ;
    PORT
      LAYER met2 ;
      RECT 2239.210 0.000 2239.350 0.420 ;
    END
  END r0_rd_out[186]
  PIN r0_rd_out[187]
    DIRECTION OUTPUT ;
    USE SIGNAL ;
    SHAPE ABUTMENT ;
    PORT
      LAYER met2 ;
      RECT 2244.270 0.000 2244.410 0.420 ;
    END
  END r0_rd_out[187]
  PIN r0_rd_out[188]
    DIRECTION OUTPUT ;
    USE SIGNAL ;
    SHAPE ABUTMENT ;
    PORT
      LAYER met2 ;
      RECT 2249.330 0.000 2249.470 0.420 ;
    END
  END r0_rd_out[188]
  PIN r0_rd_out[189]
    DIRECTION OUTPUT ;
    USE SIGNAL ;
    SHAPE ABUTMENT ;
    PORT
      LAYER met2 ;
      RECT 2254.390 0.000 2254.530 0.420 ;
    END
  END r0_rd_out[189]
  PIN r0_rd_out[190]
    DIRECTION OUTPUT ;
    USE SIGNAL ;
    SHAPE ABUTMENT ;
    PORT
      LAYER met2 ;
      RECT 2259.450 0.000 2259.590 0.420 ;
    END
  END r0_rd_out[190]
  PIN r0_rd_out[191]
    DIRECTION OUTPUT ;
    USE SIGNAL ;
    SHAPE ABUTMENT ;
    PORT
      LAYER met2 ;
      RECT 2264.510 0.000 2264.650 0.420 ;
    END
  END r0_rd_out[191]
  PIN r0_rd_out[192]
    DIRECTION OUTPUT ;
    USE SIGNAL ;
    SHAPE ABUTMENT ;
    PORT
      LAYER met2 ;
      RECT 2269.570 0.000 2269.710 0.420 ;
    END
  END r0_rd_out[192]
  PIN r0_rd_out[193]
    DIRECTION OUTPUT ;
    USE SIGNAL ;
    SHAPE ABUTMENT ;
    PORT
      LAYER met2 ;
      RECT 2274.630 0.000 2274.770 0.420 ;
    END
  END r0_rd_out[193]
  PIN r0_rd_out[194]
    DIRECTION OUTPUT ;
    USE SIGNAL ;
    SHAPE ABUTMENT ;
    PORT
      LAYER met2 ;
      RECT 2279.690 0.000 2279.830 0.420 ;
    END
  END r0_rd_out[194]
  PIN r0_rd_out[195]
    DIRECTION OUTPUT ;
    USE SIGNAL ;
    SHAPE ABUTMENT ;
    PORT
      LAYER met2 ;
      RECT 2284.750 0.000 2284.890 0.420 ;
    END
  END r0_rd_out[195]
  PIN r0_rd_out[196]
    DIRECTION OUTPUT ;
    USE SIGNAL ;
    SHAPE ABUTMENT ;
    PORT
      LAYER met2 ;
      RECT 2289.810 0.000 2289.950 0.420 ;
    END
  END r0_rd_out[196]
  PIN r0_rd_out[197]
    DIRECTION OUTPUT ;
    USE SIGNAL ;
    SHAPE ABUTMENT ;
    PORT
      LAYER met2 ;
      RECT 2294.870 0.000 2295.010 0.420 ;
    END
  END r0_rd_out[197]
  PIN r0_rd_out[198]
    DIRECTION OUTPUT ;
    USE SIGNAL ;
    SHAPE ABUTMENT ;
    PORT
      LAYER met2 ;
      RECT 2299.930 0.000 2300.070 0.420 ;
    END
  END r0_rd_out[198]
  PIN r0_rd_out[199]
    DIRECTION OUTPUT ;
    USE SIGNAL ;
    SHAPE ABUTMENT ;
    PORT
      LAYER met2 ;
      RECT 2304.990 0.000 2305.130 0.420 ;
    END
  END r0_rd_out[199]
  PIN r0_rd_out[200]
    DIRECTION OUTPUT ;
    USE SIGNAL ;
    SHAPE ABUTMENT ;
    PORT
      LAYER met2 ;
      RECT 2310.050 0.000 2310.190 0.420 ;
    END
  END r0_rd_out[200]
  PIN r0_rd_out[201]
    DIRECTION OUTPUT ;
    USE SIGNAL ;
    SHAPE ABUTMENT ;
    PORT
      LAYER met2 ;
      RECT 2315.110 0.000 2315.250 0.420 ;
    END
  END r0_rd_out[201]
  PIN r0_rd_out[202]
    DIRECTION OUTPUT ;
    USE SIGNAL ;
    SHAPE ABUTMENT ;
    PORT
      LAYER met2 ;
      RECT 2320.170 0.000 2320.310 0.420 ;
    END
  END r0_rd_out[202]
  PIN r0_rd_out[203]
    DIRECTION OUTPUT ;
    USE SIGNAL ;
    SHAPE ABUTMENT ;
    PORT
      LAYER met2 ;
      RECT 2325.230 0.000 2325.370 0.420 ;
    END
  END r0_rd_out[203]
  PIN r0_rd_out[204]
    DIRECTION OUTPUT ;
    USE SIGNAL ;
    SHAPE ABUTMENT ;
    PORT
      LAYER met2 ;
      RECT 2330.290 0.000 2330.430 0.420 ;
    END
  END r0_rd_out[204]
  PIN r0_rd_out[205]
    DIRECTION OUTPUT ;
    USE SIGNAL ;
    SHAPE ABUTMENT ;
    PORT
      LAYER met2 ;
      RECT 2335.350 0.000 2335.490 0.420 ;
    END
  END r0_rd_out[205]
  PIN r0_rd_out[206]
    DIRECTION OUTPUT ;
    USE SIGNAL ;
    SHAPE ABUTMENT ;
    PORT
      LAYER met2 ;
      RECT 2340.410 0.000 2340.550 0.420 ;
    END
  END r0_rd_out[206]
  PIN r0_rd_out[207]
    DIRECTION OUTPUT ;
    USE SIGNAL ;
    SHAPE ABUTMENT ;
    PORT
      LAYER met2 ;
      RECT 2345.470 0.000 2345.610 0.420 ;
    END
  END r0_rd_out[207]
  PIN r0_rd_out[208]
    DIRECTION OUTPUT ;
    USE SIGNAL ;
    SHAPE ABUTMENT ;
    PORT
      LAYER met2 ;
      RECT 2350.530 0.000 2350.670 0.420 ;
    END
  END r0_rd_out[208]
  PIN r0_rd_out[209]
    DIRECTION OUTPUT ;
    USE SIGNAL ;
    SHAPE ABUTMENT ;
    PORT
      LAYER met2 ;
      RECT 2355.590 0.000 2355.730 0.420 ;
    END
  END r0_rd_out[209]
  PIN r0_rd_out[210]
    DIRECTION OUTPUT ;
    USE SIGNAL ;
    SHAPE ABUTMENT ;
    PORT
      LAYER met2 ;
      RECT 2360.650 0.000 2360.790 0.420 ;
    END
  END r0_rd_out[210]
  PIN r0_rd_out[211]
    DIRECTION OUTPUT ;
    USE SIGNAL ;
    SHAPE ABUTMENT ;
    PORT
      LAYER met2 ;
      RECT 2365.710 0.000 2365.850 0.420 ;
    END
  END r0_rd_out[211]
  PIN r0_rd_out[212]
    DIRECTION OUTPUT ;
    USE SIGNAL ;
    SHAPE ABUTMENT ;
    PORT
      LAYER met2 ;
      RECT 2370.770 0.000 2370.910 0.420 ;
    END
  END r0_rd_out[212]
  PIN r0_rd_out[213]
    DIRECTION OUTPUT ;
    USE SIGNAL ;
    SHAPE ABUTMENT ;
    PORT
      LAYER met2 ;
      RECT 2375.830 0.000 2375.970 0.420 ;
    END
  END r0_rd_out[213]
  PIN r0_rd_out[214]
    DIRECTION OUTPUT ;
    USE SIGNAL ;
    SHAPE ABUTMENT ;
    PORT
      LAYER met2 ;
      RECT 2380.890 0.000 2381.030 0.420 ;
    END
  END r0_rd_out[214]
  PIN r0_rd_out[215]
    DIRECTION OUTPUT ;
    USE SIGNAL ;
    SHAPE ABUTMENT ;
    PORT
      LAYER met2 ;
      RECT 2385.950 0.000 2386.090 0.420 ;
    END
  END r0_rd_out[215]
  PIN r0_rd_out[216]
    DIRECTION OUTPUT ;
    USE SIGNAL ;
    SHAPE ABUTMENT ;
    PORT
      LAYER met2 ;
      RECT 2391.010 0.000 2391.150 0.420 ;
    END
  END r0_rd_out[216]
  PIN r0_rd_out[217]
    DIRECTION OUTPUT ;
    USE SIGNAL ;
    SHAPE ABUTMENT ;
    PORT
      LAYER met2 ;
      RECT 2396.070 0.000 2396.210 0.420 ;
    END
  END r0_rd_out[217]
  PIN r0_rd_out[218]
    DIRECTION OUTPUT ;
    USE SIGNAL ;
    SHAPE ABUTMENT ;
    PORT
      LAYER met2 ;
      RECT 2401.130 0.000 2401.270 0.420 ;
    END
  END r0_rd_out[218]
  PIN r0_rd_out[219]
    DIRECTION OUTPUT ;
    USE SIGNAL ;
    SHAPE ABUTMENT ;
    PORT
      LAYER met2 ;
      RECT 2406.190 0.000 2406.330 0.420 ;
    END
  END r0_rd_out[219]
  PIN r0_rd_out[220]
    DIRECTION OUTPUT ;
    USE SIGNAL ;
    SHAPE ABUTMENT ;
    PORT
      LAYER met2 ;
      RECT 2411.250 0.000 2411.390 0.420 ;
    END
  END r0_rd_out[220]
  PIN r0_rd_out[221]
    DIRECTION OUTPUT ;
    USE SIGNAL ;
    SHAPE ABUTMENT ;
    PORT
      LAYER met2 ;
      RECT 2416.310 0.000 2416.450 0.420 ;
    END
  END r0_rd_out[221]
  PIN r0_rd_out[222]
    DIRECTION OUTPUT ;
    USE SIGNAL ;
    SHAPE ABUTMENT ;
    PORT
      LAYER met2 ;
      RECT 2421.370 0.000 2421.510 0.420 ;
    END
  END r0_rd_out[222]
  PIN r0_rd_out[223]
    DIRECTION OUTPUT ;
    USE SIGNAL ;
    SHAPE ABUTMENT ;
    PORT
      LAYER met2 ;
      RECT 2426.430 0.000 2426.570 0.420 ;
    END
  END r0_rd_out[223]
  PIN r0_rd_out[224]
    DIRECTION OUTPUT ;
    USE SIGNAL ;
    SHAPE ABUTMENT ;
    PORT
      LAYER met2 ;
      RECT 2431.490 0.000 2431.630 0.420 ;
    END
  END r0_rd_out[224]
  PIN r0_rd_out[225]
    DIRECTION OUTPUT ;
    USE SIGNAL ;
    SHAPE ABUTMENT ;
    PORT
      LAYER met2 ;
      RECT 2436.550 0.000 2436.690 0.420 ;
    END
  END r0_rd_out[225]
  PIN r0_rd_out[226]
    DIRECTION OUTPUT ;
    USE SIGNAL ;
    SHAPE ABUTMENT ;
    PORT
      LAYER met2 ;
      RECT 2441.610 0.000 2441.750 0.420 ;
    END
  END r0_rd_out[226]
  PIN r0_rd_out[227]
    DIRECTION OUTPUT ;
    USE SIGNAL ;
    SHAPE ABUTMENT ;
    PORT
      LAYER met2 ;
      RECT 2446.670 0.000 2446.810 0.420 ;
    END
  END r0_rd_out[227]
  PIN r0_rd_out[228]
    DIRECTION OUTPUT ;
    USE SIGNAL ;
    SHAPE ABUTMENT ;
    PORT
      LAYER met2 ;
      RECT 2451.730 0.000 2451.870 0.420 ;
    END
  END r0_rd_out[228]
  PIN r0_rd_out[229]
    DIRECTION OUTPUT ;
    USE SIGNAL ;
    SHAPE ABUTMENT ;
    PORT
      LAYER met2 ;
      RECT 2456.790 0.000 2456.930 0.420 ;
    END
  END r0_rd_out[229]
  PIN r0_rd_out[230]
    DIRECTION OUTPUT ;
    USE SIGNAL ;
    SHAPE ABUTMENT ;
    PORT
      LAYER met2 ;
      RECT 2461.850 0.000 2461.990 0.420 ;
    END
  END r0_rd_out[230]
  PIN r0_rd_out[231]
    DIRECTION OUTPUT ;
    USE SIGNAL ;
    SHAPE ABUTMENT ;
    PORT
      LAYER met2 ;
      RECT 2466.910 0.000 2467.050 0.420 ;
    END
  END r0_rd_out[231]
  PIN r0_rd_out[232]
    DIRECTION OUTPUT ;
    USE SIGNAL ;
    SHAPE ABUTMENT ;
    PORT
      LAYER met2 ;
      RECT 2471.970 0.000 2472.110 0.420 ;
    END
  END r0_rd_out[232]
  PIN r0_rd_out[233]
    DIRECTION OUTPUT ;
    USE SIGNAL ;
    SHAPE ABUTMENT ;
    PORT
      LAYER met2 ;
      RECT 2477.030 0.000 2477.170 0.420 ;
    END
  END r0_rd_out[233]
  PIN r0_rd_out[234]
    DIRECTION OUTPUT ;
    USE SIGNAL ;
    SHAPE ABUTMENT ;
    PORT
      LAYER met2 ;
      RECT 2482.090 0.000 2482.230 0.420 ;
    END
  END r0_rd_out[234]
  PIN r0_rd_out[235]
    DIRECTION OUTPUT ;
    USE SIGNAL ;
    SHAPE ABUTMENT ;
    PORT
      LAYER met2 ;
      RECT 2487.150 0.000 2487.290 0.420 ;
    END
  END r0_rd_out[235]
  PIN r0_rd_out[236]
    DIRECTION OUTPUT ;
    USE SIGNAL ;
    SHAPE ABUTMENT ;
    PORT
      LAYER met2 ;
      RECT 2492.210 0.000 2492.350 0.420 ;
    END
  END r0_rd_out[236]
  PIN r0_rd_out[237]
    DIRECTION OUTPUT ;
    USE SIGNAL ;
    SHAPE ABUTMENT ;
    PORT
      LAYER met2 ;
      RECT 2497.270 0.000 2497.410 0.420 ;
    END
  END r0_rd_out[237]
  PIN r0_rd_out[238]
    DIRECTION OUTPUT ;
    USE SIGNAL ;
    SHAPE ABUTMENT ;
    PORT
      LAYER met2 ;
      RECT 2502.330 0.000 2502.470 0.420 ;
    END
  END r0_rd_out[238]
  PIN r0_rd_out[239]
    DIRECTION OUTPUT ;
    USE SIGNAL ;
    SHAPE ABUTMENT ;
    PORT
      LAYER met2 ;
      RECT 2507.390 0.000 2507.530 0.420 ;
    END
  END r0_rd_out[239]
  PIN r0_rd_out[240]
    DIRECTION OUTPUT ;
    USE SIGNAL ;
    SHAPE ABUTMENT ;
    PORT
      LAYER met2 ;
      RECT 2512.450 0.000 2512.590 0.420 ;
    END
  END r0_rd_out[240]
  PIN r0_rd_out[241]
    DIRECTION OUTPUT ;
    USE SIGNAL ;
    SHAPE ABUTMENT ;
    PORT
      LAYER met2 ;
      RECT 2517.510 0.000 2517.650 0.420 ;
    END
  END r0_rd_out[241]
  PIN r0_rd_out[242]
    DIRECTION OUTPUT ;
    USE SIGNAL ;
    SHAPE ABUTMENT ;
    PORT
      LAYER met2 ;
      RECT 2522.570 0.000 2522.710 0.420 ;
    END
  END r0_rd_out[242]
  PIN r0_rd_out[243]
    DIRECTION OUTPUT ;
    USE SIGNAL ;
    SHAPE ABUTMENT ;
    PORT
      LAYER met2 ;
      RECT 2527.630 0.000 2527.770 0.420 ;
    END
  END r0_rd_out[243]
  PIN r0_rd_out[244]
    DIRECTION OUTPUT ;
    USE SIGNAL ;
    SHAPE ABUTMENT ;
    PORT
      LAYER met2 ;
      RECT 2532.690 0.000 2532.830 0.420 ;
    END
  END r0_rd_out[244]
  PIN r0_rd_out[245]
    DIRECTION OUTPUT ;
    USE SIGNAL ;
    SHAPE ABUTMENT ;
    PORT
      LAYER met2 ;
      RECT 2537.750 0.000 2537.890 0.420 ;
    END
  END r0_rd_out[245]
  PIN r0_rd_out[246]
    DIRECTION OUTPUT ;
    USE SIGNAL ;
    SHAPE ABUTMENT ;
    PORT
      LAYER met2 ;
      RECT 2542.810 0.000 2542.950 0.420 ;
    END
  END r0_rd_out[246]
  PIN r0_rd_out[247]
    DIRECTION OUTPUT ;
    USE SIGNAL ;
    SHAPE ABUTMENT ;
    PORT
      LAYER met2 ;
      RECT 2547.870 0.000 2548.010 0.420 ;
    END
  END r0_rd_out[247]
  PIN r0_rd_out[248]
    DIRECTION OUTPUT ;
    USE SIGNAL ;
    SHAPE ABUTMENT ;
    PORT
      LAYER met2 ;
      RECT 2552.930 0.000 2553.070 0.420 ;
    END
  END r0_rd_out[248]
  PIN r0_rd_out[249]
    DIRECTION OUTPUT ;
    USE SIGNAL ;
    SHAPE ABUTMENT ;
    PORT
      LAYER met2 ;
      RECT 2557.990 0.000 2558.130 0.420 ;
    END
  END r0_rd_out[249]
  PIN r0_rd_out[250]
    DIRECTION OUTPUT ;
    USE SIGNAL ;
    SHAPE ABUTMENT ;
    PORT
      LAYER met2 ;
      RECT 2563.050 0.000 2563.190 0.420 ;
    END
  END r0_rd_out[250]
  PIN r0_rd_out[251]
    DIRECTION OUTPUT ;
    USE SIGNAL ;
    SHAPE ABUTMENT ;
    PORT
      LAYER met2 ;
      RECT 2568.110 0.000 2568.250 0.420 ;
    END
  END r0_rd_out[251]
  PIN r0_rd_out[252]
    DIRECTION OUTPUT ;
    USE SIGNAL ;
    SHAPE ABUTMENT ;
    PORT
      LAYER met2 ;
      RECT 2573.170 0.000 2573.310 0.420 ;
    END
  END r0_rd_out[252]
  PIN r0_rd_out[253]
    DIRECTION OUTPUT ;
    USE SIGNAL ;
    SHAPE ABUTMENT ;
    PORT
      LAYER met2 ;
      RECT 2578.230 0.000 2578.370 0.420 ;
    END
  END r0_rd_out[253]
  PIN r0_rd_out[254]
    DIRECTION OUTPUT ;
    USE SIGNAL ;
    SHAPE ABUTMENT ;
    PORT
      LAYER met2 ;
      RECT 2583.290 0.000 2583.430 0.420 ;
    END
  END r0_rd_out[254]
  PIN r0_rd_out[255]
    DIRECTION OUTPUT ;
    USE SIGNAL ;
    SHAPE ABUTMENT ;
    PORT
      LAYER met2 ;
      RECT 2588.350 0.000 2588.490 0.420 ;
    END
  END r0_rd_out[255]
  PIN r0_rd_out[256]
    DIRECTION OUTPUT ;
    USE SIGNAL ;
    SHAPE ABUTMENT ;
    PORT
      LAYER met2 ;
      RECT 2.690 1335.100 2.830 1335.520 ;
    END
  END r0_rd_out[256]
  PIN r0_rd_out[257]
    DIRECTION OUTPUT ;
    USE SIGNAL ;
    SHAPE ABUTMENT ;
    PORT
      LAYER met2 ;
      RECT 12.810 1335.100 12.950 1335.520 ;
    END
  END r0_rd_out[257]
  PIN r0_rd_out[258]
    DIRECTION OUTPUT ;
    USE SIGNAL ;
    SHAPE ABUTMENT ;
    PORT
      LAYER met2 ;
      RECT 22.930 1335.100 23.070 1335.520 ;
    END
  END r0_rd_out[258]
  PIN r0_rd_out[259]
    DIRECTION OUTPUT ;
    USE SIGNAL ;
    SHAPE ABUTMENT ;
    PORT
      LAYER met2 ;
      RECT 33.050 1335.100 33.190 1335.520 ;
    END
  END r0_rd_out[259]
  PIN r0_rd_out[260]
    DIRECTION OUTPUT ;
    USE SIGNAL ;
    SHAPE ABUTMENT ;
    PORT
      LAYER met2 ;
      RECT 43.170 1335.100 43.310 1335.520 ;
    END
  END r0_rd_out[260]
  PIN r0_rd_out[261]
    DIRECTION OUTPUT ;
    USE SIGNAL ;
    SHAPE ABUTMENT ;
    PORT
      LAYER met2 ;
      RECT 53.290 1335.100 53.430 1335.520 ;
    END
  END r0_rd_out[261]
  PIN r0_rd_out[262]
    DIRECTION OUTPUT ;
    USE SIGNAL ;
    SHAPE ABUTMENT ;
    PORT
      LAYER met2 ;
      RECT 63.410 1335.100 63.550 1335.520 ;
    END
  END r0_rd_out[262]
  PIN r0_rd_out[263]
    DIRECTION OUTPUT ;
    USE SIGNAL ;
    SHAPE ABUTMENT ;
    PORT
      LAYER met2 ;
      RECT 73.530 1335.100 73.670 1335.520 ;
    END
  END r0_rd_out[263]
  PIN r0_rd_out[264]
    DIRECTION OUTPUT ;
    USE SIGNAL ;
    SHAPE ABUTMENT ;
    PORT
      LAYER met2 ;
      RECT 83.650 1335.100 83.790 1335.520 ;
    END
  END r0_rd_out[264]
  PIN r0_rd_out[265]
    DIRECTION OUTPUT ;
    USE SIGNAL ;
    SHAPE ABUTMENT ;
    PORT
      LAYER met2 ;
      RECT 93.770 1335.100 93.910 1335.520 ;
    END
  END r0_rd_out[265]
  PIN r0_rd_out[266]
    DIRECTION OUTPUT ;
    USE SIGNAL ;
    SHAPE ABUTMENT ;
    PORT
      LAYER met2 ;
      RECT 103.890 1335.100 104.030 1335.520 ;
    END
  END r0_rd_out[266]
  PIN r0_rd_out[267]
    DIRECTION OUTPUT ;
    USE SIGNAL ;
    SHAPE ABUTMENT ;
    PORT
      LAYER met2 ;
      RECT 114.010 1335.100 114.150 1335.520 ;
    END
  END r0_rd_out[267]
  PIN r0_rd_out[268]
    DIRECTION OUTPUT ;
    USE SIGNAL ;
    SHAPE ABUTMENT ;
    PORT
      LAYER met2 ;
      RECT 124.130 1335.100 124.270 1335.520 ;
    END
  END r0_rd_out[268]
  PIN r0_rd_out[269]
    DIRECTION OUTPUT ;
    USE SIGNAL ;
    SHAPE ABUTMENT ;
    PORT
      LAYER met2 ;
      RECT 134.250 1335.100 134.390 1335.520 ;
    END
  END r0_rd_out[269]
  PIN r0_rd_out[270]
    DIRECTION OUTPUT ;
    USE SIGNAL ;
    SHAPE ABUTMENT ;
    PORT
      LAYER met2 ;
      RECT 144.370 1335.100 144.510 1335.520 ;
    END
  END r0_rd_out[270]
  PIN r0_rd_out[271]
    DIRECTION OUTPUT ;
    USE SIGNAL ;
    SHAPE ABUTMENT ;
    PORT
      LAYER met2 ;
      RECT 154.490 1335.100 154.630 1335.520 ;
    END
  END r0_rd_out[271]
  PIN r0_rd_out[272]
    DIRECTION OUTPUT ;
    USE SIGNAL ;
    SHAPE ABUTMENT ;
    PORT
      LAYER met2 ;
      RECT 164.610 1335.100 164.750 1335.520 ;
    END
  END r0_rd_out[272]
  PIN r0_rd_out[273]
    DIRECTION OUTPUT ;
    USE SIGNAL ;
    SHAPE ABUTMENT ;
    PORT
      LAYER met2 ;
      RECT 174.730 1335.100 174.870 1335.520 ;
    END
  END r0_rd_out[273]
  PIN r0_rd_out[274]
    DIRECTION OUTPUT ;
    USE SIGNAL ;
    SHAPE ABUTMENT ;
    PORT
      LAYER met2 ;
      RECT 184.850 1335.100 184.990 1335.520 ;
    END
  END r0_rd_out[274]
  PIN r0_rd_out[275]
    DIRECTION OUTPUT ;
    USE SIGNAL ;
    SHAPE ABUTMENT ;
    PORT
      LAYER met2 ;
      RECT 194.970 1335.100 195.110 1335.520 ;
    END
  END r0_rd_out[275]
  PIN r0_rd_out[276]
    DIRECTION OUTPUT ;
    USE SIGNAL ;
    SHAPE ABUTMENT ;
    PORT
      LAYER met2 ;
      RECT 205.090 1335.100 205.230 1335.520 ;
    END
  END r0_rd_out[276]
  PIN r0_rd_out[277]
    DIRECTION OUTPUT ;
    USE SIGNAL ;
    SHAPE ABUTMENT ;
    PORT
      LAYER met2 ;
      RECT 215.210 1335.100 215.350 1335.520 ;
    END
  END r0_rd_out[277]
  PIN r0_rd_out[278]
    DIRECTION OUTPUT ;
    USE SIGNAL ;
    SHAPE ABUTMENT ;
    PORT
      LAYER met2 ;
      RECT 225.330 1335.100 225.470 1335.520 ;
    END
  END r0_rd_out[278]
  PIN r0_rd_out[279]
    DIRECTION OUTPUT ;
    USE SIGNAL ;
    SHAPE ABUTMENT ;
    PORT
      LAYER met2 ;
      RECT 235.450 1335.100 235.590 1335.520 ;
    END
  END r0_rd_out[279]
  PIN r0_rd_out[280]
    DIRECTION OUTPUT ;
    USE SIGNAL ;
    SHAPE ABUTMENT ;
    PORT
      LAYER met2 ;
      RECT 245.570 1335.100 245.710 1335.520 ;
    END
  END r0_rd_out[280]
  PIN r0_rd_out[281]
    DIRECTION OUTPUT ;
    USE SIGNAL ;
    SHAPE ABUTMENT ;
    PORT
      LAYER met2 ;
      RECT 255.690 1335.100 255.830 1335.520 ;
    END
  END r0_rd_out[281]
  PIN r0_rd_out[282]
    DIRECTION OUTPUT ;
    USE SIGNAL ;
    SHAPE ABUTMENT ;
    PORT
      LAYER met2 ;
      RECT 265.810 1335.100 265.950 1335.520 ;
    END
  END r0_rd_out[282]
  PIN r0_rd_out[283]
    DIRECTION OUTPUT ;
    USE SIGNAL ;
    SHAPE ABUTMENT ;
    PORT
      LAYER met2 ;
      RECT 275.930 1335.100 276.070 1335.520 ;
    END
  END r0_rd_out[283]
  PIN r0_rd_out[284]
    DIRECTION OUTPUT ;
    USE SIGNAL ;
    SHAPE ABUTMENT ;
    PORT
      LAYER met2 ;
      RECT 286.050 1335.100 286.190 1335.520 ;
    END
  END r0_rd_out[284]
  PIN r0_rd_out[285]
    DIRECTION OUTPUT ;
    USE SIGNAL ;
    SHAPE ABUTMENT ;
    PORT
      LAYER met2 ;
      RECT 296.170 1335.100 296.310 1335.520 ;
    END
  END r0_rd_out[285]
  PIN r0_rd_out[286]
    DIRECTION OUTPUT ;
    USE SIGNAL ;
    SHAPE ABUTMENT ;
    PORT
      LAYER met2 ;
      RECT 306.290 1335.100 306.430 1335.520 ;
    END
  END r0_rd_out[286]
  PIN r0_rd_out[287]
    DIRECTION OUTPUT ;
    USE SIGNAL ;
    SHAPE ABUTMENT ;
    PORT
      LAYER met2 ;
      RECT 316.410 1335.100 316.550 1335.520 ;
    END
  END r0_rd_out[287]
  PIN r0_rd_out[288]
    DIRECTION OUTPUT ;
    USE SIGNAL ;
    SHAPE ABUTMENT ;
    PORT
      LAYER met2 ;
      RECT 326.530 1335.100 326.670 1335.520 ;
    END
  END r0_rd_out[288]
  PIN r0_rd_out[289]
    DIRECTION OUTPUT ;
    USE SIGNAL ;
    SHAPE ABUTMENT ;
    PORT
      LAYER met2 ;
      RECT 336.650 1335.100 336.790 1335.520 ;
    END
  END r0_rd_out[289]
  PIN r0_rd_out[290]
    DIRECTION OUTPUT ;
    USE SIGNAL ;
    SHAPE ABUTMENT ;
    PORT
      LAYER met2 ;
      RECT 346.770 1335.100 346.910 1335.520 ;
    END
  END r0_rd_out[290]
  PIN r0_rd_out[291]
    DIRECTION OUTPUT ;
    USE SIGNAL ;
    SHAPE ABUTMENT ;
    PORT
      LAYER met2 ;
      RECT 356.890 1335.100 357.030 1335.520 ;
    END
  END r0_rd_out[291]
  PIN r0_rd_out[292]
    DIRECTION OUTPUT ;
    USE SIGNAL ;
    SHAPE ABUTMENT ;
    PORT
      LAYER met2 ;
      RECT 367.010 1335.100 367.150 1335.520 ;
    END
  END r0_rd_out[292]
  PIN r0_rd_out[293]
    DIRECTION OUTPUT ;
    USE SIGNAL ;
    SHAPE ABUTMENT ;
    PORT
      LAYER met2 ;
      RECT 377.130 1335.100 377.270 1335.520 ;
    END
  END r0_rd_out[293]
  PIN r0_rd_out[294]
    DIRECTION OUTPUT ;
    USE SIGNAL ;
    SHAPE ABUTMENT ;
    PORT
      LAYER met2 ;
      RECT 387.250 1335.100 387.390 1335.520 ;
    END
  END r0_rd_out[294]
  PIN r0_rd_out[295]
    DIRECTION OUTPUT ;
    USE SIGNAL ;
    SHAPE ABUTMENT ;
    PORT
      LAYER met2 ;
      RECT 397.370 1335.100 397.510 1335.520 ;
    END
  END r0_rd_out[295]
  PIN r0_rd_out[296]
    DIRECTION OUTPUT ;
    USE SIGNAL ;
    SHAPE ABUTMENT ;
    PORT
      LAYER met2 ;
      RECT 407.490 1335.100 407.630 1335.520 ;
    END
  END r0_rd_out[296]
  PIN r0_rd_out[297]
    DIRECTION OUTPUT ;
    USE SIGNAL ;
    SHAPE ABUTMENT ;
    PORT
      LAYER met2 ;
      RECT 417.610 1335.100 417.750 1335.520 ;
    END
  END r0_rd_out[297]
  PIN r0_rd_out[298]
    DIRECTION OUTPUT ;
    USE SIGNAL ;
    SHAPE ABUTMENT ;
    PORT
      LAYER met2 ;
      RECT 427.730 1335.100 427.870 1335.520 ;
    END
  END r0_rd_out[298]
  PIN r0_rd_out[299]
    DIRECTION OUTPUT ;
    USE SIGNAL ;
    SHAPE ABUTMENT ;
    PORT
      LAYER met2 ;
      RECT 437.850 1335.100 437.990 1335.520 ;
    END
  END r0_rd_out[299]
  PIN r0_rd_out[300]
    DIRECTION OUTPUT ;
    USE SIGNAL ;
    SHAPE ABUTMENT ;
    PORT
      LAYER met2 ;
      RECT 447.970 1335.100 448.110 1335.520 ;
    END
  END r0_rd_out[300]
  PIN r0_rd_out[301]
    DIRECTION OUTPUT ;
    USE SIGNAL ;
    SHAPE ABUTMENT ;
    PORT
      LAYER met2 ;
      RECT 458.090 1335.100 458.230 1335.520 ;
    END
  END r0_rd_out[301]
  PIN r0_rd_out[302]
    DIRECTION OUTPUT ;
    USE SIGNAL ;
    SHAPE ABUTMENT ;
    PORT
      LAYER met2 ;
      RECT 468.210 1335.100 468.350 1335.520 ;
    END
  END r0_rd_out[302]
  PIN r0_rd_out[303]
    DIRECTION OUTPUT ;
    USE SIGNAL ;
    SHAPE ABUTMENT ;
    PORT
      LAYER met2 ;
      RECT 478.330 1335.100 478.470 1335.520 ;
    END
  END r0_rd_out[303]
  PIN r0_rd_out[304]
    DIRECTION OUTPUT ;
    USE SIGNAL ;
    SHAPE ABUTMENT ;
    PORT
      LAYER met2 ;
      RECT 488.450 1335.100 488.590 1335.520 ;
    END
  END r0_rd_out[304]
  PIN r0_rd_out[305]
    DIRECTION OUTPUT ;
    USE SIGNAL ;
    SHAPE ABUTMENT ;
    PORT
      LAYER met2 ;
      RECT 498.570 1335.100 498.710 1335.520 ;
    END
  END r0_rd_out[305]
  PIN r0_rd_out[306]
    DIRECTION OUTPUT ;
    USE SIGNAL ;
    SHAPE ABUTMENT ;
    PORT
      LAYER met2 ;
      RECT 508.690 1335.100 508.830 1335.520 ;
    END
  END r0_rd_out[306]
  PIN r0_rd_out[307]
    DIRECTION OUTPUT ;
    USE SIGNAL ;
    SHAPE ABUTMENT ;
    PORT
      LAYER met2 ;
      RECT 518.810 1335.100 518.950 1335.520 ;
    END
  END r0_rd_out[307]
  PIN r0_rd_out[308]
    DIRECTION OUTPUT ;
    USE SIGNAL ;
    SHAPE ABUTMENT ;
    PORT
      LAYER met2 ;
      RECT 528.930 1335.100 529.070 1335.520 ;
    END
  END r0_rd_out[308]
  PIN r0_rd_out[309]
    DIRECTION OUTPUT ;
    USE SIGNAL ;
    SHAPE ABUTMENT ;
    PORT
      LAYER met2 ;
      RECT 539.050 1335.100 539.190 1335.520 ;
    END
  END r0_rd_out[309]
  PIN r0_rd_out[310]
    DIRECTION OUTPUT ;
    USE SIGNAL ;
    SHAPE ABUTMENT ;
    PORT
      LAYER met2 ;
      RECT 549.170 1335.100 549.310 1335.520 ;
    END
  END r0_rd_out[310]
  PIN r0_rd_out[311]
    DIRECTION OUTPUT ;
    USE SIGNAL ;
    SHAPE ABUTMENT ;
    PORT
      LAYER met2 ;
      RECT 559.290 1335.100 559.430 1335.520 ;
    END
  END r0_rd_out[311]
  PIN r0_rd_out[312]
    DIRECTION OUTPUT ;
    USE SIGNAL ;
    SHAPE ABUTMENT ;
    PORT
      LAYER met2 ;
      RECT 569.410 1335.100 569.550 1335.520 ;
    END
  END r0_rd_out[312]
  PIN r0_rd_out[313]
    DIRECTION OUTPUT ;
    USE SIGNAL ;
    SHAPE ABUTMENT ;
    PORT
      LAYER met2 ;
      RECT 579.530 1335.100 579.670 1335.520 ;
    END
  END r0_rd_out[313]
  PIN r0_rd_out[314]
    DIRECTION OUTPUT ;
    USE SIGNAL ;
    SHAPE ABUTMENT ;
    PORT
      LAYER met2 ;
      RECT 589.650 1335.100 589.790 1335.520 ;
    END
  END r0_rd_out[314]
  PIN r0_rd_out[315]
    DIRECTION OUTPUT ;
    USE SIGNAL ;
    SHAPE ABUTMENT ;
    PORT
      LAYER met2 ;
      RECT 599.770 1335.100 599.910 1335.520 ;
    END
  END r0_rd_out[315]
  PIN r0_rd_out[316]
    DIRECTION OUTPUT ;
    USE SIGNAL ;
    SHAPE ABUTMENT ;
    PORT
      LAYER met2 ;
      RECT 609.890 1335.100 610.030 1335.520 ;
    END
  END r0_rd_out[316]
  PIN r0_rd_out[317]
    DIRECTION OUTPUT ;
    USE SIGNAL ;
    SHAPE ABUTMENT ;
    PORT
      LAYER met2 ;
      RECT 620.010 1335.100 620.150 1335.520 ;
    END
  END r0_rd_out[317]
  PIN r0_rd_out[318]
    DIRECTION OUTPUT ;
    USE SIGNAL ;
    SHAPE ABUTMENT ;
    PORT
      LAYER met2 ;
      RECT 630.130 1335.100 630.270 1335.520 ;
    END
  END r0_rd_out[318]
  PIN r0_rd_out[319]
    DIRECTION OUTPUT ;
    USE SIGNAL ;
    SHAPE ABUTMENT ;
    PORT
      LAYER met2 ;
      RECT 640.250 1335.100 640.390 1335.520 ;
    END
  END r0_rd_out[319]
  PIN r0_rd_out[320]
    DIRECTION OUTPUT ;
    USE SIGNAL ;
    SHAPE ABUTMENT ;
    PORT
      LAYER met2 ;
      RECT 650.370 1335.100 650.510 1335.520 ;
    END
  END r0_rd_out[320]
  PIN r0_rd_out[321]
    DIRECTION OUTPUT ;
    USE SIGNAL ;
    SHAPE ABUTMENT ;
    PORT
      LAYER met2 ;
      RECT 660.490 1335.100 660.630 1335.520 ;
    END
  END r0_rd_out[321]
  PIN r0_rd_out[322]
    DIRECTION OUTPUT ;
    USE SIGNAL ;
    SHAPE ABUTMENT ;
    PORT
      LAYER met2 ;
      RECT 670.610 1335.100 670.750 1335.520 ;
    END
  END r0_rd_out[322]
  PIN r0_rd_out[323]
    DIRECTION OUTPUT ;
    USE SIGNAL ;
    SHAPE ABUTMENT ;
    PORT
      LAYER met2 ;
      RECT 680.730 1335.100 680.870 1335.520 ;
    END
  END r0_rd_out[323]
  PIN r0_rd_out[324]
    DIRECTION OUTPUT ;
    USE SIGNAL ;
    SHAPE ABUTMENT ;
    PORT
      LAYER met2 ;
      RECT 690.850 1335.100 690.990 1335.520 ;
    END
  END r0_rd_out[324]
  PIN r0_rd_out[325]
    DIRECTION OUTPUT ;
    USE SIGNAL ;
    SHAPE ABUTMENT ;
    PORT
      LAYER met2 ;
      RECT 700.970 1335.100 701.110 1335.520 ;
    END
  END r0_rd_out[325]
  PIN r0_rd_out[326]
    DIRECTION OUTPUT ;
    USE SIGNAL ;
    SHAPE ABUTMENT ;
    PORT
      LAYER met2 ;
      RECT 711.090 1335.100 711.230 1335.520 ;
    END
  END r0_rd_out[326]
  PIN r0_rd_out[327]
    DIRECTION OUTPUT ;
    USE SIGNAL ;
    SHAPE ABUTMENT ;
    PORT
      LAYER met2 ;
      RECT 721.210 1335.100 721.350 1335.520 ;
    END
  END r0_rd_out[327]
  PIN r0_rd_out[328]
    DIRECTION OUTPUT ;
    USE SIGNAL ;
    SHAPE ABUTMENT ;
    PORT
      LAYER met2 ;
      RECT 731.330 1335.100 731.470 1335.520 ;
    END
  END r0_rd_out[328]
  PIN r0_rd_out[329]
    DIRECTION OUTPUT ;
    USE SIGNAL ;
    SHAPE ABUTMENT ;
    PORT
      LAYER met2 ;
      RECT 741.450 1335.100 741.590 1335.520 ;
    END
  END r0_rd_out[329]
  PIN r0_rd_out[330]
    DIRECTION OUTPUT ;
    USE SIGNAL ;
    SHAPE ABUTMENT ;
    PORT
      LAYER met2 ;
      RECT 751.570 1335.100 751.710 1335.520 ;
    END
  END r0_rd_out[330]
  PIN r0_rd_out[331]
    DIRECTION OUTPUT ;
    USE SIGNAL ;
    SHAPE ABUTMENT ;
    PORT
      LAYER met2 ;
      RECT 761.690 1335.100 761.830 1335.520 ;
    END
  END r0_rd_out[331]
  PIN r0_rd_out[332]
    DIRECTION OUTPUT ;
    USE SIGNAL ;
    SHAPE ABUTMENT ;
    PORT
      LAYER met2 ;
      RECT 771.810 1335.100 771.950 1335.520 ;
    END
  END r0_rd_out[332]
  PIN r0_rd_out[333]
    DIRECTION OUTPUT ;
    USE SIGNAL ;
    SHAPE ABUTMENT ;
    PORT
      LAYER met2 ;
      RECT 781.930 1335.100 782.070 1335.520 ;
    END
  END r0_rd_out[333]
  PIN r0_rd_out[334]
    DIRECTION OUTPUT ;
    USE SIGNAL ;
    SHAPE ABUTMENT ;
    PORT
      LAYER met2 ;
      RECT 792.050 1335.100 792.190 1335.520 ;
    END
  END r0_rd_out[334]
  PIN r0_rd_out[335]
    DIRECTION OUTPUT ;
    USE SIGNAL ;
    SHAPE ABUTMENT ;
    PORT
      LAYER met2 ;
      RECT 802.170 1335.100 802.310 1335.520 ;
    END
  END r0_rd_out[335]
  PIN r0_rd_out[336]
    DIRECTION OUTPUT ;
    USE SIGNAL ;
    SHAPE ABUTMENT ;
    PORT
      LAYER met2 ;
      RECT 812.290 1335.100 812.430 1335.520 ;
    END
  END r0_rd_out[336]
  PIN r0_rd_out[337]
    DIRECTION OUTPUT ;
    USE SIGNAL ;
    SHAPE ABUTMENT ;
    PORT
      LAYER met2 ;
      RECT 822.410 1335.100 822.550 1335.520 ;
    END
  END r0_rd_out[337]
  PIN r0_rd_out[338]
    DIRECTION OUTPUT ;
    USE SIGNAL ;
    SHAPE ABUTMENT ;
    PORT
      LAYER met2 ;
      RECT 832.530 1335.100 832.670 1335.520 ;
    END
  END r0_rd_out[338]
  PIN r0_rd_out[339]
    DIRECTION OUTPUT ;
    USE SIGNAL ;
    SHAPE ABUTMENT ;
    PORT
      LAYER met2 ;
      RECT 842.650 1335.100 842.790 1335.520 ;
    END
  END r0_rd_out[339]
  PIN r0_rd_out[340]
    DIRECTION OUTPUT ;
    USE SIGNAL ;
    SHAPE ABUTMENT ;
    PORT
      LAYER met2 ;
      RECT 852.770 1335.100 852.910 1335.520 ;
    END
  END r0_rd_out[340]
  PIN r0_rd_out[341]
    DIRECTION OUTPUT ;
    USE SIGNAL ;
    SHAPE ABUTMENT ;
    PORT
      LAYER met2 ;
      RECT 862.890 1335.100 863.030 1335.520 ;
    END
  END r0_rd_out[341]
  PIN r0_rd_out[342]
    DIRECTION OUTPUT ;
    USE SIGNAL ;
    SHAPE ABUTMENT ;
    PORT
      LAYER met2 ;
      RECT 873.010 1335.100 873.150 1335.520 ;
    END
  END r0_rd_out[342]
  PIN r0_rd_out[343]
    DIRECTION OUTPUT ;
    USE SIGNAL ;
    SHAPE ABUTMENT ;
    PORT
      LAYER met2 ;
      RECT 883.130 1335.100 883.270 1335.520 ;
    END
  END r0_rd_out[343]
  PIN r0_rd_out[344]
    DIRECTION OUTPUT ;
    USE SIGNAL ;
    SHAPE ABUTMENT ;
    PORT
      LAYER met2 ;
      RECT 893.250 1335.100 893.390 1335.520 ;
    END
  END r0_rd_out[344]
  PIN r0_rd_out[345]
    DIRECTION OUTPUT ;
    USE SIGNAL ;
    SHAPE ABUTMENT ;
    PORT
      LAYER met2 ;
      RECT 903.370 1335.100 903.510 1335.520 ;
    END
  END r0_rd_out[345]
  PIN r0_rd_out[346]
    DIRECTION OUTPUT ;
    USE SIGNAL ;
    SHAPE ABUTMENT ;
    PORT
      LAYER met2 ;
      RECT 913.490 1335.100 913.630 1335.520 ;
    END
  END r0_rd_out[346]
  PIN r0_rd_out[347]
    DIRECTION OUTPUT ;
    USE SIGNAL ;
    SHAPE ABUTMENT ;
    PORT
      LAYER met2 ;
      RECT 923.610 1335.100 923.750 1335.520 ;
    END
  END r0_rd_out[347]
  PIN r0_rd_out[348]
    DIRECTION OUTPUT ;
    USE SIGNAL ;
    SHAPE ABUTMENT ;
    PORT
      LAYER met2 ;
      RECT 933.730 1335.100 933.870 1335.520 ;
    END
  END r0_rd_out[348]
  PIN r0_rd_out[349]
    DIRECTION OUTPUT ;
    USE SIGNAL ;
    SHAPE ABUTMENT ;
    PORT
      LAYER met2 ;
      RECT 943.850 1335.100 943.990 1335.520 ;
    END
  END r0_rd_out[349]
  PIN r0_rd_out[350]
    DIRECTION OUTPUT ;
    USE SIGNAL ;
    SHAPE ABUTMENT ;
    PORT
      LAYER met2 ;
      RECT 953.970 1335.100 954.110 1335.520 ;
    END
  END r0_rd_out[350]
  PIN r0_rd_out[351]
    DIRECTION OUTPUT ;
    USE SIGNAL ;
    SHAPE ABUTMENT ;
    PORT
      LAYER met2 ;
      RECT 964.090 1335.100 964.230 1335.520 ;
    END
  END r0_rd_out[351]
  PIN r0_rd_out[352]
    DIRECTION OUTPUT ;
    USE SIGNAL ;
    SHAPE ABUTMENT ;
    PORT
      LAYER met2 ;
      RECT 974.210 1335.100 974.350 1335.520 ;
    END
  END r0_rd_out[352]
  PIN r0_rd_out[353]
    DIRECTION OUTPUT ;
    USE SIGNAL ;
    SHAPE ABUTMENT ;
    PORT
      LAYER met2 ;
      RECT 984.330 1335.100 984.470 1335.520 ;
    END
  END r0_rd_out[353]
  PIN r0_rd_out[354]
    DIRECTION OUTPUT ;
    USE SIGNAL ;
    SHAPE ABUTMENT ;
    PORT
      LAYER met2 ;
      RECT 994.450 1335.100 994.590 1335.520 ;
    END
  END r0_rd_out[354]
  PIN r0_rd_out[355]
    DIRECTION OUTPUT ;
    USE SIGNAL ;
    SHAPE ABUTMENT ;
    PORT
      LAYER met2 ;
      RECT 1004.570 1335.100 1004.710 1335.520 ;
    END
  END r0_rd_out[355]
  PIN r0_rd_out[356]
    DIRECTION OUTPUT ;
    USE SIGNAL ;
    SHAPE ABUTMENT ;
    PORT
      LAYER met2 ;
      RECT 1014.690 1335.100 1014.830 1335.520 ;
    END
  END r0_rd_out[356]
  PIN r0_rd_out[357]
    DIRECTION OUTPUT ;
    USE SIGNAL ;
    SHAPE ABUTMENT ;
    PORT
      LAYER met2 ;
      RECT 1024.810 1335.100 1024.950 1335.520 ;
    END
  END r0_rd_out[357]
  PIN r0_rd_out[358]
    DIRECTION OUTPUT ;
    USE SIGNAL ;
    SHAPE ABUTMENT ;
    PORT
      LAYER met2 ;
      RECT 1034.930 1335.100 1035.070 1335.520 ;
    END
  END r0_rd_out[358]
  PIN r0_rd_out[359]
    DIRECTION OUTPUT ;
    USE SIGNAL ;
    SHAPE ABUTMENT ;
    PORT
      LAYER met2 ;
      RECT 1045.050 1335.100 1045.190 1335.520 ;
    END
  END r0_rd_out[359]
  PIN r0_rd_out[360]
    DIRECTION OUTPUT ;
    USE SIGNAL ;
    SHAPE ABUTMENT ;
    PORT
      LAYER met2 ;
      RECT 1055.170 1335.100 1055.310 1335.520 ;
    END
  END r0_rd_out[360]
  PIN r0_rd_out[361]
    DIRECTION OUTPUT ;
    USE SIGNAL ;
    SHAPE ABUTMENT ;
    PORT
      LAYER met2 ;
      RECT 1065.290 1335.100 1065.430 1335.520 ;
    END
  END r0_rd_out[361]
  PIN r0_rd_out[362]
    DIRECTION OUTPUT ;
    USE SIGNAL ;
    SHAPE ABUTMENT ;
    PORT
      LAYER met2 ;
      RECT 1075.410 1335.100 1075.550 1335.520 ;
    END
  END r0_rd_out[362]
  PIN r0_rd_out[363]
    DIRECTION OUTPUT ;
    USE SIGNAL ;
    SHAPE ABUTMENT ;
    PORT
      LAYER met2 ;
      RECT 1085.530 1335.100 1085.670 1335.520 ;
    END
  END r0_rd_out[363]
  PIN r0_rd_out[364]
    DIRECTION OUTPUT ;
    USE SIGNAL ;
    SHAPE ABUTMENT ;
    PORT
      LAYER met2 ;
      RECT 1095.650 1335.100 1095.790 1335.520 ;
    END
  END r0_rd_out[364]
  PIN r0_rd_out[365]
    DIRECTION OUTPUT ;
    USE SIGNAL ;
    SHAPE ABUTMENT ;
    PORT
      LAYER met2 ;
      RECT 1105.770 1335.100 1105.910 1335.520 ;
    END
  END r0_rd_out[365]
  PIN r0_rd_out[366]
    DIRECTION OUTPUT ;
    USE SIGNAL ;
    SHAPE ABUTMENT ;
    PORT
      LAYER met2 ;
      RECT 1115.890 1335.100 1116.030 1335.520 ;
    END
  END r0_rd_out[366]
  PIN r0_rd_out[367]
    DIRECTION OUTPUT ;
    USE SIGNAL ;
    SHAPE ABUTMENT ;
    PORT
      LAYER met2 ;
      RECT 1126.010 1335.100 1126.150 1335.520 ;
    END
  END r0_rd_out[367]
  PIN r0_rd_out[368]
    DIRECTION OUTPUT ;
    USE SIGNAL ;
    SHAPE ABUTMENT ;
    PORT
      LAYER met2 ;
      RECT 1136.130 1335.100 1136.270 1335.520 ;
    END
  END r0_rd_out[368]
  PIN r0_rd_out[369]
    DIRECTION OUTPUT ;
    USE SIGNAL ;
    SHAPE ABUTMENT ;
    PORT
      LAYER met2 ;
      RECT 1146.250 1335.100 1146.390 1335.520 ;
    END
  END r0_rd_out[369]
  PIN r0_rd_out[370]
    DIRECTION OUTPUT ;
    USE SIGNAL ;
    SHAPE ABUTMENT ;
    PORT
      LAYER met2 ;
      RECT 1156.370 1335.100 1156.510 1335.520 ;
    END
  END r0_rd_out[370]
  PIN r0_rd_out[371]
    DIRECTION OUTPUT ;
    USE SIGNAL ;
    SHAPE ABUTMENT ;
    PORT
      LAYER met2 ;
      RECT 1166.490 1335.100 1166.630 1335.520 ;
    END
  END r0_rd_out[371]
  PIN r0_rd_out[372]
    DIRECTION OUTPUT ;
    USE SIGNAL ;
    SHAPE ABUTMENT ;
    PORT
      LAYER met2 ;
      RECT 1176.610 1335.100 1176.750 1335.520 ;
    END
  END r0_rd_out[372]
  PIN r0_rd_out[373]
    DIRECTION OUTPUT ;
    USE SIGNAL ;
    SHAPE ABUTMENT ;
    PORT
      LAYER met2 ;
      RECT 1186.730 1335.100 1186.870 1335.520 ;
    END
  END r0_rd_out[373]
  PIN r0_rd_out[374]
    DIRECTION OUTPUT ;
    USE SIGNAL ;
    SHAPE ABUTMENT ;
    PORT
      LAYER met2 ;
      RECT 1196.850 1335.100 1196.990 1335.520 ;
    END
  END r0_rd_out[374]
  PIN r0_rd_out[375]
    DIRECTION OUTPUT ;
    USE SIGNAL ;
    SHAPE ABUTMENT ;
    PORT
      LAYER met2 ;
      RECT 1206.970 1335.100 1207.110 1335.520 ;
    END
  END r0_rd_out[375]
  PIN r0_rd_out[376]
    DIRECTION OUTPUT ;
    USE SIGNAL ;
    SHAPE ABUTMENT ;
    PORT
      LAYER met2 ;
      RECT 1217.090 1335.100 1217.230 1335.520 ;
    END
  END r0_rd_out[376]
  PIN r0_rd_out[377]
    DIRECTION OUTPUT ;
    USE SIGNAL ;
    SHAPE ABUTMENT ;
    PORT
      LAYER met2 ;
      RECT 1227.210 1335.100 1227.350 1335.520 ;
    END
  END r0_rd_out[377]
  PIN r0_rd_out[378]
    DIRECTION OUTPUT ;
    USE SIGNAL ;
    SHAPE ABUTMENT ;
    PORT
      LAYER met2 ;
      RECT 1237.330 1335.100 1237.470 1335.520 ;
    END
  END r0_rd_out[378]
  PIN r0_rd_out[379]
    DIRECTION OUTPUT ;
    USE SIGNAL ;
    SHAPE ABUTMENT ;
    PORT
      LAYER met2 ;
      RECT 1247.450 1335.100 1247.590 1335.520 ;
    END
  END r0_rd_out[379]
  PIN r0_rd_out[380]
    DIRECTION OUTPUT ;
    USE SIGNAL ;
    SHAPE ABUTMENT ;
    PORT
      LAYER met2 ;
      RECT 1257.570 1335.100 1257.710 1335.520 ;
    END
  END r0_rd_out[380]
  PIN r0_rd_out[381]
    DIRECTION OUTPUT ;
    USE SIGNAL ;
    SHAPE ABUTMENT ;
    PORT
      LAYER met2 ;
      RECT 1267.690 1335.100 1267.830 1335.520 ;
    END
  END r0_rd_out[381]
  PIN r0_rd_out[382]
    DIRECTION OUTPUT ;
    USE SIGNAL ;
    SHAPE ABUTMENT ;
    PORT
      LAYER met2 ;
      RECT 1277.810 1335.100 1277.950 1335.520 ;
    END
  END r0_rd_out[382]
  PIN r0_rd_out[383]
    DIRECTION OUTPUT ;
    USE SIGNAL ;
    SHAPE ABUTMENT ;
    PORT
      LAYER met2 ;
      RECT 1287.930 1335.100 1288.070 1335.520 ;
    END
  END r0_rd_out[383]
  PIN r0_rd_out[384]
    DIRECTION OUTPUT ;
    USE SIGNAL ;
    SHAPE ABUTMENT ;
    PORT
      LAYER met2 ;
      RECT 1298.050 1335.100 1298.190 1335.520 ;
    END
  END r0_rd_out[384]
  PIN r0_rd_out[385]
    DIRECTION OUTPUT ;
    USE SIGNAL ;
    SHAPE ABUTMENT ;
    PORT
      LAYER met2 ;
      RECT 1308.170 1335.100 1308.310 1335.520 ;
    END
  END r0_rd_out[385]
  PIN r0_rd_out[386]
    DIRECTION OUTPUT ;
    USE SIGNAL ;
    SHAPE ABUTMENT ;
    PORT
      LAYER met2 ;
      RECT 1318.290 1335.100 1318.430 1335.520 ;
    END
  END r0_rd_out[386]
  PIN r0_rd_out[387]
    DIRECTION OUTPUT ;
    USE SIGNAL ;
    SHAPE ABUTMENT ;
    PORT
      LAYER met2 ;
      RECT 1328.410 1335.100 1328.550 1335.520 ;
    END
  END r0_rd_out[387]
  PIN r0_rd_out[388]
    DIRECTION OUTPUT ;
    USE SIGNAL ;
    SHAPE ABUTMENT ;
    PORT
      LAYER met2 ;
      RECT 1338.530 1335.100 1338.670 1335.520 ;
    END
  END r0_rd_out[388]
  PIN r0_rd_out[389]
    DIRECTION OUTPUT ;
    USE SIGNAL ;
    SHAPE ABUTMENT ;
    PORT
      LAYER met2 ;
      RECT 1348.650 1335.100 1348.790 1335.520 ;
    END
  END r0_rd_out[389]
  PIN r0_rd_out[390]
    DIRECTION OUTPUT ;
    USE SIGNAL ;
    SHAPE ABUTMENT ;
    PORT
      LAYER met2 ;
      RECT 1358.770 1335.100 1358.910 1335.520 ;
    END
  END r0_rd_out[390]
  PIN r0_rd_out[391]
    DIRECTION OUTPUT ;
    USE SIGNAL ;
    SHAPE ABUTMENT ;
    PORT
      LAYER met2 ;
      RECT 1368.890 1335.100 1369.030 1335.520 ;
    END
  END r0_rd_out[391]
  PIN r0_rd_out[392]
    DIRECTION OUTPUT ;
    USE SIGNAL ;
    SHAPE ABUTMENT ;
    PORT
      LAYER met2 ;
      RECT 1379.010 1335.100 1379.150 1335.520 ;
    END
  END r0_rd_out[392]
  PIN r0_rd_out[393]
    DIRECTION OUTPUT ;
    USE SIGNAL ;
    SHAPE ABUTMENT ;
    PORT
      LAYER met2 ;
      RECT 1389.130 1335.100 1389.270 1335.520 ;
    END
  END r0_rd_out[393]
  PIN r0_rd_out[394]
    DIRECTION OUTPUT ;
    USE SIGNAL ;
    SHAPE ABUTMENT ;
    PORT
      LAYER met2 ;
      RECT 1399.250 1335.100 1399.390 1335.520 ;
    END
  END r0_rd_out[394]
  PIN r0_rd_out[395]
    DIRECTION OUTPUT ;
    USE SIGNAL ;
    SHAPE ABUTMENT ;
    PORT
      LAYER met2 ;
      RECT 1409.370 1335.100 1409.510 1335.520 ;
    END
  END r0_rd_out[395]
  PIN r0_rd_out[396]
    DIRECTION OUTPUT ;
    USE SIGNAL ;
    SHAPE ABUTMENT ;
    PORT
      LAYER met2 ;
      RECT 1419.490 1335.100 1419.630 1335.520 ;
    END
  END r0_rd_out[396]
  PIN r0_rd_out[397]
    DIRECTION OUTPUT ;
    USE SIGNAL ;
    SHAPE ABUTMENT ;
    PORT
      LAYER met2 ;
      RECT 1429.610 1335.100 1429.750 1335.520 ;
    END
  END r0_rd_out[397]
  PIN r0_rd_out[398]
    DIRECTION OUTPUT ;
    USE SIGNAL ;
    SHAPE ABUTMENT ;
    PORT
      LAYER met2 ;
      RECT 1439.730 1335.100 1439.870 1335.520 ;
    END
  END r0_rd_out[398]
  PIN r0_rd_out[399]
    DIRECTION OUTPUT ;
    USE SIGNAL ;
    SHAPE ABUTMENT ;
    PORT
      LAYER met2 ;
      RECT 1449.850 1335.100 1449.990 1335.520 ;
    END
  END r0_rd_out[399]
  PIN r0_rd_out[400]
    DIRECTION OUTPUT ;
    USE SIGNAL ;
    SHAPE ABUTMENT ;
    PORT
      LAYER met2 ;
      RECT 1459.970 1335.100 1460.110 1335.520 ;
    END
  END r0_rd_out[400]
  PIN r0_rd_out[401]
    DIRECTION OUTPUT ;
    USE SIGNAL ;
    SHAPE ABUTMENT ;
    PORT
      LAYER met2 ;
      RECT 1470.090 1335.100 1470.230 1335.520 ;
    END
  END r0_rd_out[401]
  PIN r0_rd_out[402]
    DIRECTION OUTPUT ;
    USE SIGNAL ;
    SHAPE ABUTMENT ;
    PORT
      LAYER met2 ;
      RECT 1480.210 1335.100 1480.350 1335.520 ;
    END
  END r0_rd_out[402]
  PIN r0_rd_out[403]
    DIRECTION OUTPUT ;
    USE SIGNAL ;
    SHAPE ABUTMENT ;
    PORT
      LAYER met2 ;
      RECT 1490.330 1335.100 1490.470 1335.520 ;
    END
  END r0_rd_out[403]
  PIN r0_rd_out[404]
    DIRECTION OUTPUT ;
    USE SIGNAL ;
    SHAPE ABUTMENT ;
    PORT
      LAYER met2 ;
      RECT 1500.450 1335.100 1500.590 1335.520 ;
    END
  END r0_rd_out[404]
  PIN r0_rd_out[405]
    DIRECTION OUTPUT ;
    USE SIGNAL ;
    SHAPE ABUTMENT ;
    PORT
      LAYER met2 ;
      RECT 1510.570 1335.100 1510.710 1335.520 ;
    END
  END r0_rd_out[405]
  PIN r0_rd_out[406]
    DIRECTION OUTPUT ;
    USE SIGNAL ;
    SHAPE ABUTMENT ;
    PORT
      LAYER met2 ;
      RECT 1520.690 1335.100 1520.830 1335.520 ;
    END
  END r0_rd_out[406]
  PIN r0_rd_out[407]
    DIRECTION OUTPUT ;
    USE SIGNAL ;
    SHAPE ABUTMENT ;
    PORT
      LAYER met2 ;
      RECT 1530.810 1335.100 1530.950 1335.520 ;
    END
  END r0_rd_out[407]
  PIN r0_rd_out[408]
    DIRECTION OUTPUT ;
    USE SIGNAL ;
    SHAPE ABUTMENT ;
    PORT
      LAYER met2 ;
      RECT 1540.930 1335.100 1541.070 1335.520 ;
    END
  END r0_rd_out[408]
  PIN r0_rd_out[409]
    DIRECTION OUTPUT ;
    USE SIGNAL ;
    SHAPE ABUTMENT ;
    PORT
      LAYER met2 ;
      RECT 1551.050 1335.100 1551.190 1335.520 ;
    END
  END r0_rd_out[409]
  PIN r0_rd_out[410]
    DIRECTION OUTPUT ;
    USE SIGNAL ;
    SHAPE ABUTMENT ;
    PORT
      LAYER met2 ;
      RECT 1561.170 1335.100 1561.310 1335.520 ;
    END
  END r0_rd_out[410]
  PIN r0_rd_out[411]
    DIRECTION OUTPUT ;
    USE SIGNAL ;
    SHAPE ABUTMENT ;
    PORT
      LAYER met2 ;
      RECT 1571.290 1335.100 1571.430 1335.520 ;
    END
  END r0_rd_out[411]
  PIN r0_rd_out[412]
    DIRECTION OUTPUT ;
    USE SIGNAL ;
    SHAPE ABUTMENT ;
    PORT
      LAYER met2 ;
      RECT 1581.410 1335.100 1581.550 1335.520 ;
    END
  END r0_rd_out[412]
  PIN r0_rd_out[413]
    DIRECTION OUTPUT ;
    USE SIGNAL ;
    SHAPE ABUTMENT ;
    PORT
      LAYER met2 ;
      RECT 1591.530 1335.100 1591.670 1335.520 ;
    END
  END r0_rd_out[413]
  PIN r0_rd_out[414]
    DIRECTION OUTPUT ;
    USE SIGNAL ;
    SHAPE ABUTMENT ;
    PORT
      LAYER met2 ;
      RECT 1601.650 1335.100 1601.790 1335.520 ;
    END
  END r0_rd_out[414]
  PIN r0_rd_out[415]
    DIRECTION OUTPUT ;
    USE SIGNAL ;
    SHAPE ABUTMENT ;
    PORT
      LAYER met2 ;
      RECT 1611.770 1335.100 1611.910 1335.520 ;
    END
  END r0_rd_out[415]
  PIN r0_rd_out[416]
    DIRECTION OUTPUT ;
    USE SIGNAL ;
    SHAPE ABUTMENT ;
    PORT
      LAYER met2 ;
      RECT 1621.890 1335.100 1622.030 1335.520 ;
    END
  END r0_rd_out[416]
  PIN r0_rd_out[417]
    DIRECTION OUTPUT ;
    USE SIGNAL ;
    SHAPE ABUTMENT ;
    PORT
      LAYER met2 ;
      RECT 1632.010 1335.100 1632.150 1335.520 ;
    END
  END r0_rd_out[417]
  PIN r0_rd_out[418]
    DIRECTION OUTPUT ;
    USE SIGNAL ;
    SHAPE ABUTMENT ;
    PORT
      LAYER met2 ;
      RECT 1642.130 1335.100 1642.270 1335.520 ;
    END
  END r0_rd_out[418]
  PIN r0_rd_out[419]
    DIRECTION OUTPUT ;
    USE SIGNAL ;
    SHAPE ABUTMENT ;
    PORT
      LAYER met2 ;
      RECT 1652.250 1335.100 1652.390 1335.520 ;
    END
  END r0_rd_out[419]
  PIN r0_rd_out[420]
    DIRECTION OUTPUT ;
    USE SIGNAL ;
    SHAPE ABUTMENT ;
    PORT
      LAYER met2 ;
      RECT 1662.370 1335.100 1662.510 1335.520 ;
    END
  END r0_rd_out[420]
  PIN r0_rd_out[421]
    DIRECTION OUTPUT ;
    USE SIGNAL ;
    SHAPE ABUTMENT ;
    PORT
      LAYER met2 ;
      RECT 1672.490 1335.100 1672.630 1335.520 ;
    END
  END r0_rd_out[421]
  PIN r0_rd_out[422]
    DIRECTION OUTPUT ;
    USE SIGNAL ;
    SHAPE ABUTMENT ;
    PORT
      LAYER met2 ;
      RECT 1682.610 1335.100 1682.750 1335.520 ;
    END
  END r0_rd_out[422]
  PIN r0_rd_out[423]
    DIRECTION OUTPUT ;
    USE SIGNAL ;
    SHAPE ABUTMENT ;
    PORT
      LAYER met2 ;
      RECT 1692.730 1335.100 1692.870 1335.520 ;
    END
  END r0_rd_out[423]
  PIN r0_rd_out[424]
    DIRECTION OUTPUT ;
    USE SIGNAL ;
    SHAPE ABUTMENT ;
    PORT
      LAYER met2 ;
      RECT 1702.850 1335.100 1702.990 1335.520 ;
    END
  END r0_rd_out[424]
  PIN r0_rd_out[425]
    DIRECTION OUTPUT ;
    USE SIGNAL ;
    SHAPE ABUTMENT ;
    PORT
      LAYER met2 ;
      RECT 1712.970 1335.100 1713.110 1335.520 ;
    END
  END r0_rd_out[425]
  PIN r0_rd_out[426]
    DIRECTION OUTPUT ;
    USE SIGNAL ;
    SHAPE ABUTMENT ;
    PORT
      LAYER met2 ;
      RECT 1723.090 1335.100 1723.230 1335.520 ;
    END
  END r0_rd_out[426]
  PIN r0_rd_out[427]
    DIRECTION OUTPUT ;
    USE SIGNAL ;
    SHAPE ABUTMENT ;
    PORT
      LAYER met2 ;
      RECT 1733.210 1335.100 1733.350 1335.520 ;
    END
  END r0_rd_out[427]
  PIN r0_rd_out[428]
    DIRECTION OUTPUT ;
    USE SIGNAL ;
    SHAPE ABUTMENT ;
    PORT
      LAYER met2 ;
      RECT 1743.330 1335.100 1743.470 1335.520 ;
    END
  END r0_rd_out[428]
  PIN r0_rd_out[429]
    DIRECTION OUTPUT ;
    USE SIGNAL ;
    SHAPE ABUTMENT ;
    PORT
      LAYER met2 ;
      RECT 1753.450 1335.100 1753.590 1335.520 ;
    END
  END r0_rd_out[429]
  PIN r0_rd_out[430]
    DIRECTION OUTPUT ;
    USE SIGNAL ;
    SHAPE ABUTMENT ;
    PORT
      LAYER met2 ;
      RECT 1763.570 1335.100 1763.710 1335.520 ;
    END
  END r0_rd_out[430]
  PIN r0_rd_out[431]
    DIRECTION OUTPUT ;
    USE SIGNAL ;
    SHAPE ABUTMENT ;
    PORT
      LAYER met2 ;
      RECT 1773.690 1335.100 1773.830 1335.520 ;
    END
  END r0_rd_out[431]
  PIN r0_rd_out[432]
    DIRECTION OUTPUT ;
    USE SIGNAL ;
    SHAPE ABUTMENT ;
    PORT
      LAYER met2 ;
      RECT 1783.810 1335.100 1783.950 1335.520 ;
    END
  END r0_rd_out[432]
  PIN r0_rd_out[433]
    DIRECTION OUTPUT ;
    USE SIGNAL ;
    SHAPE ABUTMENT ;
    PORT
      LAYER met2 ;
      RECT 1793.930 1335.100 1794.070 1335.520 ;
    END
  END r0_rd_out[433]
  PIN r0_rd_out[434]
    DIRECTION OUTPUT ;
    USE SIGNAL ;
    SHAPE ABUTMENT ;
    PORT
      LAYER met2 ;
      RECT 1804.050 1335.100 1804.190 1335.520 ;
    END
  END r0_rd_out[434]
  PIN r0_rd_out[435]
    DIRECTION OUTPUT ;
    USE SIGNAL ;
    SHAPE ABUTMENT ;
    PORT
      LAYER met2 ;
      RECT 1814.170 1335.100 1814.310 1335.520 ;
    END
  END r0_rd_out[435]
  PIN r0_rd_out[436]
    DIRECTION OUTPUT ;
    USE SIGNAL ;
    SHAPE ABUTMENT ;
    PORT
      LAYER met2 ;
      RECT 1824.290 1335.100 1824.430 1335.520 ;
    END
  END r0_rd_out[436]
  PIN r0_rd_out[437]
    DIRECTION OUTPUT ;
    USE SIGNAL ;
    SHAPE ABUTMENT ;
    PORT
      LAYER met2 ;
      RECT 1834.410 1335.100 1834.550 1335.520 ;
    END
  END r0_rd_out[437]
  PIN r0_rd_out[438]
    DIRECTION OUTPUT ;
    USE SIGNAL ;
    SHAPE ABUTMENT ;
    PORT
      LAYER met2 ;
      RECT 1844.530 1335.100 1844.670 1335.520 ;
    END
  END r0_rd_out[438]
  PIN r0_rd_out[439]
    DIRECTION OUTPUT ;
    USE SIGNAL ;
    SHAPE ABUTMENT ;
    PORT
      LAYER met2 ;
      RECT 1854.650 1335.100 1854.790 1335.520 ;
    END
  END r0_rd_out[439]
  PIN r0_rd_out[440]
    DIRECTION OUTPUT ;
    USE SIGNAL ;
    SHAPE ABUTMENT ;
    PORT
      LAYER met2 ;
      RECT 1864.770 1335.100 1864.910 1335.520 ;
    END
  END r0_rd_out[440]
  PIN r0_rd_out[441]
    DIRECTION OUTPUT ;
    USE SIGNAL ;
    SHAPE ABUTMENT ;
    PORT
      LAYER met2 ;
      RECT 1874.890 1335.100 1875.030 1335.520 ;
    END
  END r0_rd_out[441]
  PIN r0_rd_out[442]
    DIRECTION OUTPUT ;
    USE SIGNAL ;
    SHAPE ABUTMENT ;
    PORT
      LAYER met2 ;
      RECT 1885.010 1335.100 1885.150 1335.520 ;
    END
  END r0_rd_out[442]
  PIN r0_rd_out[443]
    DIRECTION OUTPUT ;
    USE SIGNAL ;
    SHAPE ABUTMENT ;
    PORT
      LAYER met2 ;
      RECT 1895.130 1335.100 1895.270 1335.520 ;
    END
  END r0_rd_out[443]
  PIN r0_rd_out[444]
    DIRECTION OUTPUT ;
    USE SIGNAL ;
    SHAPE ABUTMENT ;
    PORT
      LAYER met2 ;
      RECT 1905.250 1335.100 1905.390 1335.520 ;
    END
  END r0_rd_out[444]
  PIN r0_rd_out[445]
    DIRECTION OUTPUT ;
    USE SIGNAL ;
    SHAPE ABUTMENT ;
    PORT
      LAYER met2 ;
      RECT 1915.370 1335.100 1915.510 1335.520 ;
    END
  END r0_rd_out[445]
  PIN r0_rd_out[446]
    DIRECTION OUTPUT ;
    USE SIGNAL ;
    SHAPE ABUTMENT ;
    PORT
      LAYER met2 ;
      RECT 1925.490 1335.100 1925.630 1335.520 ;
    END
  END r0_rd_out[446]
  PIN r0_rd_out[447]
    DIRECTION OUTPUT ;
    USE SIGNAL ;
    SHAPE ABUTMENT ;
    PORT
      LAYER met2 ;
      RECT 1935.610 1335.100 1935.750 1335.520 ;
    END
  END r0_rd_out[447]
  PIN r0_rd_out[448]
    DIRECTION OUTPUT ;
    USE SIGNAL ;
    SHAPE ABUTMENT ;
    PORT
      LAYER met2 ;
      RECT 1945.730 1335.100 1945.870 1335.520 ;
    END
  END r0_rd_out[448]
  PIN r0_rd_out[449]
    DIRECTION OUTPUT ;
    USE SIGNAL ;
    SHAPE ABUTMENT ;
    PORT
      LAYER met2 ;
      RECT 1955.850 1335.100 1955.990 1335.520 ;
    END
  END r0_rd_out[449]
  PIN r0_rd_out[450]
    DIRECTION OUTPUT ;
    USE SIGNAL ;
    SHAPE ABUTMENT ;
    PORT
      LAYER met2 ;
      RECT 1965.970 1335.100 1966.110 1335.520 ;
    END
  END r0_rd_out[450]
  PIN r0_rd_out[451]
    DIRECTION OUTPUT ;
    USE SIGNAL ;
    SHAPE ABUTMENT ;
    PORT
      LAYER met2 ;
      RECT 1976.090 1335.100 1976.230 1335.520 ;
    END
  END r0_rd_out[451]
  PIN r0_rd_out[452]
    DIRECTION OUTPUT ;
    USE SIGNAL ;
    SHAPE ABUTMENT ;
    PORT
      LAYER met2 ;
      RECT 1986.210 1335.100 1986.350 1335.520 ;
    END
  END r0_rd_out[452]
  PIN r0_rd_out[453]
    DIRECTION OUTPUT ;
    USE SIGNAL ;
    SHAPE ABUTMENT ;
    PORT
      LAYER met2 ;
      RECT 1996.330 1335.100 1996.470 1335.520 ;
    END
  END r0_rd_out[453]
  PIN r0_rd_out[454]
    DIRECTION OUTPUT ;
    USE SIGNAL ;
    SHAPE ABUTMENT ;
    PORT
      LAYER met2 ;
      RECT 2006.450 1335.100 2006.590 1335.520 ;
    END
  END r0_rd_out[454]
  PIN r0_rd_out[455]
    DIRECTION OUTPUT ;
    USE SIGNAL ;
    SHAPE ABUTMENT ;
    PORT
      LAYER met2 ;
      RECT 2016.570 1335.100 2016.710 1335.520 ;
    END
  END r0_rd_out[455]
  PIN r0_rd_out[456]
    DIRECTION OUTPUT ;
    USE SIGNAL ;
    SHAPE ABUTMENT ;
    PORT
      LAYER met2 ;
      RECT 2026.690 1335.100 2026.830 1335.520 ;
    END
  END r0_rd_out[456]
  PIN r0_rd_out[457]
    DIRECTION OUTPUT ;
    USE SIGNAL ;
    SHAPE ABUTMENT ;
    PORT
      LAYER met2 ;
      RECT 2036.810 1335.100 2036.950 1335.520 ;
    END
  END r0_rd_out[457]
  PIN r0_rd_out[458]
    DIRECTION OUTPUT ;
    USE SIGNAL ;
    SHAPE ABUTMENT ;
    PORT
      LAYER met2 ;
      RECT 2046.930 1335.100 2047.070 1335.520 ;
    END
  END r0_rd_out[458]
  PIN r0_rd_out[459]
    DIRECTION OUTPUT ;
    USE SIGNAL ;
    SHAPE ABUTMENT ;
    PORT
      LAYER met2 ;
      RECT 2057.050 1335.100 2057.190 1335.520 ;
    END
  END r0_rd_out[459]
  PIN r0_rd_out[460]
    DIRECTION OUTPUT ;
    USE SIGNAL ;
    SHAPE ABUTMENT ;
    PORT
      LAYER met2 ;
      RECT 2067.170 1335.100 2067.310 1335.520 ;
    END
  END r0_rd_out[460]
  PIN r0_rd_out[461]
    DIRECTION OUTPUT ;
    USE SIGNAL ;
    SHAPE ABUTMENT ;
    PORT
      LAYER met2 ;
      RECT 2077.290 1335.100 2077.430 1335.520 ;
    END
  END r0_rd_out[461]
  PIN r0_rd_out[462]
    DIRECTION OUTPUT ;
    USE SIGNAL ;
    SHAPE ABUTMENT ;
    PORT
      LAYER met2 ;
      RECT 2087.410 1335.100 2087.550 1335.520 ;
    END
  END r0_rd_out[462]
  PIN r0_rd_out[463]
    DIRECTION OUTPUT ;
    USE SIGNAL ;
    SHAPE ABUTMENT ;
    PORT
      LAYER met2 ;
      RECT 2097.530 1335.100 2097.670 1335.520 ;
    END
  END r0_rd_out[463]
  PIN r0_rd_out[464]
    DIRECTION OUTPUT ;
    USE SIGNAL ;
    SHAPE ABUTMENT ;
    PORT
      LAYER met2 ;
      RECT 2107.650 1335.100 2107.790 1335.520 ;
    END
  END r0_rd_out[464]
  PIN r0_rd_out[465]
    DIRECTION OUTPUT ;
    USE SIGNAL ;
    SHAPE ABUTMENT ;
    PORT
      LAYER met2 ;
      RECT 2117.770 1335.100 2117.910 1335.520 ;
    END
  END r0_rd_out[465]
  PIN r0_rd_out[466]
    DIRECTION OUTPUT ;
    USE SIGNAL ;
    SHAPE ABUTMENT ;
    PORT
      LAYER met2 ;
      RECT 2127.890 1335.100 2128.030 1335.520 ;
    END
  END r0_rd_out[466]
  PIN r0_rd_out[467]
    DIRECTION OUTPUT ;
    USE SIGNAL ;
    SHAPE ABUTMENT ;
    PORT
      LAYER met2 ;
      RECT 2138.010 1335.100 2138.150 1335.520 ;
    END
  END r0_rd_out[467]
  PIN r0_rd_out[468]
    DIRECTION OUTPUT ;
    USE SIGNAL ;
    SHAPE ABUTMENT ;
    PORT
      LAYER met2 ;
      RECT 2148.130 1335.100 2148.270 1335.520 ;
    END
  END r0_rd_out[468]
  PIN r0_rd_out[469]
    DIRECTION OUTPUT ;
    USE SIGNAL ;
    SHAPE ABUTMENT ;
    PORT
      LAYER met2 ;
      RECT 2158.250 1335.100 2158.390 1335.520 ;
    END
  END r0_rd_out[469]
  PIN r0_rd_out[470]
    DIRECTION OUTPUT ;
    USE SIGNAL ;
    SHAPE ABUTMENT ;
    PORT
      LAYER met2 ;
      RECT 2168.370 1335.100 2168.510 1335.520 ;
    END
  END r0_rd_out[470]
  PIN r0_rd_out[471]
    DIRECTION OUTPUT ;
    USE SIGNAL ;
    SHAPE ABUTMENT ;
    PORT
      LAYER met2 ;
      RECT 2178.490 1335.100 2178.630 1335.520 ;
    END
  END r0_rd_out[471]
  PIN r0_rd_out[472]
    DIRECTION OUTPUT ;
    USE SIGNAL ;
    SHAPE ABUTMENT ;
    PORT
      LAYER met2 ;
      RECT 2188.610 1335.100 2188.750 1335.520 ;
    END
  END r0_rd_out[472]
  PIN r0_rd_out[473]
    DIRECTION OUTPUT ;
    USE SIGNAL ;
    SHAPE ABUTMENT ;
    PORT
      LAYER met2 ;
      RECT 2198.730 1335.100 2198.870 1335.520 ;
    END
  END r0_rd_out[473]
  PIN r0_rd_out[474]
    DIRECTION OUTPUT ;
    USE SIGNAL ;
    SHAPE ABUTMENT ;
    PORT
      LAYER met2 ;
      RECT 2208.850 1335.100 2208.990 1335.520 ;
    END
  END r0_rd_out[474]
  PIN r0_rd_out[475]
    DIRECTION OUTPUT ;
    USE SIGNAL ;
    SHAPE ABUTMENT ;
    PORT
      LAYER met2 ;
      RECT 2218.970 1335.100 2219.110 1335.520 ;
    END
  END r0_rd_out[475]
  PIN r0_rd_out[476]
    DIRECTION OUTPUT ;
    USE SIGNAL ;
    SHAPE ABUTMENT ;
    PORT
      LAYER met2 ;
      RECT 2229.090 1335.100 2229.230 1335.520 ;
    END
  END r0_rd_out[476]
  PIN r0_rd_out[477]
    DIRECTION OUTPUT ;
    USE SIGNAL ;
    SHAPE ABUTMENT ;
    PORT
      LAYER met2 ;
      RECT 2239.210 1335.100 2239.350 1335.520 ;
    END
  END r0_rd_out[477]
  PIN r0_rd_out[478]
    DIRECTION OUTPUT ;
    USE SIGNAL ;
    SHAPE ABUTMENT ;
    PORT
      LAYER met2 ;
      RECT 2249.330 1335.100 2249.470 1335.520 ;
    END
  END r0_rd_out[478]
  PIN r0_rd_out[479]
    DIRECTION OUTPUT ;
    USE SIGNAL ;
    SHAPE ABUTMENT ;
    PORT
      LAYER met2 ;
      RECT 2259.450 1335.100 2259.590 1335.520 ;
    END
  END r0_rd_out[479]
  PIN r0_rd_out[480]
    DIRECTION OUTPUT ;
    USE SIGNAL ;
    SHAPE ABUTMENT ;
    PORT
      LAYER met2 ;
      RECT 2269.570 1335.100 2269.710 1335.520 ;
    END
  END r0_rd_out[480]
  PIN r0_rd_out[481]
    DIRECTION OUTPUT ;
    USE SIGNAL ;
    SHAPE ABUTMENT ;
    PORT
      LAYER met2 ;
      RECT 2279.690 1335.100 2279.830 1335.520 ;
    END
  END r0_rd_out[481]
  PIN r0_rd_out[482]
    DIRECTION OUTPUT ;
    USE SIGNAL ;
    SHAPE ABUTMENT ;
    PORT
      LAYER met2 ;
      RECT 2289.810 1335.100 2289.950 1335.520 ;
    END
  END r0_rd_out[482]
  PIN r0_rd_out[483]
    DIRECTION OUTPUT ;
    USE SIGNAL ;
    SHAPE ABUTMENT ;
    PORT
      LAYER met2 ;
      RECT 2299.930 1335.100 2300.070 1335.520 ;
    END
  END r0_rd_out[483]
  PIN r0_rd_out[484]
    DIRECTION OUTPUT ;
    USE SIGNAL ;
    SHAPE ABUTMENT ;
    PORT
      LAYER met2 ;
      RECT 2310.050 1335.100 2310.190 1335.520 ;
    END
  END r0_rd_out[484]
  PIN r0_rd_out[485]
    DIRECTION OUTPUT ;
    USE SIGNAL ;
    SHAPE ABUTMENT ;
    PORT
      LAYER met2 ;
      RECT 2320.170 1335.100 2320.310 1335.520 ;
    END
  END r0_rd_out[485]
  PIN r0_rd_out[486]
    DIRECTION OUTPUT ;
    USE SIGNAL ;
    SHAPE ABUTMENT ;
    PORT
      LAYER met2 ;
      RECT 2330.290 1335.100 2330.430 1335.520 ;
    END
  END r0_rd_out[486]
  PIN r0_rd_out[487]
    DIRECTION OUTPUT ;
    USE SIGNAL ;
    SHAPE ABUTMENT ;
    PORT
      LAYER met2 ;
      RECT 2340.410 1335.100 2340.550 1335.520 ;
    END
  END r0_rd_out[487]
  PIN r0_rd_out[488]
    DIRECTION OUTPUT ;
    USE SIGNAL ;
    SHAPE ABUTMENT ;
    PORT
      LAYER met2 ;
      RECT 2350.530 1335.100 2350.670 1335.520 ;
    END
  END r0_rd_out[488]
  PIN r0_rd_out[489]
    DIRECTION OUTPUT ;
    USE SIGNAL ;
    SHAPE ABUTMENT ;
    PORT
      LAYER met2 ;
      RECT 2360.650 1335.100 2360.790 1335.520 ;
    END
  END r0_rd_out[489]
  PIN r0_rd_out[490]
    DIRECTION OUTPUT ;
    USE SIGNAL ;
    SHAPE ABUTMENT ;
    PORT
      LAYER met2 ;
      RECT 2370.770 1335.100 2370.910 1335.520 ;
    END
  END r0_rd_out[490]
  PIN r0_rd_out[491]
    DIRECTION OUTPUT ;
    USE SIGNAL ;
    SHAPE ABUTMENT ;
    PORT
      LAYER met2 ;
      RECT 2380.890 1335.100 2381.030 1335.520 ;
    END
  END r0_rd_out[491]
  PIN r0_rd_out[492]
    DIRECTION OUTPUT ;
    USE SIGNAL ;
    SHAPE ABUTMENT ;
    PORT
      LAYER met2 ;
      RECT 2391.010 1335.100 2391.150 1335.520 ;
    END
  END r0_rd_out[492]
  PIN r0_rd_out[493]
    DIRECTION OUTPUT ;
    USE SIGNAL ;
    SHAPE ABUTMENT ;
    PORT
      LAYER met2 ;
      RECT 2401.130 1335.100 2401.270 1335.520 ;
    END
  END r0_rd_out[493]
  PIN r0_rd_out[494]
    DIRECTION OUTPUT ;
    USE SIGNAL ;
    SHAPE ABUTMENT ;
    PORT
      LAYER met2 ;
      RECT 2411.250 1335.100 2411.390 1335.520 ;
    END
  END r0_rd_out[494]
  PIN r0_rd_out[495]
    DIRECTION OUTPUT ;
    USE SIGNAL ;
    SHAPE ABUTMENT ;
    PORT
      LAYER met2 ;
      RECT 2421.370 1335.100 2421.510 1335.520 ;
    END
  END r0_rd_out[495]
  PIN r0_rd_out[496]
    DIRECTION OUTPUT ;
    USE SIGNAL ;
    SHAPE ABUTMENT ;
    PORT
      LAYER met2 ;
      RECT 2431.490 1335.100 2431.630 1335.520 ;
    END
  END r0_rd_out[496]
  PIN r0_rd_out[497]
    DIRECTION OUTPUT ;
    USE SIGNAL ;
    SHAPE ABUTMENT ;
    PORT
      LAYER met2 ;
      RECT 2441.610 1335.100 2441.750 1335.520 ;
    END
  END r0_rd_out[497]
  PIN r0_rd_out[498]
    DIRECTION OUTPUT ;
    USE SIGNAL ;
    SHAPE ABUTMENT ;
    PORT
      LAYER met2 ;
      RECT 2451.730 1335.100 2451.870 1335.520 ;
    END
  END r0_rd_out[498]
  PIN r0_rd_out[499]
    DIRECTION OUTPUT ;
    USE SIGNAL ;
    SHAPE ABUTMENT ;
    PORT
      LAYER met2 ;
      RECT 2461.850 1335.100 2461.990 1335.520 ;
    END
  END r0_rd_out[499]
  PIN r0_rd_out[500]
    DIRECTION OUTPUT ;
    USE SIGNAL ;
    SHAPE ABUTMENT ;
    PORT
      LAYER met2 ;
      RECT 2471.970 1335.100 2472.110 1335.520 ;
    END
  END r0_rd_out[500]
  PIN r0_rd_out[501]
    DIRECTION OUTPUT ;
    USE SIGNAL ;
    SHAPE ABUTMENT ;
    PORT
      LAYER met2 ;
      RECT 2482.090 1335.100 2482.230 1335.520 ;
    END
  END r0_rd_out[501]
  PIN r0_rd_out[502]
    DIRECTION OUTPUT ;
    USE SIGNAL ;
    SHAPE ABUTMENT ;
    PORT
      LAYER met2 ;
      RECT 2492.210 1335.100 2492.350 1335.520 ;
    END
  END r0_rd_out[502]
  PIN r0_rd_out[503]
    DIRECTION OUTPUT ;
    USE SIGNAL ;
    SHAPE ABUTMENT ;
    PORT
      LAYER met2 ;
      RECT 2502.330 1335.100 2502.470 1335.520 ;
    END
  END r0_rd_out[503]
  PIN r0_rd_out[504]
    DIRECTION OUTPUT ;
    USE SIGNAL ;
    SHAPE ABUTMENT ;
    PORT
      LAYER met2 ;
      RECT 2512.450 1335.100 2512.590 1335.520 ;
    END
  END r0_rd_out[504]
  PIN r0_rd_out[505]
    DIRECTION OUTPUT ;
    USE SIGNAL ;
    SHAPE ABUTMENT ;
    PORT
      LAYER met2 ;
      RECT 2522.570 1335.100 2522.710 1335.520 ;
    END
  END r0_rd_out[505]
  PIN r0_rd_out[506]
    DIRECTION OUTPUT ;
    USE SIGNAL ;
    SHAPE ABUTMENT ;
    PORT
      LAYER met2 ;
      RECT 2532.690 1335.100 2532.830 1335.520 ;
    END
  END r0_rd_out[506]
  PIN r0_rd_out[507]
    DIRECTION OUTPUT ;
    USE SIGNAL ;
    SHAPE ABUTMENT ;
    PORT
      LAYER met2 ;
      RECT 2542.810 1335.100 2542.950 1335.520 ;
    END
  END r0_rd_out[507]
  PIN r0_rd_out[508]
    DIRECTION OUTPUT ;
    USE SIGNAL ;
    SHAPE ABUTMENT ;
    PORT
      LAYER met2 ;
      RECT 2552.930 1335.100 2553.070 1335.520 ;
    END
  END r0_rd_out[508]
  PIN r0_rd_out[509]
    DIRECTION OUTPUT ;
    USE SIGNAL ;
    SHAPE ABUTMENT ;
    PORT
      LAYER met2 ;
      RECT 2563.050 1335.100 2563.190 1335.520 ;
    END
  END r0_rd_out[509]
  PIN r0_rd_out[510]
    DIRECTION OUTPUT ;
    USE SIGNAL ;
    SHAPE ABUTMENT ;
    PORT
      LAYER met2 ;
      RECT 2573.170 1335.100 2573.310 1335.520 ;
    END
  END r0_rd_out[510]
  PIN r0_rd_out[511]
    DIRECTION OUTPUT ;
    USE SIGNAL ;
    SHAPE ABUTMENT ;
    PORT
      LAYER met2 ;
      RECT 2583.290 1335.100 2583.430 1335.520 ;
    END
  END r0_rd_out[511]
  PIN w0_addr_in[0]
    DIRECTION INPUT ;
    USE SIGNAL ;
    SHAPE ABUTMENT ;
    PORT
      LAYER met3 ;
      RECT 0.000 1222.490 0.900 1222.790 ;
    END
  END w0_addr_in[0]
  PIN w0_addr_in[1]
    DIRECTION INPUT ;
    USE SIGNAL ;
    SHAPE ABUTMENT ;
    PORT
      LAYER met3 ;
      RECT 0.000 1232.010 0.900 1232.310 ;
    END
  END w0_addr_in[1]
  PIN w0_addr_in[2]
    DIRECTION INPUT ;
    USE SIGNAL ;
    SHAPE ABUTMENT ;
    PORT
      LAYER met3 ;
      RECT 0.000 1241.530 0.900 1241.830 ;
    END
  END w0_addr_in[2]
  PIN w0_addr_in[3]
    DIRECTION INPUT ;
    USE SIGNAL ;
    SHAPE ABUTMENT ;
    PORT
      LAYER met3 ;
      RECT 0.000 1251.050 0.900 1251.350 ;
    END
  END w0_addr_in[3]
  PIN w0_addr_in[4]
    DIRECTION INPUT ;
    USE SIGNAL ;
    SHAPE ABUTMENT ;
    PORT
      LAYER met3 ;
      RECT 0.000 1260.570 0.900 1260.870 ;
    END
  END w0_addr_in[4]
  PIN w0_addr_in[5]
    DIRECTION INPUT ;
    USE SIGNAL ;
    SHAPE ABUTMENT ;
    PORT
      LAYER met3 ;
      RECT 2657.440 1222.490 2658.340 1222.790 ;
    END
  END w0_addr_in[5]
  PIN w0_addr_in[6]
    DIRECTION INPUT ;
    USE SIGNAL ;
    SHAPE ABUTMENT ;
    PORT
      LAYER met3 ;
      RECT 2657.440 1232.010 2658.340 1232.310 ;
    END
  END w0_addr_in[6]
  PIN w0_addr_in[7]
    DIRECTION INPUT ;
    USE SIGNAL ;
    SHAPE ABUTMENT ;
    PORT
      LAYER met3 ;
      RECT 2657.440 1241.530 2658.340 1241.830 ;
    END
  END w0_addr_in[7]
  PIN w0_addr_in[8]
    DIRECTION INPUT ;
    USE SIGNAL ;
    SHAPE ABUTMENT ;
    PORT
      LAYER met3 ;
      RECT 2657.440 1251.050 2658.340 1251.350 ;
    END
  END w0_addr_in[8]
  PIN r0_addr_in[0]
    DIRECTION INPUT ;
    USE SIGNAL ;
    SHAPE ABUTMENT ;
    PORT
      LAYER met3 ;
      RECT 0.000 1270.090 0.900 1270.390 ;
    END
  END r0_addr_in[0]
  PIN r0_addr_in[1]
    DIRECTION INPUT ;
    USE SIGNAL ;
    SHAPE ABUTMENT ;
    PORT
      LAYER met3 ;
      RECT 0.000 1279.610 0.900 1279.910 ;
    END
  END r0_addr_in[1]
  PIN r0_addr_in[2]
    DIRECTION INPUT ;
    USE SIGNAL ;
    SHAPE ABUTMENT ;
    PORT
      LAYER met3 ;
      RECT 0.000 1289.130 0.900 1289.430 ;
    END
  END r0_addr_in[2]
  PIN r0_addr_in[3]
    DIRECTION INPUT ;
    USE SIGNAL ;
    SHAPE ABUTMENT ;
    PORT
      LAYER met3 ;
      RECT 0.000 1298.650 0.900 1298.950 ;
    END
  END r0_addr_in[3]
  PIN r0_addr_in[4]
    DIRECTION INPUT ;
    USE SIGNAL ;
    SHAPE ABUTMENT ;
    PORT
      LAYER met3 ;
      RECT 0.000 1308.170 0.900 1308.470 ;
    END
  END r0_addr_in[4]
  PIN r0_addr_in[5]
    DIRECTION INPUT ;
    USE SIGNAL ;
    SHAPE ABUTMENT ;
    PORT
      LAYER met3 ;
      RECT 2657.440 1260.570 2658.340 1260.870 ;
    END
  END r0_addr_in[5]
  PIN r0_addr_in[6]
    DIRECTION INPUT ;
    USE SIGNAL ;
    SHAPE ABUTMENT ;
    PORT
      LAYER met3 ;
      RECT 2657.440 1270.090 2658.340 1270.390 ;
    END
  END r0_addr_in[6]
  PIN r0_addr_in[7]
    DIRECTION INPUT ;
    USE SIGNAL ;
    SHAPE ABUTMENT ;
    PORT
      LAYER met3 ;
      RECT 2657.440 1279.610 2658.340 1279.910 ;
    END
  END r0_addr_in[7]
  PIN r0_addr_in[8]
    DIRECTION INPUT ;
    USE SIGNAL ;
    SHAPE ABUTMENT ;
    PORT
      LAYER met3 ;
      RECT 2657.440 1289.130 2658.340 1289.430 ;
    END
  END r0_addr_in[8]
  PIN w0_we_in
    DIRECTION INPUT ;
    USE SIGNAL ;
    SHAPE ABUTMENT ;
    PORT
      LAYER met2 ;
      RECT 2593.410 1335.100 2593.550 1335.520 ;
    END
  END w0_we_in
  PIN w0_ce_in
    DIRECTION INPUT ;
    USE SIGNAL ;
    SHAPE ABUTMENT ;
    PORT
      LAYER met2 ;
      RECT 2603.530 1335.100 2603.670 1335.520 ;
    END
  END w0_ce_in
  PIN w0_clk
    DIRECTION INPUT ;
    USE SIGNAL ;
    SHAPE ABUTMENT ;
    PORT
      LAYER met2 ;
      RECT 2613.650 1335.100 2613.790 1335.520 ;
    END
  END w0_clk
  PIN r0_ce_in
    DIRECTION INPUT ;
    USE SIGNAL ;
    SHAPE ABUTMENT ;
    PORT
      LAYER met2 ;
      RECT 2623.770 1335.100 2623.910 1335.520 ;
    END
  END r0_ce_in
  PIN r0_clk
    DIRECTION INPUT ;
    USE SIGNAL ;
    SHAPE ABUTMENT ;
    PORT
      LAYER met2 ;
      RECT 2633.890 1335.100 2634.030 1335.520 ;
    END
  END r0_clk
  PIN VSS
    DIRECTION INOUT ;
    USE GROUND ;
    PORT
      LAYER met4 ;
      RECT 2.160 4.080 3.360 1331.440 ;
      RECT 13.040 4.080 14.240 1331.440 ;
      RECT 23.920 4.080 25.120 1331.440 ;
      RECT 34.800 4.080 36.000 1331.440 ;
      RECT 45.680 4.080 46.880 1331.440 ;
      RECT 56.560 4.080 57.760 1331.440 ;
      RECT 67.440 4.080 68.640 1331.440 ;
      RECT 78.320 4.080 79.520 1331.440 ;
      RECT 89.200 4.080 90.400 1331.440 ;
      RECT 100.080 4.080 101.280 1331.440 ;
      RECT 110.960 4.080 112.160 1331.440 ;
      RECT 121.840 4.080 123.040 1331.440 ;
      RECT 132.720 4.080 133.920 1331.440 ;
      RECT 143.600 4.080 144.800 1331.440 ;
      RECT 154.480 4.080 155.680 1331.440 ;
      RECT 165.360 4.080 166.560 1331.440 ;
      RECT 176.240 4.080 177.440 1331.440 ;
      RECT 187.120 4.080 188.320 1331.440 ;
      RECT 198.000 4.080 199.200 1331.440 ;
      RECT 208.880 4.080 210.080 1331.440 ;
      RECT 219.760 4.080 220.960 1331.440 ;
      RECT 230.640 4.080 231.840 1331.440 ;
      RECT 241.520 4.080 242.720 1331.440 ;
      RECT 252.400 4.080 253.600 1331.440 ;
      RECT 263.280 4.080 264.480 1331.440 ;
      RECT 274.160 4.080 275.360 1331.440 ;
      RECT 285.040 4.080 286.240 1331.440 ;
      RECT 295.920 4.080 297.120 1331.440 ;
      RECT 306.800 4.080 308.000 1331.440 ;
      RECT 317.680 4.080 318.880 1331.440 ;
      RECT 328.560 4.080 329.760 1331.440 ;
      RECT 339.440 4.080 340.640 1331.440 ;
      RECT 350.320 4.080 351.520 1331.440 ;
      RECT 361.200 4.080 362.400 1331.440 ;
      RECT 372.080 4.080 373.280 1331.440 ;
      RECT 382.960 4.080 384.160 1331.440 ;
      RECT 393.840 4.080 395.040 1331.440 ;
      RECT 404.720 4.080 405.920 1331.440 ;
      RECT 415.600 4.080 416.800 1331.440 ;
      RECT 426.480 4.080 427.680 1331.440 ;
      RECT 437.360 4.080 438.560 1331.440 ;
      RECT 448.240 4.080 449.440 1331.440 ;
      RECT 459.120 4.080 460.320 1331.440 ;
      RECT 470.000 4.080 471.200 1331.440 ;
      RECT 480.880 4.080 482.080 1331.440 ;
      RECT 491.760 4.080 492.960 1331.440 ;
      RECT 502.640 4.080 503.840 1331.440 ;
      RECT 513.520 4.080 514.720 1331.440 ;
      RECT 524.400 4.080 525.600 1331.440 ;
      RECT 535.280 4.080 536.480 1331.440 ;
      RECT 546.160 4.080 547.360 1331.440 ;
      RECT 557.040 4.080 558.240 1331.440 ;
      RECT 567.920 4.080 569.120 1331.440 ;
      RECT 578.800 4.080 580.000 1331.440 ;
      RECT 589.680 4.080 590.880 1331.440 ;
      RECT 600.560 4.080 601.760 1331.440 ;
      RECT 611.440 4.080 612.640 1331.440 ;
      RECT 622.320 4.080 623.520 1331.440 ;
      RECT 633.200 4.080 634.400 1331.440 ;
      RECT 644.080 4.080 645.280 1331.440 ;
      RECT 654.960 4.080 656.160 1331.440 ;
      RECT 665.840 4.080 667.040 1331.440 ;
      RECT 676.720 4.080 677.920 1331.440 ;
      RECT 687.600 4.080 688.800 1331.440 ;
      RECT 698.480 4.080 699.680 1331.440 ;
      RECT 709.360 4.080 710.560 1331.440 ;
      RECT 720.240 4.080 721.440 1331.440 ;
      RECT 731.120 4.080 732.320 1331.440 ;
      RECT 742.000 4.080 743.200 1331.440 ;
      RECT 752.880 4.080 754.080 1331.440 ;
      RECT 763.760 4.080 764.960 1331.440 ;
      RECT 774.640 4.080 775.840 1331.440 ;
      RECT 785.520 4.080 786.720 1331.440 ;
      RECT 796.400 4.080 797.600 1331.440 ;
      RECT 807.280 4.080 808.480 1331.440 ;
      RECT 818.160 4.080 819.360 1331.440 ;
      RECT 829.040 4.080 830.240 1331.440 ;
      RECT 839.920 4.080 841.120 1331.440 ;
      RECT 850.800 4.080 852.000 1331.440 ;
      RECT 861.680 4.080 862.880 1331.440 ;
      RECT 872.560 4.080 873.760 1331.440 ;
      RECT 883.440 4.080 884.640 1331.440 ;
      RECT 894.320 4.080 895.520 1331.440 ;
      RECT 905.200 4.080 906.400 1331.440 ;
      RECT 916.080 4.080 917.280 1331.440 ;
      RECT 926.960 4.080 928.160 1331.440 ;
      RECT 937.840 4.080 939.040 1331.440 ;
      RECT 948.720 4.080 949.920 1331.440 ;
      RECT 959.600 4.080 960.800 1331.440 ;
      RECT 970.480 4.080 971.680 1331.440 ;
      RECT 981.360 4.080 982.560 1331.440 ;
      RECT 992.240 4.080 993.440 1331.440 ;
      RECT 1003.120 4.080 1004.320 1331.440 ;
      RECT 1014.000 4.080 1015.200 1331.440 ;
      RECT 1024.880 4.080 1026.080 1331.440 ;
      RECT 1035.760 4.080 1036.960 1331.440 ;
      RECT 1046.640 4.080 1047.840 1331.440 ;
      RECT 1057.520 4.080 1058.720 1331.440 ;
      RECT 1068.400 4.080 1069.600 1331.440 ;
      RECT 1079.280 4.080 1080.480 1331.440 ;
      RECT 1090.160 4.080 1091.360 1331.440 ;
      RECT 1101.040 4.080 1102.240 1331.440 ;
      RECT 1111.920 4.080 1113.120 1331.440 ;
      RECT 1122.800 4.080 1124.000 1331.440 ;
      RECT 1133.680 4.080 1134.880 1331.440 ;
      RECT 1144.560 4.080 1145.760 1331.440 ;
      RECT 1155.440 4.080 1156.640 1331.440 ;
      RECT 1166.320 4.080 1167.520 1331.440 ;
      RECT 1177.200 4.080 1178.400 1331.440 ;
      RECT 1188.080 4.080 1189.280 1331.440 ;
      RECT 1198.960 4.080 1200.160 1331.440 ;
      RECT 1209.840 4.080 1211.040 1331.440 ;
      RECT 1220.720 4.080 1221.920 1331.440 ;
      RECT 1231.600 4.080 1232.800 1331.440 ;
      RECT 1242.480 4.080 1243.680 1331.440 ;
      RECT 1253.360 4.080 1254.560 1331.440 ;
      RECT 1264.240 4.080 1265.440 1331.440 ;
      RECT 1275.120 4.080 1276.320 1331.440 ;
      RECT 1286.000 4.080 1287.200 1331.440 ;
      RECT 1296.880 4.080 1298.080 1331.440 ;
      RECT 1307.760 4.080 1308.960 1331.440 ;
      RECT 1318.640 4.080 1319.840 1331.440 ;
      RECT 1329.520 4.080 1330.720 1331.440 ;
      RECT 1340.400 4.080 1341.600 1331.440 ;
      RECT 1351.280 4.080 1352.480 1331.440 ;
      RECT 1362.160 4.080 1363.360 1331.440 ;
      RECT 1373.040 4.080 1374.240 1331.440 ;
      RECT 1383.920 4.080 1385.120 1331.440 ;
      RECT 1394.800 4.080 1396.000 1331.440 ;
      RECT 1405.680 4.080 1406.880 1331.440 ;
      RECT 1416.560 4.080 1417.760 1331.440 ;
      RECT 1427.440 4.080 1428.640 1331.440 ;
      RECT 1438.320 4.080 1439.520 1331.440 ;
      RECT 1449.200 4.080 1450.400 1331.440 ;
      RECT 1460.080 4.080 1461.280 1331.440 ;
      RECT 1470.960 4.080 1472.160 1331.440 ;
      RECT 1481.840 4.080 1483.040 1331.440 ;
      RECT 1492.720 4.080 1493.920 1331.440 ;
      RECT 1503.600 4.080 1504.800 1331.440 ;
      RECT 1514.480 4.080 1515.680 1331.440 ;
      RECT 1525.360 4.080 1526.560 1331.440 ;
      RECT 1536.240 4.080 1537.440 1331.440 ;
      RECT 1547.120 4.080 1548.320 1331.440 ;
      RECT 1558.000 4.080 1559.200 1331.440 ;
      RECT 1568.880 4.080 1570.080 1331.440 ;
      RECT 1579.760 4.080 1580.960 1331.440 ;
      RECT 1590.640 4.080 1591.840 1331.440 ;
      RECT 1601.520 4.080 1602.720 1331.440 ;
      RECT 1612.400 4.080 1613.600 1331.440 ;
      RECT 1623.280 4.080 1624.480 1331.440 ;
      RECT 1634.160 4.080 1635.360 1331.440 ;
      RECT 1645.040 4.080 1646.240 1331.440 ;
      RECT 1655.920 4.080 1657.120 1331.440 ;
      RECT 1666.800 4.080 1668.000 1331.440 ;
      RECT 1677.680 4.080 1678.880 1331.440 ;
      RECT 1688.560 4.080 1689.760 1331.440 ;
      RECT 1699.440 4.080 1700.640 1331.440 ;
      RECT 1710.320 4.080 1711.520 1331.440 ;
      RECT 1721.200 4.080 1722.400 1331.440 ;
      RECT 1732.080 4.080 1733.280 1331.440 ;
      RECT 1742.960 4.080 1744.160 1331.440 ;
      RECT 1753.840 4.080 1755.040 1331.440 ;
      RECT 1764.720 4.080 1765.920 1331.440 ;
      RECT 1775.600 4.080 1776.800 1331.440 ;
      RECT 1786.480 4.080 1787.680 1331.440 ;
      RECT 1797.360 4.080 1798.560 1331.440 ;
      RECT 1808.240 4.080 1809.440 1331.440 ;
      RECT 1819.120 4.080 1820.320 1331.440 ;
      RECT 1830.000 4.080 1831.200 1331.440 ;
      RECT 1840.880 4.080 1842.080 1331.440 ;
      RECT 1851.760 4.080 1852.960 1331.440 ;
      RECT 1862.640 4.080 1863.840 1331.440 ;
      RECT 1873.520 4.080 1874.720 1331.440 ;
      RECT 1884.400 4.080 1885.600 1331.440 ;
      RECT 1895.280 4.080 1896.480 1331.440 ;
      RECT 1906.160 4.080 1907.360 1331.440 ;
      RECT 1917.040 4.080 1918.240 1331.440 ;
      RECT 1927.920 4.080 1929.120 1331.440 ;
      RECT 1938.800 4.080 1940.000 1331.440 ;
      RECT 1949.680 4.080 1950.880 1331.440 ;
      RECT 1960.560 4.080 1961.760 1331.440 ;
      RECT 1971.440 4.080 1972.640 1331.440 ;
      RECT 1982.320 4.080 1983.520 1331.440 ;
      RECT 1993.200 4.080 1994.400 1331.440 ;
      RECT 2004.080 4.080 2005.280 1331.440 ;
      RECT 2014.960 4.080 2016.160 1331.440 ;
      RECT 2025.840 4.080 2027.040 1331.440 ;
      RECT 2036.720 4.080 2037.920 1331.440 ;
      RECT 2047.600 4.080 2048.800 1331.440 ;
      RECT 2058.480 4.080 2059.680 1331.440 ;
      RECT 2069.360 4.080 2070.560 1331.440 ;
      RECT 2080.240 4.080 2081.440 1331.440 ;
      RECT 2091.120 4.080 2092.320 1331.440 ;
      RECT 2102.000 4.080 2103.200 1331.440 ;
      RECT 2112.880 4.080 2114.080 1331.440 ;
      RECT 2123.760 4.080 2124.960 1331.440 ;
      RECT 2134.640 4.080 2135.840 1331.440 ;
      RECT 2145.520 4.080 2146.720 1331.440 ;
      RECT 2156.400 4.080 2157.600 1331.440 ;
      RECT 2167.280 4.080 2168.480 1331.440 ;
      RECT 2178.160 4.080 2179.360 1331.440 ;
      RECT 2189.040 4.080 2190.240 1331.440 ;
      RECT 2199.920 4.080 2201.120 1331.440 ;
      RECT 2210.800 4.080 2212.000 1331.440 ;
      RECT 2221.680 4.080 2222.880 1331.440 ;
      RECT 2232.560 4.080 2233.760 1331.440 ;
      RECT 2243.440 4.080 2244.640 1331.440 ;
      RECT 2254.320 4.080 2255.520 1331.440 ;
      RECT 2265.200 4.080 2266.400 1331.440 ;
      RECT 2276.080 4.080 2277.280 1331.440 ;
      RECT 2286.960 4.080 2288.160 1331.440 ;
      RECT 2297.840 4.080 2299.040 1331.440 ;
      RECT 2308.720 4.080 2309.920 1331.440 ;
      RECT 2319.600 4.080 2320.800 1331.440 ;
      RECT 2330.480 4.080 2331.680 1331.440 ;
      RECT 2341.360 4.080 2342.560 1331.440 ;
      RECT 2352.240 4.080 2353.440 1331.440 ;
      RECT 2363.120 4.080 2364.320 1331.440 ;
      RECT 2374.000 4.080 2375.200 1331.440 ;
      RECT 2384.880 4.080 2386.080 1331.440 ;
      RECT 2395.760 4.080 2396.960 1331.440 ;
      RECT 2406.640 4.080 2407.840 1331.440 ;
      RECT 2417.520 4.080 2418.720 1331.440 ;
      RECT 2428.400 4.080 2429.600 1331.440 ;
      RECT 2439.280 4.080 2440.480 1331.440 ;
      RECT 2450.160 4.080 2451.360 1331.440 ;
      RECT 2461.040 4.080 2462.240 1331.440 ;
      RECT 2471.920 4.080 2473.120 1331.440 ;
      RECT 2482.800 4.080 2484.000 1331.440 ;
      RECT 2493.680 4.080 2494.880 1331.440 ;
      RECT 2504.560 4.080 2505.760 1331.440 ;
      RECT 2515.440 4.080 2516.640 1331.440 ;
      RECT 2526.320 4.080 2527.520 1331.440 ;
      RECT 2537.200 4.080 2538.400 1331.440 ;
      RECT 2548.080 4.080 2549.280 1331.440 ;
      RECT 2558.960 4.080 2560.160 1331.440 ;
      RECT 2569.840 4.080 2571.040 1331.440 ;
      RECT 2580.720 4.080 2581.920 1331.440 ;
      RECT 2591.600 4.080 2592.800 1331.440 ;
      RECT 2602.480 4.080 2603.680 1331.440 ;
      RECT 2613.360 4.080 2614.560 1331.440 ;
      RECT 2624.240 4.080 2625.440 1331.440 ;
      RECT 2635.120 4.080 2636.320 1331.440 ;
      RECT 2646.000 4.080 2647.200 1331.440 ;
      RECT 2656.880 4.080 2658.080 1331.440 ;
    END
  END VSS
  PIN VDD
    DIRECTION INOUT ;
    USE POWER ;
    PORT
      LAYER met4 ;
      RECT 2.160 4.080 3.360 1331.440 ;
      RECT 13.040 4.080 14.240 1331.440 ;
      RECT 23.920 4.080 25.120 1331.440 ;
      RECT 34.800 4.080 36.000 1331.440 ;
      RECT 45.680 4.080 46.880 1331.440 ;
      RECT 56.560 4.080 57.760 1331.440 ;
      RECT 67.440 4.080 68.640 1331.440 ;
      RECT 78.320 4.080 79.520 1331.440 ;
      RECT 89.200 4.080 90.400 1331.440 ;
      RECT 100.080 4.080 101.280 1331.440 ;
      RECT 110.960 4.080 112.160 1331.440 ;
      RECT 121.840 4.080 123.040 1331.440 ;
      RECT 132.720 4.080 133.920 1331.440 ;
      RECT 143.600 4.080 144.800 1331.440 ;
      RECT 154.480 4.080 155.680 1331.440 ;
      RECT 165.360 4.080 166.560 1331.440 ;
      RECT 176.240 4.080 177.440 1331.440 ;
      RECT 187.120 4.080 188.320 1331.440 ;
      RECT 198.000 4.080 199.200 1331.440 ;
      RECT 208.880 4.080 210.080 1331.440 ;
      RECT 219.760 4.080 220.960 1331.440 ;
      RECT 230.640 4.080 231.840 1331.440 ;
      RECT 241.520 4.080 242.720 1331.440 ;
      RECT 252.400 4.080 253.600 1331.440 ;
      RECT 263.280 4.080 264.480 1331.440 ;
      RECT 274.160 4.080 275.360 1331.440 ;
      RECT 285.040 4.080 286.240 1331.440 ;
      RECT 295.920 4.080 297.120 1331.440 ;
      RECT 306.800 4.080 308.000 1331.440 ;
      RECT 317.680 4.080 318.880 1331.440 ;
      RECT 328.560 4.080 329.760 1331.440 ;
      RECT 339.440 4.080 340.640 1331.440 ;
      RECT 350.320 4.080 351.520 1331.440 ;
      RECT 361.200 4.080 362.400 1331.440 ;
      RECT 372.080 4.080 373.280 1331.440 ;
      RECT 382.960 4.080 384.160 1331.440 ;
      RECT 393.840 4.080 395.040 1331.440 ;
      RECT 404.720 4.080 405.920 1331.440 ;
      RECT 415.600 4.080 416.800 1331.440 ;
      RECT 426.480 4.080 427.680 1331.440 ;
      RECT 437.360 4.080 438.560 1331.440 ;
      RECT 448.240 4.080 449.440 1331.440 ;
      RECT 459.120 4.080 460.320 1331.440 ;
      RECT 470.000 4.080 471.200 1331.440 ;
      RECT 480.880 4.080 482.080 1331.440 ;
      RECT 491.760 4.080 492.960 1331.440 ;
      RECT 502.640 4.080 503.840 1331.440 ;
      RECT 513.520 4.080 514.720 1331.440 ;
      RECT 524.400 4.080 525.600 1331.440 ;
      RECT 535.280 4.080 536.480 1331.440 ;
      RECT 546.160 4.080 547.360 1331.440 ;
      RECT 557.040 4.080 558.240 1331.440 ;
      RECT 567.920 4.080 569.120 1331.440 ;
      RECT 578.800 4.080 580.000 1331.440 ;
      RECT 589.680 4.080 590.880 1331.440 ;
      RECT 600.560 4.080 601.760 1331.440 ;
      RECT 611.440 4.080 612.640 1331.440 ;
      RECT 622.320 4.080 623.520 1331.440 ;
      RECT 633.200 4.080 634.400 1331.440 ;
      RECT 644.080 4.080 645.280 1331.440 ;
      RECT 654.960 4.080 656.160 1331.440 ;
      RECT 665.840 4.080 667.040 1331.440 ;
      RECT 676.720 4.080 677.920 1331.440 ;
      RECT 687.600 4.080 688.800 1331.440 ;
      RECT 698.480 4.080 699.680 1331.440 ;
      RECT 709.360 4.080 710.560 1331.440 ;
      RECT 720.240 4.080 721.440 1331.440 ;
      RECT 731.120 4.080 732.320 1331.440 ;
      RECT 742.000 4.080 743.200 1331.440 ;
      RECT 752.880 4.080 754.080 1331.440 ;
      RECT 763.760 4.080 764.960 1331.440 ;
      RECT 774.640 4.080 775.840 1331.440 ;
      RECT 785.520 4.080 786.720 1331.440 ;
      RECT 796.400 4.080 797.600 1331.440 ;
      RECT 807.280 4.080 808.480 1331.440 ;
      RECT 818.160 4.080 819.360 1331.440 ;
      RECT 829.040 4.080 830.240 1331.440 ;
      RECT 839.920 4.080 841.120 1331.440 ;
      RECT 850.800 4.080 852.000 1331.440 ;
      RECT 861.680 4.080 862.880 1331.440 ;
      RECT 872.560 4.080 873.760 1331.440 ;
      RECT 883.440 4.080 884.640 1331.440 ;
      RECT 894.320 4.080 895.520 1331.440 ;
      RECT 905.200 4.080 906.400 1331.440 ;
      RECT 916.080 4.080 917.280 1331.440 ;
      RECT 926.960 4.080 928.160 1331.440 ;
      RECT 937.840 4.080 939.040 1331.440 ;
      RECT 948.720 4.080 949.920 1331.440 ;
      RECT 959.600 4.080 960.800 1331.440 ;
      RECT 970.480 4.080 971.680 1331.440 ;
      RECT 981.360 4.080 982.560 1331.440 ;
      RECT 992.240 4.080 993.440 1331.440 ;
      RECT 1003.120 4.080 1004.320 1331.440 ;
      RECT 1014.000 4.080 1015.200 1331.440 ;
      RECT 1024.880 4.080 1026.080 1331.440 ;
      RECT 1035.760 4.080 1036.960 1331.440 ;
      RECT 1046.640 4.080 1047.840 1331.440 ;
      RECT 1057.520 4.080 1058.720 1331.440 ;
      RECT 1068.400 4.080 1069.600 1331.440 ;
      RECT 1079.280 4.080 1080.480 1331.440 ;
      RECT 1090.160 4.080 1091.360 1331.440 ;
      RECT 1101.040 4.080 1102.240 1331.440 ;
      RECT 1111.920 4.080 1113.120 1331.440 ;
      RECT 1122.800 4.080 1124.000 1331.440 ;
      RECT 1133.680 4.080 1134.880 1331.440 ;
      RECT 1144.560 4.080 1145.760 1331.440 ;
      RECT 1155.440 4.080 1156.640 1331.440 ;
      RECT 1166.320 4.080 1167.520 1331.440 ;
      RECT 1177.200 4.080 1178.400 1331.440 ;
      RECT 1188.080 4.080 1189.280 1331.440 ;
      RECT 1198.960 4.080 1200.160 1331.440 ;
      RECT 1209.840 4.080 1211.040 1331.440 ;
      RECT 1220.720 4.080 1221.920 1331.440 ;
      RECT 1231.600 4.080 1232.800 1331.440 ;
      RECT 1242.480 4.080 1243.680 1331.440 ;
      RECT 1253.360 4.080 1254.560 1331.440 ;
      RECT 1264.240 4.080 1265.440 1331.440 ;
      RECT 1275.120 4.080 1276.320 1331.440 ;
      RECT 1286.000 4.080 1287.200 1331.440 ;
      RECT 1296.880 4.080 1298.080 1331.440 ;
      RECT 1307.760 4.080 1308.960 1331.440 ;
      RECT 1318.640 4.080 1319.840 1331.440 ;
      RECT 1329.520 4.080 1330.720 1331.440 ;
      RECT 1340.400 4.080 1341.600 1331.440 ;
      RECT 1351.280 4.080 1352.480 1331.440 ;
      RECT 1362.160 4.080 1363.360 1331.440 ;
      RECT 1373.040 4.080 1374.240 1331.440 ;
      RECT 1383.920 4.080 1385.120 1331.440 ;
      RECT 1394.800 4.080 1396.000 1331.440 ;
      RECT 1405.680 4.080 1406.880 1331.440 ;
      RECT 1416.560 4.080 1417.760 1331.440 ;
      RECT 1427.440 4.080 1428.640 1331.440 ;
      RECT 1438.320 4.080 1439.520 1331.440 ;
      RECT 1449.200 4.080 1450.400 1331.440 ;
      RECT 1460.080 4.080 1461.280 1331.440 ;
      RECT 1470.960 4.080 1472.160 1331.440 ;
      RECT 1481.840 4.080 1483.040 1331.440 ;
      RECT 1492.720 4.080 1493.920 1331.440 ;
      RECT 1503.600 4.080 1504.800 1331.440 ;
      RECT 1514.480 4.080 1515.680 1331.440 ;
      RECT 1525.360 4.080 1526.560 1331.440 ;
      RECT 1536.240 4.080 1537.440 1331.440 ;
      RECT 1547.120 4.080 1548.320 1331.440 ;
      RECT 1558.000 4.080 1559.200 1331.440 ;
      RECT 1568.880 4.080 1570.080 1331.440 ;
      RECT 1579.760 4.080 1580.960 1331.440 ;
      RECT 1590.640 4.080 1591.840 1331.440 ;
      RECT 1601.520 4.080 1602.720 1331.440 ;
      RECT 1612.400 4.080 1613.600 1331.440 ;
      RECT 1623.280 4.080 1624.480 1331.440 ;
      RECT 1634.160 4.080 1635.360 1331.440 ;
      RECT 1645.040 4.080 1646.240 1331.440 ;
      RECT 1655.920 4.080 1657.120 1331.440 ;
      RECT 1666.800 4.080 1668.000 1331.440 ;
      RECT 1677.680 4.080 1678.880 1331.440 ;
      RECT 1688.560 4.080 1689.760 1331.440 ;
      RECT 1699.440 4.080 1700.640 1331.440 ;
      RECT 1710.320 4.080 1711.520 1331.440 ;
      RECT 1721.200 4.080 1722.400 1331.440 ;
      RECT 1732.080 4.080 1733.280 1331.440 ;
      RECT 1742.960 4.080 1744.160 1331.440 ;
      RECT 1753.840 4.080 1755.040 1331.440 ;
      RECT 1764.720 4.080 1765.920 1331.440 ;
      RECT 1775.600 4.080 1776.800 1331.440 ;
      RECT 1786.480 4.080 1787.680 1331.440 ;
      RECT 1797.360 4.080 1798.560 1331.440 ;
      RECT 1808.240 4.080 1809.440 1331.440 ;
      RECT 1819.120 4.080 1820.320 1331.440 ;
      RECT 1830.000 4.080 1831.200 1331.440 ;
      RECT 1840.880 4.080 1842.080 1331.440 ;
      RECT 1851.760 4.080 1852.960 1331.440 ;
      RECT 1862.640 4.080 1863.840 1331.440 ;
      RECT 1873.520 4.080 1874.720 1331.440 ;
      RECT 1884.400 4.080 1885.600 1331.440 ;
      RECT 1895.280 4.080 1896.480 1331.440 ;
      RECT 1906.160 4.080 1907.360 1331.440 ;
      RECT 1917.040 4.080 1918.240 1331.440 ;
      RECT 1927.920 4.080 1929.120 1331.440 ;
      RECT 1938.800 4.080 1940.000 1331.440 ;
      RECT 1949.680 4.080 1950.880 1331.440 ;
      RECT 1960.560 4.080 1961.760 1331.440 ;
      RECT 1971.440 4.080 1972.640 1331.440 ;
      RECT 1982.320 4.080 1983.520 1331.440 ;
      RECT 1993.200 4.080 1994.400 1331.440 ;
      RECT 2004.080 4.080 2005.280 1331.440 ;
      RECT 2014.960 4.080 2016.160 1331.440 ;
      RECT 2025.840 4.080 2027.040 1331.440 ;
      RECT 2036.720 4.080 2037.920 1331.440 ;
      RECT 2047.600 4.080 2048.800 1331.440 ;
      RECT 2058.480 4.080 2059.680 1331.440 ;
      RECT 2069.360 4.080 2070.560 1331.440 ;
      RECT 2080.240 4.080 2081.440 1331.440 ;
      RECT 2091.120 4.080 2092.320 1331.440 ;
      RECT 2102.000 4.080 2103.200 1331.440 ;
      RECT 2112.880 4.080 2114.080 1331.440 ;
      RECT 2123.760 4.080 2124.960 1331.440 ;
      RECT 2134.640 4.080 2135.840 1331.440 ;
      RECT 2145.520 4.080 2146.720 1331.440 ;
      RECT 2156.400 4.080 2157.600 1331.440 ;
      RECT 2167.280 4.080 2168.480 1331.440 ;
      RECT 2178.160 4.080 2179.360 1331.440 ;
      RECT 2189.040 4.080 2190.240 1331.440 ;
      RECT 2199.920 4.080 2201.120 1331.440 ;
      RECT 2210.800 4.080 2212.000 1331.440 ;
      RECT 2221.680 4.080 2222.880 1331.440 ;
      RECT 2232.560 4.080 2233.760 1331.440 ;
      RECT 2243.440 4.080 2244.640 1331.440 ;
      RECT 2254.320 4.080 2255.520 1331.440 ;
      RECT 2265.200 4.080 2266.400 1331.440 ;
      RECT 2276.080 4.080 2277.280 1331.440 ;
      RECT 2286.960 4.080 2288.160 1331.440 ;
      RECT 2297.840 4.080 2299.040 1331.440 ;
      RECT 2308.720 4.080 2309.920 1331.440 ;
      RECT 2319.600 4.080 2320.800 1331.440 ;
      RECT 2330.480 4.080 2331.680 1331.440 ;
      RECT 2341.360 4.080 2342.560 1331.440 ;
      RECT 2352.240 4.080 2353.440 1331.440 ;
      RECT 2363.120 4.080 2364.320 1331.440 ;
      RECT 2374.000 4.080 2375.200 1331.440 ;
      RECT 2384.880 4.080 2386.080 1331.440 ;
      RECT 2395.760 4.080 2396.960 1331.440 ;
      RECT 2406.640 4.080 2407.840 1331.440 ;
      RECT 2417.520 4.080 2418.720 1331.440 ;
      RECT 2428.400 4.080 2429.600 1331.440 ;
      RECT 2439.280 4.080 2440.480 1331.440 ;
      RECT 2450.160 4.080 2451.360 1331.440 ;
      RECT 2461.040 4.080 2462.240 1331.440 ;
      RECT 2471.920 4.080 2473.120 1331.440 ;
      RECT 2482.800 4.080 2484.000 1331.440 ;
      RECT 2493.680 4.080 2494.880 1331.440 ;
      RECT 2504.560 4.080 2505.760 1331.440 ;
      RECT 2515.440 4.080 2516.640 1331.440 ;
      RECT 2526.320 4.080 2527.520 1331.440 ;
      RECT 2537.200 4.080 2538.400 1331.440 ;
      RECT 2548.080 4.080 2549.280 1331.440 ;
      RECT 2558.960 4.080 2560.160 1331.440 ;
      RECT 2569.840 4.080 2571.040 1331.440 ;
      RECT 2580.720 4.080 2581.920 1331.440 ;
      RECT 2591.600 4.080 2592.800 1331.440 ;
      RECT 2602.480 4.080 2603.680 1331.440 ;
      RECT 2613.360 4.080 2614.560 1331.440 ;
      RECT 2624.240 4.080 2625.440 1331.440 ;
      RECT 2635.120 4.080 2636.320 1331.440 ;
      RECT 2646.000 4.080 2647.200 1331.440 ;
      RECT 2656.880 4.080 2658.080 1331.440 ;
    END
  END VDD
  OBS
    LAYER met1 ;
    RECT 0 0 2658.340 1335.520 ;
    LAYER met2 ;
    RECT 0 0 2658.340 1335.520 ;
    LAYER met3 ;
    RECT 0 0 2658.340 1335.520 ;
    LAYER met4 ;
    RECT 0 0 2658.340 1335.520 ;
  END
END fakeram_512x512_1r1w

END LIBRARY
